VERSION 5.7 ;
  NOWIREEXTENSIONATPIN ON ;
  DIVIDERCHAR "/" ;
  BUSBITCHARS "[]" ;
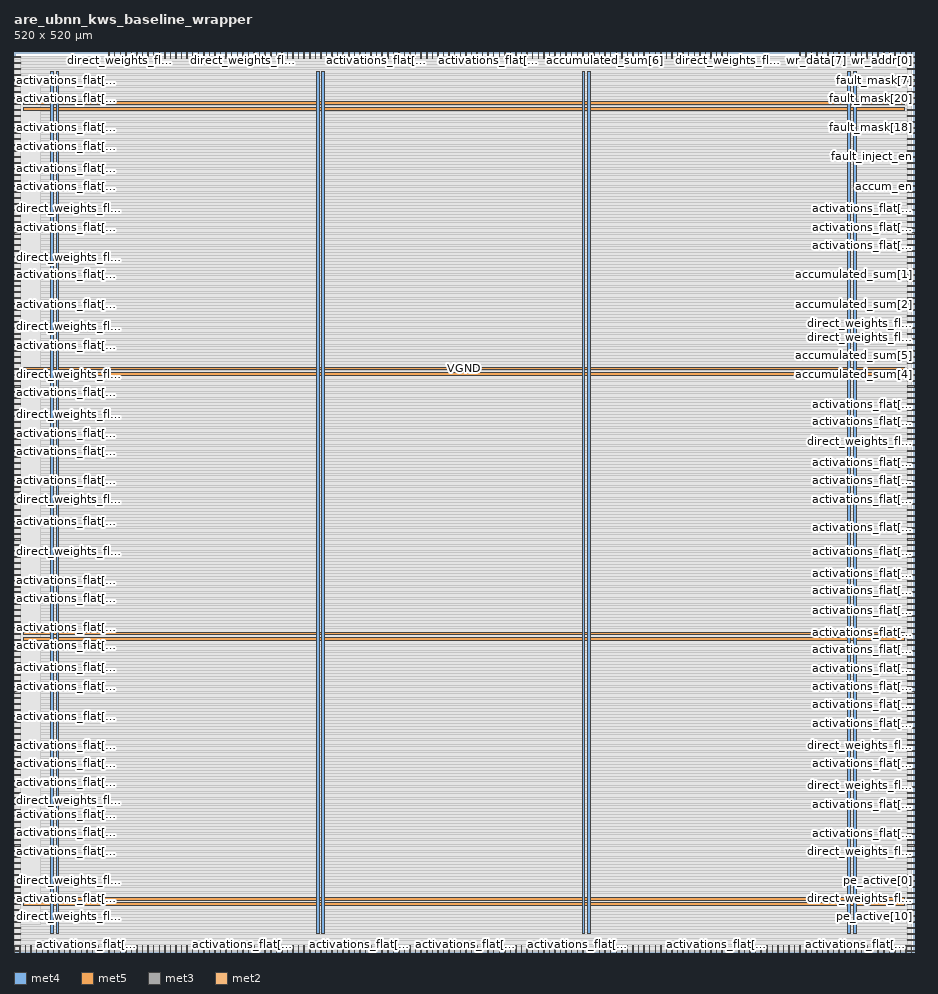
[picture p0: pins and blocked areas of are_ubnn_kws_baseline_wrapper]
MACRO are_ubnn_kws_baseline_wrapper
  CLASS BLOCK ;
  FOREIGN are_ubnn_kws_baseline_wrapper ;
  ORIGIN 0.000 0.000 ;
  SIZE 520.000 BY 520.000 ;
  PIN VGND
    DIRECTION INOUT ;
    USE GROUND ;
    PORT
      LAYER met4 ;
        RECT 24.340 10.640 25.940 508.880 ;
    END
    PORT
      LAYER met4 ;
        RECT 177.940 10.640 179.540 508.880 ;
    END
    PORT
      LAYER met4 ;
        RECT 331.540 10.640 333.140 508.880 ;
    END
    PORT
      LAYER met4 ;
        RECT 485.140 10.640 486.740 508.880 ;
    END
    PORT
      LAYER met5 ;
        RECT 5.280 30.030 514.520 31.630 ;
    END
    PORT
      LAYER met5 ;
        RECT 5.280 183.210 514.520 184.810 ;
    END
    PORT
      LAYER met5 ;
        RECT 5.280 336.390 514.520 337.990 ;
    END
    PORT
      LAYER met5 ;
        RECT 5.280 489.570 514.520 491.170 ;
    END
  END VGND
  PIN VPWR
    DIRECTION INOUT ;
    USE POWER ;
    PORT
      LAYER met4 ;
        RECT 21.040 10.640 22.640 508.880 ;
    END
    PORT
      LAYER met4 ;
        RECT 174.640 10.640 176.240 508.880 ;
    END
    PORT
      LAYER met4 ;
        RECT 328.240 10.640 329.840 508.880 ;
    END
    PORT
      LAYER met4 ;
        RECT 481.840 10.640 483.440 508.880 ;
    END
    PORT
      LAYER met5 ;
        RECT 5.280 26.730 514.520 28.330 ;
    END
    PORT
      LAYER met5 ;
        RECT 5.280 179.910 514.520 181.510 ;
    END
    PORT
      LAYER met5 ;
        RECT 5.280 333.090 514.520 334.690 ;
    END
    PORT
      LAYER met5 ;
        RECT 5.280 486.270 514.520 487.870 ;
    END
  END VPWR
  PIN accum_en
    DIRECTION INPUT ;
    USE SIGNAL ;
    ANTENNAGATEAREA 0.426000 ;
    PORT
      LAYER met3 ;
        RECT 516.000 442.040 520.000 442.640 ;
    END
  END accum_en
  PIN accum_valid
    DIRECTION OUTPUT ;
    USE SIGNAL ;
    ANTENNADIFFAREA 0.891000 ;
    PORT
      LAYER met2 ;
        RECT 409.030 516.000 409.310 520.000 ;
    END
  END accum_valid
  PIN accumulated_sum[0]
    DIRECTION OUTPUT ;
    USE SIGNAL ;
    ANTENNADIFFAREA 0.891000 ;
    PORT
      LAYER met3 ;
        RECT 516.000 411.440 520.000 412.040 ;
    END
  END accumulated_sum[0]
  PIN accumulated_sum[1]
    DIRECTION OUTPUT ;
    USE SIGNAL ;
    ANTENNADIFFAREA 0.891000 ;
    PORT
      LAYER met3 ;
        RECT 516.000 391.040 520.000 391.640 ;
    END
  END accumulated_sum[1]
  PIN accumulated_sum[2]
    DIRECTION OUTPUT ;
    USE SIGNAL ;
    ANTENNADIFFAREA 0.891000 ;
    PORT
      LAYER met3 ;
        RECT 516.000 374.040 520.000 374.640 ;
    END
  END accumulated_sum[2]
  PIN accumulated_sum[3]
    DIRECTION OUTPUT ;
    USE SIGNAL ;
    ANTENNADIFFAREA 0.891000 ;
    PORT
      LAYER met3 ;
        RECT 516.000 397.840 520.000 398.440 ;
    END
  END accumulated_sum[3]
  PIN accumulated_sum[4]
    DIRECTION OUTPUT ;
    USE SIGNAL ;
    ANTENNADIFFAREA 0.891000 ;
    PORT
      LAYER met3 ;
        RECT 516.000 333.240 520.000 333.840 ;
    END
  END accumulated_sum[4]
  PIN accumulated_sum[5]
    DIRECTION OUTPUT ;
    USE SIGNAL ;
    ANTENNADIFFAREA 0.891000 ;
    PORT
      LAYER met3 ;
        RECT 516.000 340.040 520.000 340.640 ;
    END
  END accumulated_sum[5]
  PIN accumulated_sum[6]
    DIRECTION OUTPUT ;
    USE SIGNAL ;
    ANTENNADIFFAREA 0.891000 ;
    PORT
      LAYER met2 ;
        RECT 341.410 516.000 341.690 520.000 ;
    END
  END accumulated_sum[6]
  PIN accumulated_sum[7]
    DIRECTION OUTPUT ;
    USE SIGNAL ;
    ANTENNADIFFAREA 0.891000 ;
    PORT
      LAYER met2 ;
        RECT 357.510 516.000 357.790 520.000 ;
    END
  END accumulated_sum[7]
  PIN accumulated_sum[8]
    DIRECTION OUTPUT ;
    USE SIGNAL ;
    ANTENNADIFFAREA 0.891000 ;
    PORT
      LAYER met2 ;
        RECT 347.850 516.000 348.130 520.000 ;
    END
  END accumulated_sum[8]
  PIN activations_flat[0]
    DIRECTION INPUT ;
    USE SIGNAL ;
    ANTENNAGATEAREA 0.196500 ;
    PORT
      LAYER met3 ;
        RECT 0.000 272.040 4.000 272.640 ;
    END
  END activations_flat[0]
  PIN activations_flat[100]
    DIRECTION INPUT ;
    USE SIGNAL ;
    ANTENNAGATEAREA 0.196500 ;
    PORT
      LAYER met2 ;
        RECT 177.190 0.000 177.470 4.000 ;
    END
  END activations_flat[100]
  PIN activations_flat[101]
    DIRECTION INPUT ;
    USE SIGNAL ;
    ANTENNAGATEAREA 0.213000 ;
    PORT
      LAYER met2 ;
        RECT 457.330 0.000 457.610 4.000 ;
    END
  END activations_flat[101]
  PIN activations_flat[102]
    DIRECTION INPUT ;
    USE SIGNAL ;
    ANTENNAGATEAREA 0.196500 ;
    PORT
      LAYER met2 ;
        RECT 222.270 0.000 222.550 4.000 ;
    END
  END activations_flat[102]
  PIN activations_flat[103]
    DIRECTION INPUT ;
    USE SIGNAL ;
    ANTENNAGATEAREA 0.213000 ;
    PORT
      LAYER met2 ;
        RECT 486.310 0.000 486.590 4.000 ;
    END
  END activations_flat[103]
  PIN activations_flat[104]
    DIRECTION INPUT ;
    USE SIGNAL ;
    ANTENNAGATEAREA 0.196500 ;
    PORT
      LAYER met2 ;
        RECT 225.490 0.000 225.770 4.000 ;
    END
  END activations_flat[104]
  PIN activations_flat[105]
    DIRECTION INPUT ;
    USE SIGNAL ;
    ANTENNAGATEAREA 0.196500 ;
    PORT
      LAYER met2 ;
        RECT 254.470 0.000 254.750 4.000 ;
    END
  END activations_flat[105]
  PIN activations_flat[106]
    DIRECTION INPUT ;
    USE SIGNAL ;
    ANTENNAGATEAREA 0.196500 ;
    PORT
      LAYER met2 ;
        RECT 235.150 0.000 235.430 4.000 ;
    END
  END activations_flat[106]
  PIN activations_flat[107]
    DIRECTION INPUT ;
    USE SIGNAL ;
    ANTENNAGATEAREA 0.213000 ;
    PORT
      LAYER met2 ;
        RECT 492.750 0.000 493.030 4.000 ;
    END
  END activations_flat[107]
  PIN activations_flat[108]
    DIRECTION INPUT ;
    USE SIGNAL ;
    ANTENNAGATEAREA 0.196500 ;
    PORT
      LAYER met2 ;
        RECT 238.370 0.000 238.650 4.000 ;
    END
  END activations_flat[108]
  PIN activations_flat[109]
    DIRECTION INPUT ;
    USE SIGNAL ;
    ANTENNAGATEAREA 0.196500 ;
    PORT
      LAYER met2 ;
        RECT 264.130 0.000 264.410 4.000 ;
    END
  END activations_flat[109]
  PIN activations_flat[10]
    DIRECTION INPUT ;
    USE SIGNAL ;
    ANTENNAGATEAREA 0.196500 ;
    PORT
      LAYER met3 ;
        RECT 0.000 292.440 4.000 293.040 ;
    END
  END activations_flat[10]
  PIN activations_flat[110]
    DIRECTION INPUT ;
    USE SIGNAL ;
    ANTENNAGATEAREA 0.196500 ;
    PORT
      LAYER met2 ;
        RECT 244.810 0.000 245.090 4.000 ;
    END
  END activations_flat[110]
  PIN activations_flat[111]
    DIRECTION INPUT ;
    USE SIGNAL ;
    ANTENNAGATEAREA 0.196500 ;
    PORT
      LAYER met2 ;
        RECT 215.830 0.000 216.110 4.000 ;
    END
  END activations_flat[111]
  PIN activations_flat[112]
    DIRECTION INPUT ;
    USE SIGNAL ;
    ANTENNAGATEAREA 0.196500 ;
    PORT
      LAYER met2 ;
        RECT 132.110 0.000 132.390 4.000 ;
    END
  END activations_flat[112]
  PIN activations_flat[113]
    DIRECTION INPUT ;
    USE SIGNAL ;
    ANTENNAGATEAREA 0.196500 ;
    PORT
      LAYER met3 ;
        RECT 0.000 57.840 4.000 58.440 ;
    END
  END activations_flat[113]
  PIN activations_flat[114]
    DIRECTION INPUT ;
    USE SIGNAL ;
    ANTENNAGATEAREA 0.126000 ;
    PORT
      LAYER met3 ;
        RECT 0.000 108.840 4.000 109.440 ;
    END
  END activations_flat[114]
  PIN activations_flat[115]
    DIRECTION INPUT ;
    USE SIGNAL ;
    ANTENNAGATEAREA 0.196500 ;
    PORT
      LAYER met2 ;
        RECT 80.590 0.000 80.870 4.000 ;
    END
  END activations_flat[115]
  PIN activations_flat[116]
    DIRECTION INPUT ;
    USE SIGNAL ;
    ANTENNAGATEAREA 0.126000 ;
    PORT
      LAYER met3 ;
        RECT 0.000 153.040 4.000 153.640 ;
    END
  END activations_flat[116]
  PIN activations_flat[117]
    DIRECTION INPUT ;
    USE SIGNAL ;
    ANTENNAGATEAREA 0.196500 ;
    PORT
      LAYER met2 ;
        RECT 170.750 0.000 171.030 4.000 ;
    END
  END activations_flat[117]
  PIN activations_flat[118]
    DIRECTION INPUT ;
    USE SIGNAL ;
    ANTENNAGATEAREA 0.196500 ;
    PORT
      LAYER met2 ;
        RECT 106.350 0.000 106.630 4.000 ;
    END
  END activations_flat[118]
  PIN activations_flat[119]
    DIRECTION INPUT ;
    USE SIGNAL ;
    ANTENNAGATEAREA 0.196500 ;
    PORT
      LAYER met2 ;
        RECT 109.570 0.000 109.850 4.000 ;
    END
  END activations_flat[119]
  PIN activations_flat[11]
    DIRECTION INPUT ;
    USE SIGNAL ;
    ANTENNAGATEAREA 0.196500 ;
    PORT
      LAYER met3 ;
        RECT 0.000 489.640 4.000 490.240 ;
    END
  END activations_flat[11]
  PIN activations_flat[120]
    DIRECTION INPUT ;
    USE SIGNAL ;
    ANTENNAGATEAREA 0.196500 ;
    PORT
      LAYER met2 ;
        RECT 96.690 0.000 96.970 4.000 ;
    END
  END activations_flat[120]
  PIN activations_flat[121]
    DIRECTION INPUT ;
    USE SIGNAL ;
    ANTENNAGATEAREA 0.196500 ;
    PORT
      LAYER met2 ;
        RECT 199.730 0.000 200.010 4.000 ;
    END
  END activations_flat[121]
  PIN activations_flat[122]
    DIRECTION INPUT ;
    USE SIGNAL ;
    ANTENNAGATEAREA 0.196500 ;
    PORT
      LAYER met2 ;
        RECT 183.630 0.000 183.910 4.000 ;
    END
  END activations_flat[122]
  PIN activations_flat[123]
    DIRECTION INPUT ;
    USE SIGNAL ;
    ANTENNAGATEAREA 0.196500 ;
    PORT
      LAYER met2 ;
        RECT 209.390 0.000 209.670 4.000 ;
    END
  END activations_flat[123]
  PIN activations_flat[124]
    DIRECTION INPUT ;
    USE SIGNAL ;
    ANTENNAGATEAREA 0.196500 ;
    PORT
      LAYER met2 ;
        RECT 193.290 0.000 193.570 4.000 ;
    END
  END activations_flat[124]
  PIN activations_flat[125]
    DIRECTION INPUT ;
    USE SIGNAL ;
    ANTENNAGATEAREA 0.196500 ;
    PORT
      LAYER met2 ;
        RECT 135.330 0.000 135.610 4.000 ;
    END
  END activations_flat[125]
  PIN activations_flat[126]
    DIRECTION INPUT ;
    USE SIGNAL ;
    ANTENNAGATEAREA 0.196500 ;
    PORT
      LAYER met2 ;
        RECT 190.070 0.000 190.350 4.000 ;
    END
  END activations_flat[126]
  PIN activations_flat[127]
    DIRECTION INPUT ;
    USE SIGNAL ;
    ANTENNAGATEAREA 0.196500 ;
    PORT
      LAYER met2 ;
        RECT 67.710 0.000 67.990 4.000 ;
    END
  END activations_flat[127]
  PIN activations_flat[128]
    DIRECTION INPUT ;
    USE SIGNAL ;
    ANTENNAGATEAREA 0.196500 ;
    PORT
      LAYER met2 ;
        RECT 479.870 0.000 480.150 4.000 ;
    END
  END activations_flat[128]
  PIN activations_flat[129]
    DIRECTION INPUT ;
    USE SIGNAL ;
    ANTENNAGATEAREA 0.196500 ;
    PORT
      LAYER met2 ;
        RECT 325.310 0.000 325.590 4.000 ;
    END
  END activations_flat[129]
  PIN activations_flat[12]
    DIRECTION INPUT ;
    USE SIGNAL ;
    ANTENNAGATEAREA 0.213000 ;
    PORT
      LAYER met3 ;
        RECT 0.000 496.440 4.000 497.040 ;
    END
  END activations_flat[12]
  PIN activations_flat[130]
    DIRECTION INPUT ;
    USE SIGNAL ;
    ANTENNAGATEAREA 0.196500 ;
    PORT
      LAYER met2 ;
        RECT 363.950 0.000 364.230 4.000 ;
    END
  END activations_flat[130]
  PIN activations_flat[131]
    DIRECTION INPUT ;
    USE SIGNAL ;
    ANTENNAGATEAREA 0.196500 ;
    PORT
      LAYER met2 ;
        RECT 357.510 0.000 357.790 4.000 ;
    END
  END activations_flat[131]
  PIN activations_flat[132]
    DIRECTION INPUT ;
    USE SIGNAL ;
    ANTENNAGATEAREA 0.196500 ;
    PORT
      LAYER met2 ;
        RECT 299.550 0.000 299.830 4.000 ;
    END
  END activations_flat[132]
  PIN activations_flat[133]
    DIRECTION INPUT ;
    USE SIGNAL ;
    ANTENNAGATEAREA 0.196500 ;
    PORT
      LAYER met2 ;
        RECT 428.350 0.000 428.630 4.000 ;
    END
  END activations_flat[133]
  PIN activations_flat[134]
    DIRECTION INPUT ;
    USE SIGNAL ;
    ANTENNAGATEAREA 0.196500 ;
    PORT
      LAYER met2 ;
        RECT 418.690 0.000 418.970 4.000 ;
    END
  END activations_flat[134]
  PIN activations_flat[135]
    DIRECTION INPUT ;
    USE SIGNAL ;
    ANTENNAGATEAREA 0.196500 ;
    PORT
      LAYER met2 ;
        RECT 438.010 0.000 438.290 4.000 ;
    END
  END activations_flat[135]
  PIN activations_flat[136]
    DIRECTION INPUT ;
    USE SIGNAL ;
    ANTENNAGATEAREA 0.196500 ;
    PORT
      LAYER met2 ;
        RECT 302.770 0.000 303.050 4.000 ;
    END
  END activations_flat[136]
  PIN activations_flat[137]
    DIRECTION INPUT ;
    USE SIGNAL ;
    ANTENNAGATEAREA 0.196500 ;
    PORT
      LAYER met2 ;
        RECT 351.070 0.000 351.350 4.000 ;
    END
  END activations_flat[137]
  PIN activations_flat[138]
    DIRECTION INPUT ;
    USE SIGNAL ;
    ANTENNAGATEAREA 0.196500 ;
    PORT
      LAYER met2 ;
        RECT 463.770 0.000 464.050 4.000 ;
    END
  END activations_flat[138]
  PIN activations_flat[139]
    DIRECTION INPUT ;
    USE SIGNAL ;
    ANTENNAGATEAREA 0.196500 ;
    PORT
      LAYER met2 ;
        RECT 505.630 0.000 505.910 4.000 ;
    END
  END activations_flat[139]
  PIN activations_flat[13]
    DIRECTION INPUT ;
    USE SIGNAL ;
    ANTENNAGATEAREA 0.213000 ;
    PORT
      LAYER met3 ;
        RECT 0.000 472.640 4.000 473.240 ;
    END
  END activations_flat[13]
  PIN activations_flat[140]
    DIRECTION INPUT ;
    USE SIGNAL ;
    ANTENNAGATEAREA 0.196500 ;
    PORT
      LAYER met2 ;
        RECT 370.390 0.000 370.670 4.000 ;
    END
  END activations_flat[140]
  PIN activations_flat[141]
    DIRECTION INPUT ;
    USE SIGNAL ;
    ANTENNAGATEAREA 0.196500 ;
    PORT
      LAYER met2 ;
        RECT 405.810 0.000 406.090 4.000 ;
    END
  END activations_flat[141]
  PIN activations_flat[142]
    DIRECTION INPUT ;
    USE SIGNAL ;
    ANTENNAGATEAREA 0.196500 ;
    PORT
      LAYER met2 ;
        RECT 354.290 0.000 354.570 4.000 ;
    END
  END activations_flat[142]
  PIN activations_flat[143]
    DIRECTION INPUT ;
    USE SIGNAL ;
    ANTENNAGATEAREA 0.196500 ;
    PORT
      LAYER met2 ;
        RECT 444.450 0.000 444.730 4.000 ;
    END
  END activations_flat[143]
  PIN activations_flat[144]
    DIRECTION INPUT ;
    USE SIGNAL ;
    ANTENNAGATEAREA 0.196500 ;
    PORT
      LAYER met2 ;
        RECT 260.910 0.000 261.190 4.000 ;
    END
  END activations_flat[144]
  PIN activations_flat[145]
    DIRECTION INPUT ;
    USE SIGNAL ;
    ANTENNAGATEAREA 0.196500 ;
    PORT
      LAYER met2 ;
        RECT 77.370 0.000 77.650 4.000 ;
    END
  END activations_flat[145]
  PIN activations_flat[146]
    DIRECTION INPUT ;
    USE SIGNAL ;
    ANTENNAGATEAREA 0.213000 ;
    PORT
      LAYER met2 ;
        RECT 141.770 0.000 142.050 4.000 ;
    END
  END activations_flat[146]
  PIN activations_flat[147]
    DIRECTION INPUT ;
    USE SIGNAL ;
    ANTENNAGATEAREA 0.213000 ;
    PORT
      LAYER met3 ;
        RECT 516.000 231.240 520.000 231.840 ;
    END
  END activations_flat[147]
  PIN activations_flat[148]
    DIRECTION INPUT ;
    USE SIGNAL ;
    ANTENNAGATEAREA 0.126000 ;
    PORT
      LAYER met2 ;
        RECT 22.630 0.000 22.910 4.000 ;
    END
  END activations_flat[148]
  PIN activations_flat[149]
    DIRECTION INPUT ;
    USE SIGNAL ;
    ANTENNAGATEAREA 0.196500 ;
    PORT
      LAYER met2 ;
        RECT 289.890 0.000 290.170 4.000 ;
    END
  END activations_flat[149]
  PIN activations_flat[14]
    DIRECTION INPUT ;
    USE SIGNAL ;
    ANTENNAGATEAREA 0.213000 ;
    PORT
      LAYER met3 ;
        RECT 0.000 516.840 4.000 517.440 ;
    END
  END activations_flat[14]
  PIN activations_flat[150]
    DIRECTION INPUT ;
    USE SIGNAL ;
    ANTENNAGATEAREA 0.213000 ;
    PORT
      LAYER met2 ;
        RECT 41.950 0.000 42.230 4.000 ;
    END
  END activations_flat[150]
  PIN activations_flat[151]
    DIRECTION INPUT ;
    USE SIGNAL ;
    ANTENNAGATEAREA 0.196500 ;
    PORT
      LAYER met2 ;
        RECT 473.430 0.000 473.710 4.000 ;
    END
  END activations_flat[151]
  PIN activations_flat[152]
    DIRECTION INPUT ;
    USE SIGNAL ;
    ANTENNAGATEAREA 0.196500 ;
    PORT
      LAYER met2 ;
        RECT 112.790 0.000 113.070 4.000 ;
    END
  END activations_flat[152]
  PIN activations_flat[153]
    DIRECTION INPUT ;
    USE SIGNAL ;
    ANTENNAGATEAREA 0.213000 ;
    PORT
      LAYER met2 ;
        RECT 495.970 0.000 496.250 4.000 ;
    END
  END activations_flat[153]
  PIN activations_flat[154]
    DIRECTION INPUT ;
    USE SIGNAL ;
    ANTENNAGATEAREA 0.213000 ;
    PORT
      LAYER met2 ;
        RECT 19.410 0.000 19.690 4.000 ;
    END
  END activations_flat[154]
  PIN activations_flat[155]
    DIRECTION INPUT ;
    USE SIGNAL ;
    ANTENNAGATEAREA 0.196500 ;
    PORT
      LAYER met2 ;
        RECT 283.450 0.000 283.730 4.000 ;
    END
  END activations_flat[155]
  PIN activations_flat[156]
    DIRECTION INPUT ;
    USE SIGNAL ;
    ANTENNAGATEAREA 0.196500 ;
    PORT
      LAYER met2 ;
        RECT 12.970 0.000 13.250 4.000 ;
    END
  END activations_flat[156]
  PIN activations_flat[157]
    DIRECTION INPUT ;
    USE SIGNAL ;
    ANTENNAGATEAREA 0.213000 ;
    PORT
      LAYER met2 ;
        RECT 502.410 0.000 502.690 4.000 ;
    END
  END activations_flat[157]
  PIN activations_flat[158]
    DIRECTION INPUT ;
    USE SIGNAL ;
    ANTENNAGATEAREA 0.196500 ;
    PORT
      LAYER met2 ;
        RECT 48.390 0.000 48.670 4.000 ;
    END
  END activations_flat[158]
  PIN activations_flat[159]
    DIRECTION INPUT ;
    USE SIGNAL ;
    ANTENNAGATEAREA 0.196500 ;
    PORT
      LAYER met2 ;
        RECT 144.990 0.000 145.270 4.000 ;
    END
  END activations_flat[159]
  PIN activations_flat[15]
    DIRECTION INPUT ;
    USE SIGNAL ;
    ANTENNAGATEAREA 0.196500 ;
    PORT
      LAYER met3 ;
        RECT 0.000 295.840 4.000 296.440 ;
    END
  END activations_flat[15]
  PIN activations_flat[160]
    DIRECTION INPUT ;
    USE SIGNAL ;
    ANTENNAGATEAREA 0.196500 ;
    PORT
      LAYER met3 ;
        RECT 0.000 248.240 4.000 248.840 ;
    END
  END activations_flat[160]
  PIN activations_flat[161]
    DIRECTION INPUT ;
    USE SIGNAL ;
    ANTENNAGATEAREA 0.196500 ;
    PORT
      LAYER met3 ;
        RECT 0.000 244.840 4.000 245.440 ;
    END
  END activations_flat[161]
  PIN activations_flat[162]
    DIRECTION INPUT ;
    USE SIGNAL ;
    ANTENNAGATEAREA 0.213000 ;
    PORT
      LAYER met3 ;
        RECT 0.000 6.840 4.000 7.440 ;
    END
  END activations_flat[162]
  PIN activations_flat[163]
    DIRECTION INPUT ;
    USE SIGNAL ;
    ANTENNAGATEAREA 0.196500 ;
    PORT
      LAYER met2 ;
        RECT 277.010 0.000 277.290 4.000 ;
    END
  END activations_flat[163]
  PIN activations_flat[164]
    DIRECTION INPUT ;
    USE SIGNAL ;
    ANTENNAGATEAREA 0.196500 ;
    PORT
      LAYER met3 ;
        RECT 0.000 166.640 4.000 167.240 ;
    END
  END activations_flat[164]
  PIN activations_flat[165]
    DIRECTION INPUT ;
    USE SIGNAL ;
    ANTENNAGATEAREA 0.126000 ;
    PORT
      LAYER met2 ;
        RECT 0.090 0.000 0.370 4.000 ;
    END
  END activations_flat[165]
  PIN activations_flat[166]
    DIRECTION INPUT ;
    USE SIGNAL ;
    ANTENNAGATEAREA 0.126000 ;
    PORT
      LAYER met3 ;
        RECT 0.000 112.240 4.000 112.840 ;
    END
  END activations_flat[166]
  PIN activations_flat[167]
    DIRECTION INPUT ;
    USE SIGNAL ;
    ANTENNAGATEAREA 0.196500 ;
    PORT
      LAYER met2 ;
        RECT 267.350 0.000 267.630 4.000 ;
    END
  END activations_flat[167]
  PIN activations_flat[168]
    DIRECTION INPUT ;
    USE SIGNAL ;
    ANTENNAGATEAREA 0.196500 ;
    PORT
      LAYER met3 ;
        RECT 0.000 214.240 4.000 214.840 ;
    END
  END activations_flat[168]
  PIN activations_flat[169]
    DIRECTION INPUT ;
    USE SIGNAL ;
    ANTENNAGATEAREA 0.196500 ;
    PORT
      LAYER met3 ;
        RECT 0.000 234.640 4.000 235.240 ;
    END
  END activations_flat[169]
  PIN activations_flat[16]
    DIRECTION INPUT ;
    USE SIGNAL ;
    ANTENNAGATEAREA 0.196500 ;
    PORT
      LAYER met3 ;
        RECT 0.000 387.640 4.000 388.240 ;
    END
  END activations_flat[16]
  PIN activations_flat[170]
    DIRECTION INPUT ;
    USE SIGNAL ;
    ANTENNAGATEAREA 0.196500 ;
    PORT
      LAYER met3 ;
        RECT 0.000 251.640 4.000 252.240 ;
    END
  END activations_flat[170]
  PIN activations_flat[171]
    DIRECTION INPUT ;
    USE SIGNAL ;
    ANTENNAGATEAREA 0.196500 ;
    PORT
      LAYER met3 ;
        RECT 0.000 255.040 4.000 255.640 ;
    END
  END activations_flat[171]
  PIN activations_flat[172]
    DIRECTION INPUT ;
    USE SIGNAL ;
    ANTENNAGATEAREA 0.213000 ;
    PORT
      LAYER met3 ;
        RECT 0.000 513.440 4.000 514.040 ;
    END
  END activations_flat[172]
  PIN activations_flat[173]
    DIRECTION INPUT ;
    USE SIGNAL ;
    ANTENNAGATEAREA 0.196500 ;
    PORT
      LAYER met3 ;
        RECT 0.000 261.840 4.000 262.440 ;
    END
  END activations_flat[173]
  PIN activations_flat[174]
    DIRECTION INPUT ;
    USE SIGNAL ;
    ANTENNAGATEAREA 0.196500 ;
    PORT
      LAYER met3 ;
        RECT 0.000 343.440 4.000 344.040 ;
    END
  END activations_flat[174]
  PIN activations_flat[175]
    DIRECTION INPUT ;
    USE SIGNAL ;
    ANTENNAGATEAREA 0.196500 ;
    PORT
      LAYER met3 ;
        RECT 0.000 183.640 4.000 184.240 ;
    END
  END activations_flat[175]
  PIN activations_flat[176]
    DIRECTION INPUT ;
    USE SIGNAL ;
    ANTENNAGATEAREA 0.196500 ;
    PORT
      LAYER met2 ;
        RECT 318.870 516.000 319.150 520.000 ;
    END
  END activations_flat[176]
  PIN activations_flat[177]
    DIRECTION INPUT ;
    USE SIGNAL ;
    ANTENNAGATEAREA 0.196500 ;
    PORT
      LAYER met2 ;
        RECT 389.710 516.000 389.990 520.000 ;
    END
  END activations_flat[177]
  PIN activations_flat[178]
    DIRECTION INPUT ;
    USE SIGNAL ;
    ANTENNAGATEAREA 0.196500 ;
    PORT
      LAYER met2 ;
        RECT 399.370 516.000 399.650 520.000 ;
    END
  END activations_flat[178]
  PIN activations_flat[179]
    DIRECTION INPUT ;
    USE SIGNAL ;
    ANTENNAGATEAREA 0.196500 ;
    PORT
      LAYER met2 ;
        RECT 309.210 516.000 309.490 520.000 ;
    END
  END activations_flat[179]
  PIN activations_flat[17]
    DIRECTION INPUT ;
    USE SIGNAL ;
    ANTENNAGATEAREA 0.126000 ;
    PORT
      LAYER met3 ;
        RECT 0.000 462.440 4.000 463.040 ;
    END
  END activations_flat[17]
  PIN activations_flat[180]
    DIRECTION INPUT ;
    USE SIGNAL ;
    ANTENNAGATEAREA 0.196500 ;
    PORT
      LAYER met2 ;
        RECT 383.270 516.000 383.550 520.000 ;
    END
  END activations_flat[180]
  PIN activations_flat[181]
    DIRECTION INPUT ;
    USE SIGNAL ;
    ANTENNAGATEAREA 0.196500 ;
    PORT
      LAYER met2 ;
        RECT 296.330 516.000 296.610 520.000 ;
    END
  END activations_flat[181]
  PIN activations_flat[182]
    DIRECTION INPUT ;
    USE SIGNAL ;
    ANTENNAGATEAREA 0.196500 ;
    PORT
      LAYER met2 ;
        RECT 392.930 516.000 393.210 520.000 ;
    END
  END activations_flat[182]
  PIN activations_flat[183]
    DIRECTION INPUT ;
    USE SIGNAL ;
    ANTENNAGATEAREA 0.196500 ;
    PORT
      LAYER met2 ;
        RECT 289.890 516.000 290.170 520.000 ;
    END
  END activations_flat[183]
  PIN activations_flat[184]
    DIRECTION INPUT ;
    USE SIGNAL ;
    ANTENNAGATEAREA 0.196500 ;
    PORT
      LAYER met2 ;
        RECT 402.590 516.000 402.870 520.000 ;
    END
  END activations_flat[184]
  PIN activations_flat[185]
    DIRECTION INPUT ;
    USE SIGNAL ;
    ANTENNAGATEAREA 0.196500 ;
    PORT
      LAYER met2 ;
        RECT 270.570 516.000 270.850 520.000 ;
    END
  END activations_flat[185]
  PIN activations_flat[186]
    DIRECTION INPUT ;
    USE SIGNAL ;
    ANTENNAGATEAREA 0.196500 ;
    PORT
      LAYER met2 ;
        RECT 376.830 516.000 377.110 520.000 ;
    END
  END activations_flat[186]
  PIN activations_flat[187]
    DIRECTION INPUT ;
    USE SIGNAL ;
    ANTENNAGATEAREA 0.196500 ;
    PORT
      LAYER met2 ;
        RECT 283.450 516.000 283.730 520.000 ;
    END
  END activations_flat[187]
  PIN activations_flat[188]
    DIRECTION INPUT ;
    USE SIGNAL ;
    ANTENNAGATEAREA 0.196500 ;
    PORT
      LAYER met2 ;
        RECT 264.130 516.000 264.410 520.000 ;
    END
  END activations_flat[188]
  PIN activations_flat[189]
    DIRECTION INPUT ;
    USE SIGNAL ;
    ANTENNAGATEAREA 0.196500 ;
    PORT
      LAYER met2 ;
        RECT 273.790 516.000 274.070 520.000 ;
    END
  END activations_flat[189]
  PIN activations_flat[18]
    DIRECTION INPUT ;
    USE SIGNAL ;
    ANTENNAGATEAREA 0.196500 ;
    PORT
      LAYER met3 ;
        RECT 0.000 323.040 4.000 323.640 ;
    END
  END activations_flat[18]
  PIN activations_flat[190]
    DIRECTION INPUT ;
    USE SIGNAL ;
    ANTENNAGATEAREA 0.196500 ;
    PORT
      LAYER met2 ;
        RECT 260.910 516.000 261.190 520.000 ;
    END
  END activations_flat[190]
  PIN activations_flat[191]
    DIRECTION INPUT ;
    USE SIGNAL ;
    ANTENNAGATEAREA 0.196500 ;
    PORT
      LAYER met2 ;
        RECT 251.250 516.000 251.530 520.000 ;
    END
  END activations_flat[191]
  PIN activations_flat[192]
    DIRECTION INPUT ;
    USE SIGNAL ;
    ANTENNAGATEAREA 0.196500 ;
    PORT
      LAYER met2 ;
        RECT 383.270 0.000 383.550 4.000 ;
    END
  END activations_flat[192]
  PIN activations_flat[193]
    DIRECTION INPUT ;
    USE SIGNAL ;
    ANTENNAGATEAREA 0.196500 ;
    PORT
      LAYER met2 ;
        RECT 315.650 0.000 315.930 4.000 ;
    END
  END activations_flat[193]
  PIN activations_flat[194]
    DIRECTION INPUT ;
    USE SIGNAL ;
    ANTENNAGATEAREA 0.196500 ;
    PORT
      LAYER met2 ;
        RECT 347.850 0.000 348.130 4.000 ;
    END
  END activations_flat[194]
  PIN activations_flat[195]
    DIRECTION INPUT ;
    USE SIGNAL ;
    ANTENNAGATEAREA 0.196500 ;
    PORT
      LAYER met3 ;
        RECT 516.000 51.040 520.000 51.640 ;
    END
  END activations_flat[195]
  PIN activations_flat[196]
    DIRECTION INPUT ;
    USE SIGNAL ;
    ANTENNAGATEAREA 0.196500 ;
    PORT
      LAYER met2 ;
        RECT 389.710 0.000 389.990 4.000 ;
    END
  END activations_flat[196]
  PIN activations_flat[197]
    DIRECTION INPUT ;
    USE SIGNAL ;
    ANTENNAGATEAREA 0.196500 ;
    PORT
      LAYER met3 ;
        RECT 516.000 68.040 520.000 68.640 ;
    END
  END activations_flat[197]
  PIN activations_flat[198]
    DIRECTION INPUT ;
    USE SIGNAL ;
    ANTENNAGATEAREA 0.196500 ;
    PORT
      LAYER met2 ;
        RECT 447.670 0.000 447.950 4.000 ;
    END
  END activations_flat[198]
  PIN activations_flat[199]
    DIRECTION INPUT ;
    USE SIGNAL ;
    ANTENNAGATEAREA 0.196500 ;
    PORT
      LAYER met3 ;
        RECT 516.000 64.640 520.000 65.240 ;
    END
  END activations_flat[199]
  PIN activations_flat[19]
    DIRECTION INPUT ;
    USE SIGNAL ;
    ANTENNAGATEAREA 0.126000 ;
    PORT
      LAYER met3 ;
        RECT 0.000 455.640 4.000 456.240 ;
    END
  END activations_flat[19]
  PIN activations_flat[1]
    DIRECTION INPUT ;
    USE SIGNAL ;
    ANTENNAGATEAREA 0.196500 ;
    PORT
      LAYER met3 ;
        RECT 0.000 312.840 4.000 313.440 ;
    END
  END activations_flat[1]
  PIN activations_flat[200]
    DIRECTION INPUT ;
    USE SIGNAL ;
    ANTENNAGATEAREA 0.196500 ;
    PORT
      LAYER met2 ;
        RECT 380.050 0.000 380.330 4.000 ;
    END
  END activations_flat[200]
  PIN activations_flat[201]
    DIRECTION INPUT ;
    USE SIGNAL ;
    ANTENNAGATEAREA 0.196500 ;
    PORT
      LAYER met2 ;
        RECT 499.190 0.000 499.470 4.000 ;
    END
  END activations_flat[201]
  PIN activations_flat[202]
    DIRECTION INPUT ;
    USE SIGNAL ;
    ANTENNAGATEAREA 0.126000 ;
    PORT
      LAYER met2 ;
        RECT 334.970 0.000 335.250 4.000 ;
    END
  END activations_flat[202]
  PIN activations_flat[203]
    DIRECTION INPUT ;
    USE SIGNAL ;
    ANTENNAGATEAREA 0.196500 ;
    PORT
      LAYER met2 ;
        RECT 518.510 0.000 518.790 4.000 ;
    END
  END activations_flat[203]
  PIN activations_flat[204]
    DIRECTION INPUT ;
    USE SIGNAL ;
    ANTENNAGATEAREA 0.196500 ;
    PORT
      LAYER met2 ;
        RECT 402.590 0.000 402.870 4.000 ;
    END
  END activations_flat[204]
  PIN activations_flat[205]
    DIRECTION INPUT ;
    USE SIGNAL ;
    ANTENNAGATEAREA 0.196500 ;
    PORT
      LAYER met2 ;
        RECT 373.610 0.000 373.890 4.000 ;
    END
  END activations_flat[205]
  PIN activations_flat[206]
    DIRECTION INPUT ;
    USE SIGNAL ;
    ANTENNAGATEAREA 0.196500 ;
    PORT
      LAYER met2 ;
        RECT 344.630 0.000 344.910 4.000 ;
    END
  END activations_flat[206]
  PIN activations_flat[207]
    DIRECTION INPUT ;
    USE SIGNAL ;
    ANTENNAGATEAREA 0.196500 ;
    PORT
      LAYER met2 ;
        RECT 328.530 0.000 328.810 4.000 ;
    END
  END activations_flat[207]
  PIN activations_flat[208]
    DIRECTION INPUT ;
    USE SIGNAL ;
    ANTENNAGATEAREA 0.196500 ;
    PORT
      LAYER met3 ;
        RECT 516.000 112.240 520.000 112.840 ;
    END
  END activations_flat[208]
  PIN activations_flat[209]
    DIRECTION INPUT ;
    USE SIGNAL ;
    ANTENNAGATEAREA 0.196500 ;
    PORT
      LAYER met3 ;
        RECT 516.000 122.440 520.000 123.040 ;
    END
  END activations_flat[209]
  PIN activations_flat[20]
    DIRECTION INPUT ;
    USE SIGNAL ;
    ANTENNAGATEAREA 0.196500 ;
    PORT
      LAYER met3 ;
        RECT 0.000 326.440 4.000 327.040 ;
    END
  END activations_flat[20]
  PIN activations_flat[210]
    DIRECTION INPUT ;
    USE SIGNAL ;
    ANTENNAGATEAREA 0.196500 ;
    PORT
      LAYER met3 ;
        RECT 516.000 105.440 520.000 106.040 ;
    END
  END activations_flat[210]
  PIN activations_flat[211]
    DIRECTION INPUT ;
    USE SIGNAL ;
    ANTENNAGATEAREA 0.126000 ;
    PORT
      LAYER met3 ;
        RECT 516.000 438.640 520.000 439.240 ;
    END
  END activations_flat[211]
  PIN activations_flat[212]
    DIRECTION INPUT ;
    USE SIGNAL ;
    ANTENNAGATEAREA 0.196500 ;
    PORT
      LAYER met3 ;
        RECT 516.000 132.640 520.000 133.240 ;
    END
  END activations_flat[212]
  PIN activations_flat[213]
    DIRECTION INPUT ;
    USE SIGNAL ;
    ANTENNAGATEAREA 0.126000 ;
    PORT
      LAYER met3 ;
        RECT 516.000 78.240 520.000 78.840 ;
    END
  END activations_flat[213]
  PIN activations_flat[214]
    DIRECTION INPUT ;
    USE SIGNAL ;
    ANTENNAGATEAREA 0.196500 ;
    PORT
      LAYER met3 ;
        RECT 516.000 149.640 520.000 150.240 ;
    END
  END activations_flat[214]
  PIN activations_flat[215]
    DIRECTION INPUT ;
    USE SIGNAL ;
    ANTENNAGATEAREA 0.196500 ;
    PORT
      LAYER met3 ;
        RECT 516.000 71.440 520.000 72.040 ;
    END
  END activations_flat[215]
  PIN activations_flat[216]
    DIRECTION INPUT ;
    USE SIGNAL ;
    ANTENNAGATEAREA 0.196500 ;
    PORT
      LAYER met3 ;
        RECT 516.000 163.240 520.000 163.840 ;
    END
  END activations_flat[216]
  PIN activations_flat[217]
    DIRECTION INPUT ;
    USE SIGNAL ;
    ANTENNAGATEAREA 0.196500 ;
    PORT
      LAYER met3 ;
        RECT 516.000 197.240 520.000 197.840 ;
    END
  END activations_flat[217]
  PIN activations_flat[218]
    DIRECTION INPUT ;
    USE SIGNAL ;
    ANTENNAGATEAREA 0.196500 ;
    PORT
      LAYER met3 ;
        RECT 516.000 170.040 520.000 170.640 ;
    END
  END activations_flat[218]
  PIN activations_flat[219]
    DIRECTION INPUT ;
    USE SIGNAL ;
    ANTENNAGATEAREA 0.196500 ;
    PORT
      LAYER met3 ;
        RECT 516.000 200.640 520.000 201.240 ;
    END
  END activations_flat[219]
  PIN activations_flat[21]
    DIRECTION INPUT ;
    USE SIGNAL ;
    ANTENNAGATEAREA 0.126000 ;
    PORT
      LAYER met3 ;
        RECT 0.000 503.240 4.000 503.840 ;
    END
  END activations_flat[21]
  PIN activations_flat[220]
    DIRECTION INPUT ;
    USE SIGNAL ;
    ANTENNAGATEAREA 0.196500 ;
    PORT
      LAYER met3 ;
        RECT 516.000 180.240 520.000 180.840 ;
    END
  END activations_flat[220]
  PIN activations_flat[221]
    DIRECTION INPUT ;
    USE SIGNAL ;
    ANTENNAGATEAREA 0.196500 ;
    PORT
      LAYER met3 ;
        RECT 516.000 142.840 520.000 143.440 ;
    END
  END activations_flat[221]
  PIN activations_flat[222]
    DIRECTION INPUT ;
    USE SIGNAL ;
    ANTENNAGATEAREA 0.196500 ;
    PORT
      LAYER met3 ;
        RECT 516.000 159.840 520.000 160.440 ;
    END
  END activations_flat[222]
  PIN activations_flat[223]
    DIRECTION INPUT ;
    USE SIGNAL ;
    ANTENNAGATEAREA 0.196500 ;
    PORT
      LAYER met3 ;
        RECT 516.000 153.040 520.000 153.640 ;
    END
  END activations_flat[223]
  PIN activations_flat[224]
    DIRECTION INPUT ;
    USE SIGNAL ;
    ANTENNAGATEAREA 0.196500 ;
    PORT
      LAYER met3 ;
        RECT 516.000 418.240 520.000 418.840 ;
    END
  END activations_flat[224]
  PIN activations_flat[225]
    DIRECTION INPUT ;
    USE SIGNAL ;
    ANTENNAGATEAREA 0.196500 ;
    PORT
      LAYER met3 ;
        RECT 516.000 353.640 520.000 354.240 ;
    END
  END activations_flat[225]
  PIN activations_flat[226]
    DIRECTION INPUT ;
    USE SIGNAL ;
    ANTENNAGATEAREA 0.196500 ;
    PORT
      LAYER met3 ;
        RECT 516.000 408.040 520.000 408.640 ;
    END
  END activations_flat[226]
  PIN activations_flat[227]
    DIRECTION INPUT ;
    USE SIGNAL ;
    ANTENNAGATEAREA 0.196500 ;
    PORT
      LAYER met3 ;
        RECT 516.000 306.040 520.000 306.640 ;
    END
  END activations_flat[227]
  PIN activations_flat[228]
    DIRECTION INPUT ;
    USE SIGNAL ;
    ANTENNAGATEAREA 0.196500 ;
    PORT
      LAYER met3 ;
        RECT 516.000 316.240 520.000 316.840 ;
    END
  END activations_flat[228]
  PIN activations_flat[229]
    DIRECTION INPUT ;
    USE SIGNAL ;
    ANTENNAGATEAREA 0.196500 ;
    PORT
      LAYER met3 ;
        RECT 516.000 309.440 520.000 310.040 ;
    END
  END activations_flat[229]
  PIN activations_flat[22]
    DIRECTION INPUT ;
    USE SIGNAL ;
    ANTENNAGATEAREA 0.196500 ;
    PORT
      LAYER met3 ;
        RECT 0.000 394.440 4.000 395.040 ;
    END
  END activations_flat[22]
  PIN activations_flat[230]
    DIRECTION INPUT ;
    USE SIGNAL ;
    ANTENNAGATEAREA 0.196500 ;
    PORT
      LAYER met3 ;
        RECT 516.000 323.040 520.000 323.640 ;
    END
  END activations_flat[230]
  PIN activations_flat[231]
    DIRECTION INPUT ;
    USE SIGNAL ;
    ANTENNAGATEAREA 0.196500 ;
    PORT
      LAYER met3 ;
        RECT 516.000 282.240 520.000 282.840 ;
    END
  END activations_flat[231]
  PIN activations_flat[232]
    DIRECTION INPUT ;
    USE SIGNAL ;
    ANTENNAGATEAREA 0.196500 ;
    PORT
      LAYER met3 ;
        RECT 516.000 414.840 520.000 415.440 ;
    END
  END activations_flat[232]
  PIN activations_flat[233]
    DIRECTION INPUT ;
    USE SIGNAL ;
    ANTENNAGATEAREA 0.196500 ;
    PORT
      LAYER met3 ;
        RECT 516.000 336.640 520.000 337.240 ;
    END
  END activations_flat[233]
  PIN activations_flat[234]
    DIRECTION INPUT ;
    USE SIGNAL ;
    ANTENNAGATEAREA 0.196500 ;
    PORT
      LAYER met3 ;
        RECT 516.000 370.640 520.000 371.240 ;
    END
  END activations_flat[234]
  PIN activations_flat[235]
    DIRECTION INPUT ;
    USE SIGNAL ;
    ANTENNAGATEAREA 0.196500 ;
    PORT
      LAYER met3 ;
        RECT 516.000 404.640 520.000 405.240 ;
    END
  END activations_flat[235]
  PIN activations_flat[236]
    DIRECTION INPUT ;
    USE SIGNAL ;
    ANTENNAGATEAREA 0.196500 ;
    PORT
      LAYER met3 ;
        RECT 516.000 384.240 520.000 384.840 ;
    END
  END activations_flat[236]
  PIN activations_flat[237]
    DIRECTION INPUT ;
    USE SIGNAL ;
    ANTENNAGATEAREA 0.196500 ;
    PORT
      LAYER met3 ;
        RECT 516.000 292.440 520.000 293.040 ;
    END
  END activations_flat[237]
  PIN activations_flat[238]
    DIRECTION INPUT ;
    USE SIGNAL ;
    ANTENNAGATEAREA 0.196500 ;
    PORT
      LAYER met3 ;
        RECT 516.000 312.840 520.000 313.440 ;
    END
  END activations_flat[238]
  PIN activations_flat[239]
    DIRECTION INPUT ;
    USE SIGNAL ;
    ANTENNAGATEAREA 0.196500 ;
    PORT
      LAYER met3 ;
        RECT 516.000 319.640 520.000 320.240 ;
    END
  END activations_flat[239]
  PIN activations_flat[23]
    DIRECTION INPUT ;
    USE SIGNAL ;
    ANTENNAGATEAREA 0.196500 ;
    PORT
      LAYER met3 ;
        RECT 0.000 476.040 4.000 476.640 ;
    END
  END activations_flat[23]
  PIN activations_flat[240]
    DIRECTION INPUT ;
    USE SIGNAL ;
    ANTENNAGATEAREA 0.126000 ;
    PORT
      LAYER met3 ;
        RECT 516.000 108.840 520.000 109.440 ;
    END
  END activations_flat[240]
  PIN activations_flat[241]
    DIRECTION INPUT ;
    USE SIGNAL ;
    ANTENNAGATEAREA 0.196500 ;
    PORT
      LAYER met3 ;
        RECT 516.000 244.840 520.000 245.440 ;
    END
  END activations_flat[241]
  PIN activations_flat[242]
    DIRECTION INPUT ;
    USE SIGNAL ;
    ANTENNAGATEAREA 0.196500 ;
    PORT
      LAYER met3 ;
        RECT 516.000 241.440 520.000 242.040 ;
    END
  END activations_flat[242]
  PIN activations_flat[243]
    DIRECTION INPUT ;
    USE SIGNAL ;
    ANTENNAGATEAREA 0.196500 ;
    PORT
      LAYER met3 ;
        RECT 516.000 425.040 520.000 425.640 ;
    END
  END activations_flat[243]
  PIN activations_flat[244]
    DIRECTION INPUT ;
    USE SIGNAL ;
    ANTENNAGATEAREA 0.196500 ;
    PORT
      LAYER met3 ;
        RECT 516.000 258.440 520.000 259.040 ;
    END
  END activations_flat[244]
  PIN activations_flat[245]
    DIRECTION INPUT ;
    USE SIGNAL ;
    ANTENNAGATEAREA 0.196500 ;
    PORT
      LAYER met3 ;
        RECT 516.000 272.040 520.000 272.640 ;
    END
  END activations_flat[245]
  PIN activations_flat[246]
    DIRECTION INPUT ;
    USE SIGNAL ;
    ANTENNAGATEAREA 0.196500 ;
    PORT
      LAYER met3 ;
        RECT 516.000 204.040 520.000 204.640 ;
    END
  END activations_flat[246]
  PIN activations_flat[247]
    DIRECTION INPUT ;
    USE SIGNAL ;
    ANTENNAGATEAREA 0.196500 ;
    PORT
      LAYER met3 ;
        RECT 516.000 401.240 520.000 401.840 ;
    END
  END activations_flat[247]
  PIN activations_flat[248]
    DIRECTION INPUT ;
    USE SIGNAL ;
    ANTENNAGATEAREA 0.196500 ;
    PORT
      LAYER met3 ;
        RECT 516.000 136.040 520.000 136.640 ;
    END
  END activations_flat[248]
  PIN activations_flat[249]
    DIRECTION INPUT ;
    USE SIGNAL ;
    ANTENNAGATEAREA 0.196500 ;
    PORT
      LAYER met3 ;
        RECT 516.000 387.640 520.000 388.240 ;
    END
  END activations_flat[249]
  PIN activations_flat[24]
    DIRECTION INPUT ;
    USE SIGNAL ;
    ANTENNAGATEAREA 0.196500 ;
    PORT
      LAYER met3 ;
        RECT 0.000 350.240 4.000 350.840 ;
    END
  END activations_flat[24]
  PIN activations_flat[250]
    DIRECTION INPUT ;
    USE SIGNAL ;
    ANTENNAGATEAREA 0.196500 ;
    PORT
      LAYER met3 ;
        RECT 516.000 214.240 520.000 214.840 ;
    END
  END activations_flat[250]
  PIN activations_flat[251]
    DIRECTION INPUT ;
    USE SIGNAL ;
    ANTENNAGATEAREA 0.126000 ;
    PORT
      LAYER met3 ;
        RECT 516.000 421.640 520.000 422.240 ;
    END
  END activations_flat[251]
  PIN activations_flat[252]
    DIRECTION INPUT ;
    USE SIGNAL ;
    ANTENNAGATEAREA 0.196500 ;
    PORT
      LAYER met3 ;
        RECT 516.000 95.240 520.000 95.840 ;
    END
  END activations_flat[252]
  PIN activations_flat[253]
    DIRECTION INPUT ;
    USE SIGNAL ;
    ANTENNAGATEAREA 0.196500 ;
    PORT
      LAYER met3 ;
        RECT 516.000 265.240 520.000 265.840 ;
    END
  END activations_flat[253]
  PIN activations_flat[254]
    DIRECTION INPUT ;
    USE SIGNAL ;
    ANTENNAGATEAREA 0.196500 ;
    PORT
      LAYER met3 ;
        RECT 516.000 85.040 520.000 85.640 ;
    END
  END activations_flat[254]
  PIN activations_flat[255]
    DIRECTION INPUT ;
    USE SIGNAL ;
    ANTENNAGATEAREA 0.196500 ;
    PORT
      LAYER met3 ;
        RECT 516.000 248.240 520.000 248.840 ;
    END
  END activations_flat[255]
  PIN activations_flat[25]
    DIRECTION INPUT ;
    USE SIGNAL ;
    ANTENNAGATEAREA 0.196500 ;
    PORT
      LAYER met3 ;
        RECT 0.000 319.640 4.000 320.240 ;
    END
  END activations_flat[25]
  PIN activations_flat[26]
    DIRECTION INPUT ;
    USE SIGNAL ;
    ANTENNAGATEAREA 0.196500 ;
    PORT
      LAYER met3 ;
        RECT 0.000 336.640 4.000 337.240 ;
    END
  END activations_flat[26]
  PIN activations_flat[27]
    DIRECTION INPUT ;
    USE SIGNAL ;
    ANTENNAGATEAREA 0.196500 ;
    PORT
      LAYER met3 ;
        RECT 0.000 404.640 4.000 405.240 ;
    END
  END activations_flat[27]
  PIN activations_flat[28]
    DIRECTION INPUT ;
    USE SIGNAL ;
    ANTENNAGATEAREA 0.196500 ;
    PORT
      LAYER met3 ;
        RECT 0.000 442.040 4.000 442.640 ;
    END
  END activations_flat[28]
  PIN activations_flat[29]
    DIRECTION INPUT ;
    USE SIGNAL ;
    ANTENNAGATEAREA 0.196500 ;
    PORT
      LAYER met3 ;
        RECT 0.000 377.440 4.000 378.040 ;
    END
  END activations_flat[29]
  PIN activations_flat[2]
    DIRECTION INPUT ;
    USE SIGNAL ;
    ANTENNAGATEAREA 0.213000 ;
    PORT
      LAYER met3 ;
        RECT 0.000 493.040 4.000 493.640 ;
    END
  END activations_flat[2]
  PIN activations_flat[30]
    DIRECTION INPUT ;
    USE SIGNAL ;
    ANTENNAGATEAREA 0.196500 ;
    PORT
      LAYER met3 ;
        RECT 0.000 486.240 4.000 486.840 ;
    END
  END activations_flat[30]
  PIN activations_flat[31]
    DIRECTION INPUT ;
    USE SIGNAL ;
    ANTENNAGATEAREA 0.196500 ;
    PORT
      LAYER met3 ;
        RECT 0.000 411.440 4.000 412.040 ;
    END
  END activations_flat[31]
  PIN activations_flat[32]
    DIRECTION INPUT ;
    USE SIGNAL ;
    ANTENNAGATEAREA 0.196500 ;
    PORT
      LAYER met2 ;
        RECT 54.830 516.000 55.110 520.000 ;
    END
  END activations_flat[32]
  PIN activations_flat[33]
    DIRECTION INPUT ;
    USE SIGNAL ;
    ANTENNAGATEAREA 0.196500 ;
    PORT
      LAYER met3 ;
        RECT 0.000 374.040 4.000 374.640 ;
    END
  END activations_flat[33]
  PIN activations_flat[34]
    DIRECTION INPUT ;
    USE SIGNAL ;
    ANTENNAGATEAREA 0.196500 ;
    PORT
      LAYER met3 ;
        RECT 0.000 445.440 4.000 446.040 ;
    END
  END activations_flat[34]
  PIN activations_flat[35]
    DIRECTION INPUT ;
    USE SIGNAL ;
    ANTENNAGATEAREA 0.196500 ;
    PORT
      LAYER met2 ;
        RECT 186.850 516.000 187.130 520.000 ;
    END
  END activations_flat[35]
  PIN activations_flat[36]
    DIRECTION INPUT ;
    USE SIGNAL ;
    ANTENNAGATEAREA 0.196500 ;
    PORT
      LAYER met3 ;
        RECT 0.000 418.240 4.000 418.840 ;
    END
  END activations_flat[36]
  PIN activations_flat[37]
    DIRECTION INPUT ;
    USE SIGNAL ;
    ANTENNAGATEAREA 0.196500 ;
    PORT
      LAYER met2 ;
        RECT 106.350 516.000 106.630 520.000 ;
    END
  END activations_flat[37]
  PIN activations_flat[38]
    DIRECTION INPUT ;
    USE SIGNAL ;
    ANTENNAGATEAREA 0.196500 ;
    PORT
      LAYER met3 ;
        RECT 0.000 391.040 4.000 391.640 ;
    END
  END activations_flat[38]
  PIN activations_flat[39]
    DIRECTION INPUT ;
    USE SIGNAL ;
    ANTENNAGATEAREA 0.196500 ;
    PORT
      LAYER met2 ;
        RECT 180.410 516.000 180.690 520.000 ;
    END
  END activations_flat[39]
  PIN activations_flat[3]
    DIRECTION INPUT ;
    USE SIGNAL ;
    ANTENNAGATEAREA 0.196500 ;
    PORT
      LAYER met3 ;
        RECT 0.000 289.040 4.000 289.640 ;
    END
  END activations_flat[3]
  PIN activations_flat[40]
    DIRECTION INPUT ;
    USE SIGNAL ;
    ANTENNAGATEAREA 0.196500 ;
    PORT
      LAYER met3 ;
        RECT 0.000 421.640 4.000 422.240 ;
    END
  END activations_flat[40]
  PIN activations_flat[41]
    DIRECTION INPUT ;
    USE SIGNAL ;
    ANTENNAGATEAREA 0.196500 ;
    PORT
      LAYER met2 ;
        RECT 167.530 516.000 167.810 520.000 ;
    END
  END activations_flat[41]
  PIN activations_flat[42]
    DIRECTION INPUT ;
    USE SIGNAL ;
    ANTENNAGATEAREA 0.196500 ;
    PORT
      LAYER met2 ;
        RECT 141.770 516.000 142.050 520.000 ;
    END
  END activations_flat[42]
  PIN activations_flat[43]
    DIRECTION INPUT ;
    USE SIGNAL ;
    ANTENNAGATEAREA 0.196500 ;
    PORT
      LAYER met2 ;
        RECT 64.490 516.000 64.770 520.000 ;
    END
  END activations_flat[43]
  PIN activations_flat[44]
    DIRECTION INPUT ;
    USE SIGNAL ;
    ANTENNAGATEAREA 0.196500 ;
    PORT
      LAYER met2 ;
        RECT 144.990 516.000 145.270 520.000 ;
    END
  END activations_flat[44]
  PIN activations_flat[45]
    DIRECTION INPUT ;
    USE SIGNAL ;
    ANTENNAGATEAREA 0.196500 ;
    PORT
      LAYER met2 ;
        RECT 96.690 516.000 96.970 520.000 ;
    END
  END activations_flat[45]
  PIN activations_flat[46]
    DIRECTION INPUT ;
    USE SIGNAL ;
    ANTENNAGATEAREA 0.126000 ;
    PORT
      LAYER met2 ;
        RECT 74.150 516.000 74.430 520.000 ;
    END
  END activations_flat[46]
  PIN activations_flat[47]
    DIRECTION INPUT ;
    USE SIGNAL ;
    ANTENNAGATEAREA 0.196500 ;
    PORT
      LAYER met3 ;
        RECT 0.000 479.440 4.000 480.040 ;
    END
  END activations_flat[47]
  PIN activations_flat[48]
    DIRECTION INPUT ;
    USE SIGNAL ;
    ANTENNAGATEAREA 0.196500 ;
    PORT
      LAYER met3 ;
        RECT 0.000 105.440 4.000 106.040 ;
    END
  END activations_flat[48]
  PIN activations_flat[49]
    DIRECTION INPUT ;
    USE SIGNAL ;
    ANTENNAGATEAREA 0.196500 ;
    PORT
      LAYER met3 ;
        RECT 0.000 78.240 4.000 78.840 ;
    END
  END activations_flat[49]
  PIN activations_flat[4]
    DIRECTION INPUT ;
    USE SIGNAL ;
    ANTENNAGATEAREA 0.196500 ;
    PORT
      LAYER met3 ;
        RECT 0.000 452.240 4.000 452.840 ;
    END
  END activations_flat[4]
  PIN activations_flat[50]
    DIRECTION INPUT ;
    USE SIGNAL ;
    ANTENNAGATEAREA 0.196500 ;
    PORT
      LAYER met3 ;
        RECT 0.000 37.440 4.000 38.040 ;
    END
  END activations_flat[50]
  PIN activations_flat[51]
    DIRECTION INPUT ;
    USE SIGNAL ;
    ANTENNAGATEAREA 0.126000 ;
    PORT
      LAYER met3 ;
        RECT 0.000 30.640 4.000 31.240 ;
    END
  END activations_flat[51]
  PIN activations_flat[52]
    DIRECTION INPUT ;
    USE SIGNAL ;
    ANTENNAGATEAREA 0.196500 ;
    PORT
      LAYER met3 ;
        RECT 0.000 176.840 4.000 177.440 ;
    END
  END activations_flat[52]
  PIN activations_flat[53]
    DIRECTION INPUT ;
    USE SIGNAL ;
    ANTENNAGATEAREA 0.126000 ;
    PORT
      LAYER met3 ;
        RECT 0.000 27.240 4.000 27.840 ;
    END
  END activations_flat[53]
  PIN activations_flat[54]
    DIRECTION INPUT ;
    USE SIGNAL ;
    ANTENNAGATEAREA 0.196500 ;
    PORT
      LAYER met3 ;
        RECT 0.000 64.640 4.000 65.240 ;
    END
  END activations_flat[54]
  PIN activations_flat[55]
    DIRECTION INPUT ;
    USE SIGNAL ;
    ANTENNAGATEAREA 0.196500 ;
    PORT
      LAYER met3 ;
        RECT 0.000 10.240 4.000 10.840 ;
    END
  END activations_flat[55]
  PIN activations_flat[56]
    DIRECTION INPUT ;
    USE SIGNAL ;
    ANTENNAGATEAREA 0.196500 ;
    PORT
      LAYER met3 ;
        RECT 0.000 149.640 4.000 150.240 ;
    END
  END activations_flat[56]
  PIN activations_flat[57]
    DIRECTION INPUT ;
    USE SIGNAL ;
    ANTENNAGATEAREA 0.196500 ;
    PORT
      LAYER met3 ;
        RECT 0.000 204.040 4.000 204.640 ;
    END
  END activations_flat[57]
  PIN activations_flat[58]
    DIRECTION INPUT ;
    USE SIGNAL ;
    ANTENNAGATEAREA 0.196500 ;
    PORT
      LAYER met3 ;
        RECT 0.000 13.640 4.000 14.240 ;
    END
  END activations_flat[58]
  PIN activations_flat[59]
    DIRECTION INPUT ;
    USE SIGNAL ;
    ANTENNAGATEAREA 0.196500 ;
    PORT
      LAYER met3 ;
        RECT 0.000 3.440 4.000 4.040 ;
    END
  END activations_flat[59]
  PIN activations_flat[5]
    DIRECTION INPUT ;
    USE SIGNAL ;
    ANTENNAGATEAREA 0.196500 ;
    PORT
      LAYER met3 ;
        RECT 0.000 278.840 4.000 279.440 ;
    END
  END activations_flat[5]
  PIN activations_flat[60]
    DIRECTION INPUT ;
    USE SIGNAL ;
    ANTENNAGATEAREA 0.196500 ;
    PORT
      LAYER met3 ;
        RECT 0.000 159.840 4.000 160.440 ;
    END
  END activations_flat[60]
  PIN activations_flat[61]
    DIRECTION INPUT ;
    USE SIGNAL ;
    ANTENNAGATEAREA 0.196500 ;
    PORT
      LAYER met3 ;
        RECT 0.000 173.440 4.000 174.040 ;
    END
  END activations_flat[61]
  PIN activations_flat[62]
    DIRECTION INPUT ;
    USE SIGNAL ;
    ANTENNAGATEAREA 0.196500 ;
    PORT
      LAYER met3 ;
        RECT 0.000 187.040 4.000 187.640 ;
    END
  END activations_flat[62]
  PIN activations_flat[63]
    DIRECTION INPUT ;
    USE SIGNAL ;
    ANTENNAGATEAREA 0.196500 ;
    PORT
      LAYER met3 ;
        RECT 0.000 88.440 4.000 89.040 ;
    END
  END activations_flat[63]
  PIN activations_flat[64]
    DIRECTION INPUT ;
    USE SIGNAL ;
    ANTENNAGATEAREA 0.196500 ;
    PORT
      LAYER met3 ;
        RECT 0.000 136.040 4.000 136.640 ;
    END
  END activations_flat[64]
  PIN activations_flat[65]
    DIRECTION INPUT ;
    USE SIGNAL ;
    ANTENNAGATEAREA 0.196500 ;
    PORT
      LAYER met3 ;
        RECT 0.000 139.440 4.000 140.040 ;
    END
  END activations_flat[65]
  PIN activations_flat[66]
    DIRECTION INPUT ;
    USE SIGNAL ;
    ANTENNAGATEAREA 0.196500 ;
    PORT
      LAYER met3 ;
        RECT 0.000 102.040 4.000 102.640 ;
    END
  END activations_flat[66]
  PIN activations_flat[67]
    DIRECTION INPUT ;
    USE SIGNAL ;
    ANTENNAGATEAREA 0.196500 ;
    PORT
      LAYER met2 ;
        RECT 93.470 0.000 93.750 4.000 ;
    END
  END activations_flat[67]
  PIN activations_flat[68]
    DIRECTION INPUT ;
    USE SIGNAL ;
    ANTENNAGATEAREA 0.196500 ;
    PORT
      LAYER met3 ;
        RECT 0.000 74.840 4.000 75.440 ;
    END
  END activations_flat[68]
  PIN activations_flat[69]
    DIRECTION INPUT ;
    USE SIGNAL ;
    ANTENNAGATEAREA 0.196500 ;
    PORT
      LAYER met2 ;
        RECT 161.090 0.000 161.370 4.000 ;
    END
  END activations_flat[69]
  PIN activations_flat[6]
    DIRECTION INPUT ;
    USE SIGNAL ;
    ANTENNAGATEAREA 0.196500 ;
    PORT
      LAYER met3 ;
        RECT 0.000 299.240 4.000 299.840 ;
    END
  END activations_flat[6]
  PIN activations_flat[70]
    DIRECTION INPUT ;
    USE SIGNAL ;
    ANTENNAGATEAREA 0.196500 ;
    PORT
      LAYER met3 ;
        RECT 0.000 54.440 4.000 55.040 ;
    END
  END activations_flat[70]
  PIN activations_flat[71]
    DIRECTION INPUT ;
    USE SIGNAL ;
    ANTENNAGATEAREA 0.196500 ;
    PORT
      LAYER met2 ;
        RECT 35.510 0.000 35.790 4.000 ;
    END
  END activations_flat[71]
  PIN activations_flat[72]
    DIRECTION INPUT ;
    USE SIGNAL ;
    ANTENNAGATEAREA 0.196500 ;
    PORT
      LAYER met3 ;
        RECT 0.000 23.840 4.000 24.440 ;
    END
  END activations_flat[72]
  PIN activations_flat[73]
    DIRECTION INPUT ;
    USE SIGNAL ;
    ANTENNAGATEAREA 0.213000 ;
    PORT
      LAYER met3 ;
        RECT 0.000 200.640 4.000 201.240 ;
    END
  END activations_flat[73]
  PIN activations_flat[74]
    DIRECTION INPUT ;
    USE SIGNAL ;
    ANTENNAGATEAREA 0.196500 ;
    PORT
      LAYER met3 ;
        RECT 0.000 0.040 4.000 0.640 ;
    END
  END activations_flat[74]
  PIN activations_flat[75]
    DIRECTION INPUT ;
    USE SIGNAL ;
    ANTENNAGATEAREA 0.126000 ;
    PORT
      LAYER met3 ;
        RECT 0.000 142.840 4.000 143.440 ;
    END
  END activations_flat[75]
  PIN activations_flat[76]
    DIRECTION INPUT ;
    USE SIGNAL ;
    ANTENNAGATEAREA 0.196500 ;
    PORT
      LAYER met3 ;
        RECT 0.000 119.040 4.000 119.640 ;
    END
  END activations_flat[76]
  PIN activations_flat[77]
    DIRECTION INPUT ;
    USE SIGNAL ;
    ANTENNAGATEAREA 0.213000 ;
    PORT
      LAYER met3 ;
        RECT 0.000 132.640 4.000 133.240 ;
    END
  END activations_flat[77]
  PIN activations_flat[78]
    DIRECTION INPUT ;
    USE SIGNAL ;
    ANTENNAGATEAREA 0.196500 ;
    PORT
      LAYER met3 ;
        RECT 0.000 34.040 4.000 34.640 ;
    END
  END activations_flat[78]
  PIN activations_flat[79]
    DIRECTION INPUT ;
    USE SIGNAL ;
    ANTENNAGATEAREA 0.196500 ;
    PORT
      LAYER met3 ;
        RECT 0.000 115.640 4.000 116.240 ;
    END
  END activations_flat[79]
  PIN activations_flat[7]
    DIRECTION INPUT ;
    USE SIGNAL ;
    ANTENNAGATEAREA 0.196500 ;
    PORT
      LAYER met3 ;
        RECT 0.000 414.840 4.000 415.440 ;
    END
  END activations_flat[7]
  PIN activations_flat[80]
    DIRECTION INPUT ;
    USE SIGNAL ;
    ANTENNAGATEAREA 0.196500 ;
    PORT
      LAYER met2 ;
        RECT 154.650 516.000 154.930 520.000 ;
    END
  END activations_flat[80]
  PIN activations_flat[81]
    DIRECTION INPUT ;
    USE SIGNAL ;
    ANTENNAGATEAREA 0.196500 ;
    PORT
      LAYER met2 ;
        RECT 183.630 516.000 183.910 520.000 ;
    END
  END activations_flat[81]
  PIN activations_flat[82]
    DIRECTION INPUT ;
    USE SIGNAL ;
    ANTENNAGATEAREA 0.196500 ;
    PORT
      LAYER met2 ;
        RECT 148.210 516.000 148.490 520.000 ;
    END
  END activations_flat[82]
  PIN activations_flat[83]
    DIRECTION INPUT ;
    USE SIGNAL ;
    ANTENNAGATEAREA 0.196500 ;
    PORT
      LAYER met2 ;
        RECT 244.810 516.000 245.090 520.000 ;
    END
  END activations_flat[83]
  PIN activations_flat[84]
    DIRECTION INPUT ;
    USE SIGNAL ;
    ANTENNAGATEAREA 0.196500 ;
    PORT
      LAYER met2 ;
        RECT 90.250 516.000 90.530 520.000 ;
    END
  END activations_flat[84]
  PIN activations_flat[85]
    DIRECTION INPUT ;
    USE SIGNAL ;
    ANTENNAGATEAREA 0.213000 ;
    PORT
      LAYER met2 ;
        RECT 405.810 516.000 406.090 520.000 ;
    END
  END activations_flat[85]
  PIN activations_flat[86]
    DIRECTION INPUT ;
    USE SIGNAL ;
    ANTENNAGATEAREA 0.196500 ;
    PORT
      LAYER met2 ;
        RECT 151.430 516.000 151.710 520.000 ;
    END
  END activations_flat[86]
  PIN activations_flat[87]
    DIRECTION INPUT ;
    USE SIGNAL ;
    ANTENNAGATEAREA 0.196500 ;
    PORT
      LAYER met2 ;
        RECT 235.150 516.000 235.430 520.000 ;
    END
  END activations_flat[87]
  PIN activations_flat[88]
    DIRECTION INPUT ;
    USE SIGNAL ;
    ANTENNAGATEAREA 0.196500 ;
    PORT
      LAYER met2 ;
        RECT 67.710 516.000 67.990 520.000 ;
    END
  END activations_flat[88]
  PIN activations_flat[89]
    DIRECTION INPUT ;
    USE SIGNAL ;
    ANTENNAGATEAREA 0.196500 ;
    PORT
      LAYER met2 ;
        RECT 209.390 516.000 209.670 520.000 ;
    END
  END activations_flat[89]
  PIN activations_flat[8]
    DIRECTION INPUT ;
    USE SIGNAL ;
    ANTENNAGATEAREA 0.213000 ;
    PORT
      LAYER met3 ;
        RECT 0.000 469.240 4.000 469.840 ;
    END
  END activations_flat[8]
  PIN activations_flat[90]
    DIRECTION INPUT ;
    USE SIGNAL ;
    ANTENNAGATEAREA 0.196500 ;
    PORT
      LAYER met2 ;
        RECT 199.730 516.000 200.010 520.000 ;
    END
  END activations_flat[90]
  PIN activations_flat[91]
    DIRECTION INPUT ;
    USE SIGNAL ;
    ANTENNAGATEAREA 0.196500 ;
    PORT
      LAYER met2 ;
        RECT 231.930 516.000 232.210 520.000 ;
    END
  END activations_flat[91]
  PIN activations_flat[92]
    DIRECTION INPUT ;
    USE SIGNAL ;
    ANTENNAGATEAREA 0.196500 ;
    PORT
      LAYER met2 ;
        RECT 202.950 516.000 203.230 520.000 ;
    END
  END activations_flat[92]
  PIN activations_flat[93]
    DIRECTION INPUT ;
    USE SIGNAL ;
    ANTENNAGATEAREA 0.196500 ;
    PORT
      LAYER met2 ;
        RECT 219.050 516.000 219.330 520.000 ;
    END
  END activations_flat[93]
  PIN activations_flat[94]
    DIRECTION INPUT ;
    USE SIGNAL ;
    ANTENNAGATEAREA 0.196500 ;
    PORT
      LAYER met2 ;
        RECT 206.170 516.000 206.450 520.000 ;
    END
  END activations_flat[94]
  PIN activations_flat[95]
    DIRECTION INPUT ;
    USE SIGNAL ;
    ANTENNAGATEAREA 0.196500 ;
    PORT
      LAYER met2 ;
        RECT 70.930 516.000 71.210 520.000 ;
    END
  END activations_flat[95]
  PIN activations_flat[96]
    DIRECTION INPUT ;
    USE SIGNAL ;
    ANTENNAGATEAREA 0.196500 ;
    PORT
      LAYER met2 ;
        RECT 248.030 0.000 248.310 4.000 ;
    END
  END activations_flat[96]
  PIN activations_flat[97]
    DIRECTION INPUT ;
    USE SIGNAL ;
    ANTENNAGATEAREA 0.196500 ;
    PORT
      LAYER met2 ;
        RECT 219.050 0.000 219.330 4.000 ;
    END
  END activations_flat[97]
  PIN activations_flat[98]
    DIRECTION INPUT ;
    USE SIGNAL ;
    ANTENNAGATEAREA 0.126000 ;
    PORT
      LAYER met2 ;
        RECT 103.130 0.000 103.410 4.000 ;
    END
  END activations_flat[98]
  PIN activations_flat[99]
    DIRECTION INPUT ;
    USE SIGNAL ;
    ANTENNAGATEAREA 0.196500 ;
    PORT
      LAYER met2 ;
        RECT 367.170 0.000 367.450 4.000 ;
    END
  END activations_flat[99]
  PIN activations_flat[9]
    DIRECTION INPUT ;
    USE SIGNAL ;
    ANTENNAGATEAREA 0.196500 ;
    PORT
      LAYER met3 ;
        RECT 0.000 282.240 4.000 282.840 ;
    END
  END activations_flat[9]
  PIN clk
    DIRECTION INPUT ;
    USE SIGNAL ;
    ANTENNAGATEAREA 1.286700 ;
    ANTENNADIFFAREA 0.434700 ;
    PORT
      LAYER met3 ;
        RECT 516.000 343.440 520.000 344.040 ;
    END
  END clk
  PIN direct_weights_flat[0]
    DIRECTION INPUT ;
    USE SIGNAL ;
    ANTENNAGATEAREA 0.213000 ;
    PORT
      LAYER met3 ;
        RECT 0.000 506.640 4.000 507.240 ;
    END
  END direct_weights_flat[0]
  PIN direct_weights_flat[100]
    DIRECTION INPUT ;
    USE SIGNAL ;
    ANTENNAGATEAREA 0.213000 ;
    PORT
      LAYER met2 ;
        RECT 29.070 0.000 29.350 4.000 ;
    END
  END direct_weights_flat[100]
  PIN direct_weights_flat[101]
    DIRECTION INPUT ;
    USE SIGNAL ;
    ANTENNAGATEAREA 0.196500 ;
    PORT
      LAYER met2 ;
        RECT 293.110 0.000 293.390 4.000 ;
    END
  END direct_weights_flat[101]
  PIN direct_weights_flat[102]
    DIRECTION INPUT ;
    USE SIGNAL ;
    ANTENNAGATEAREA 0.196500 ;
    PORT
      LAYER met2 ;
        RECT 231.930 0.000 232.210 4.000 ;
    END
  END direct_weights_flat[102]
  PIN direct_weights_flat[103]
    DIRECTION INPUT ;
    USE SIGNAL ;
    ANTENNAGATEAREA 0.196500 ;
    PORT
      LAYER met2 ;
        RECT 280.230 0.000 280.510 4.000 ;
    END
  END direct_weights_flat[103]
  PIN direct_weights_flat[104]
    DIRECTION INPUT ;
    USE SIGNAL ;
    ANTENNAGATEAREA 0.196500 ;
    PORT
      LAYER met2 ;
        RECT 228.710 0.000 228.990 4.000 ;
    END
  END direct_weights_flat[104]
  PIN direct_weights_flat[105]
    DIRECTION INPUT ;
    USE SIGNAL ;
    ANTENNAGATEAREA 0.196500 ;
    PORT
      LAYER met2 ;
        RECT 251.250 0.000 251.530 4.000 ;
    END
  END direct_weights_flat[105]
  PIN direct_weights_flat[106]
    DIRECTION INPUT ;
    USE SIGNAL ;
    ANTENNAGATEAREA 0.213000 ;
    PORT
      LAYER met2 ;
        RECT 38.730 0.000 39.010 4.000 ;
    END
  END direct_weights_flat[106]
  PIN direct_weights_flat[107]
    DIRECTION INPUT ;
    USE SIGNAL ;
    ANTENNAGATEAREA 0.196500 ;
    PORT
      LAYER met2 ;
        RECT 305.990 0.000 306.270 4.000 ;
    END
  END direct_weights_flat[107]
  PIN direct_weights_flat[108]
    DIRECTION INPUT ;
    USE SIGNAL ;
    ANTENNAGATEAREA 0.126000 ;
    PORT
      LAYER met2 ;
        RECT 148.210 0.000 148.490 4.000 ;
    END
  END direct_weights_flat[108]
  PIN direct_weights_flat[109]
    DIRECTION INPUT ;
    USE SIGNAL ;
    ANTENNAGATEAREA 0.126000 ;
    PORT
      LAYER met2 ;
        RECT 421.910 0.000 422.190 4.000 ;
    END
  END direct_weights_flat[109]
  PIN direct_weights_flat[10]
    DIRECTION INPUT ;
    USE SIGNAL ;
    ANTENNAGATEAREA 0.196500 ;
    PORT
      LAYER met3 ;
        RECT 0.000 285.640 4.000 286.240 ;
    END
  END direct_weights_flat[10]
  PIN direct_weights_flat[110]
    DIRECTION INPUT ;
    USE SIGNAL ;
    ANTENNAGATEAREA 0.196500 ;
    PORT
      LAYER met2 ;
        RECT 241.590 0.000 241.870 4.000 ;
    END
  END direct_weights_flat[110]
  PIN direct_weights_flat[111]
    DIRECTION INPUT ;
    USE SIGNAL ;
    ANTENNAGATEAREA 0.196500 ;
    PORT
      LAYER met2 ;
        RECT 212.610 0.000 212.890 4.000 ;
    END
  END direct_weights_flat[111]
  PIN direct_weights_flat[112]
    DIRECTION INPUT ;
    USE SIGNAL ;
    ANTENNAGATEAREA 0.196500 ;
    PORT
      LAYER met2 ;
        RECT 196.510 0.000 196.790 4.000 ;
    END
  END direct_weights_flat[112]
  PIN direct_weights_flat[113]
    DIRECTION INPUT ;
    USE SIGNAL ;
    ANTENNAGATEAREA 0.213000 ;
    PORT
      LAYER met3 ;
        RECT 0.000 170.040 4.000 170.640 ;
    END
  END direct_weights_flat[113]
  PIN direct_weights_flat[114]
    DIRECTION INPUT ;
    USE SIGNAL ;
    ANTENNAGATEAREA 0.213000 ;
    PORT
      LAYER met3 ;
        RECT 0.000 146.240 4.000 146.840 ;
    END
  END direct_weights_flat[114]
  PIN direct_weights_flat[115]
    DIRECTION INPUT ;
    USE SIGNAL ;
    ANTENNAGATEAREA 0.196500 ;
    PORT
      LAYER met2 ;
        RECT 32.290 0.000 32.570 4.000 ;
    END
  END direct_weights_flat[115]
  PIN direct_weights_flat[116]
    DIRECTION INPUT ;
    USE SIGNAL ;
    ANTENNAGATEAREA 0.196500 ;
    PORT
      LAYER met3 ;
        RECT 0.000 47.640 4.000 48.240 ;
    END
  END direct_weights_flat[116]
  PIN direct_weights_flat[117]
    DIRECTION INPUT ;
    USE SIGNAL ;
    ANTENNAGATEAREA 0.196500 ;
    PORT
      LAYER met2 ;
        RECT 90.250 0.000 90.530 4.000 ;
    END
  END direct_weights_flat[117]
  PIN direct_weights_flat[118]
    DIRECTION INPUT ;
    USE SIGNAL ;
    ANTENNAGATEAREA 0.196500 ;
    PORT
      LAYER met2 ;
        RECT 180.410 0.000 180.690 4.000 ;
    END
  END direct_weights_flat[118]
  PIN direct_weights_flat[119]
    DIRECTION INPUT ;
    USE SIGNAL ;
    ANTENNAGATEAREA 0.196500 ;
    PORT
      LAYER met2 ;
        RECT 54.830 0.000 55.110 4.000 ;
    END
  END direct_weights_flat[119]
  PIN direct_weights_flat[11]
    DIRECTION INPUT ;
    USE SIGNAL ;
    ANTENNAGATEAREA 0.196500 ;
    PORT
      LAYER met3 ;
        RECT 0.000 459.040 4.000 459.640 ;
    END
  END direct_weights_flat[11]
  PIN direct_weights_flat[120]
    DIRECTION INPUT ;
    USE SIGNAL ;
    ANTENNAGATEAREA 0.196500 ;
    PORT
      LAYER met2 ;
        RECT 87.030 0.000 87.310 4.000 ;
    END
  END direct_weights_flat[120]
  PIN direct_weights_flat[121]
    DIRECTION INPUT ;
    USE SIGNAL ;
    ANTENNAGATEAREA 0.196500 ;
    PORT
      LAYER met2 ;
        RECT 83.810 0.000 84.090 4.000 ;
    END
  END direct_weights_flat[121]
  PIN direct_weights_flat[122]
    DIRECTION INPUT ;
    USE SIGNAL ;
    ANTENNAGATEAREA 0.196500 ;
    PORT
      LAYER met2 ;
        RECT 119.230 0.000 119.510 4.000 ;
    END
  END direct_weights_flat[122]
  PIN direct_weights_flat[123]
    DIRECTION INPUT ;
    USE SIGNAL ;
    ANTENNAGATEAREA 0.196500 ;
    PORT
      LAYER met2 ;
        RECT 206.170 0.000 206.450 4.000 ;
    END
  END direct_weights_flat[123]
  PIN direct_weights_flat[124]
    DIRECTION INPUT ;
    USE SIGNAL ;
    ANTENNAGATEAREA 0.196500 ;
    PORT
      LAYER met2 ;
        RECT 186.850 0.000 187.130 4.000 ;
    END
  END direct_weights_flat[124]
  PIN direct_weights_flat[125]
    DIRECTION INPUT ;
    USE SIGNAL ;
    ANTENNAGATEAREA 0.196500 ;
    PORT
      LAYER met2 ;
        RECT 202.950 0.000 203.230 4.000 ;
    END
  END direct_weights_flat[125]
  PIN direct_weights_flat[126]
    DIRECTION INPUT ;
    USE SIGNAL ;
    ANTENNAGATEAREA 0.213000 ;
    PORT
      LAYER met2 ;
        RECT 61.270 0.000 61.550 4.000 ;
    END
  END direct_weights_flat[126]
  PIN direct_weights_flat[127]
    DIRECTION INPUT ;
    USE SIGNAL ;
    ANTENNAGATEAREA 0.196500 ;
    PORT
      LAYER met2 ;
        RECT 74.150 0.000 74.430 4.000 ;
    END
  END direct_weights_flat[127]
  PIN direct_weights_flat[128]
    DIRECTION INPUT ;
    USE SIGNAL ;
    ANTENNAGATEAREA 0.196500 ;
    PORT
      LAYER met2 ;
        RECT 460.550 0.000 460.830 4.000 ;
    END
  END direct_weights_flat[128]
  PIN direct_weights_flat[129]
    DIRECTION INPUT ;
    USE SIGNAL ;
    ANTENNAGATEAREA 0.196500 ;
    PORT
      LAYER met2 ;
        RECT 318.870 0.000 319.150 4.000 ;
    END
  END direct_weights_flat[129]
  PIN direct_weights_flat[12]
    DIRECTION INPUT ;
    USE SIGNAL ;
    ANTENNAGATEAREA 0.196500 ;
    PORT
      LAYER met3 ;
        RECT 0.000 231.240 4.000 231.840 ;
    END
  END direct_weights_flat[12]
  PIN direct_weights_flat[130]
    DIRECTION INPUT ;
    USE SIGNAL ;
    ANTENNAGATEAREA 0.213000 ;
    PORT
      LAYER met2 ;
        RECT 512.070 0.000 512.350 4.000 ;
    END
  END direct_weights_flat[130]
  PIN direct_weights_flat[131]
    DIRECTION INPUT ;
    USE SIGNAL ;
    ANTENNAGATEAREA 0.196500 ;
    PORT
      LAYER met2 ;
        RECT 399.370 0.000 399.650 4.000 ;
    END
  END direct_weights_flat[131]
  PIN direct_weights_flat[132]
    DIRECTION INPUT ;
    USE SIGNAL ;
    ANTENNAGATEAREA 0.196500 ;
    PORT
      LAYER met2 ;
        RECT 376.830 0.000 377.110 4.000 ;
    END
  END direct_weights_flat[132]
  PIN direct_weights_flat[133]
    DIRECTION INPUT ;
    USE SIGNAL ;
    ANTENNAGATEAREA 0.196500 ;
    PORT
      LAYER met2 ;
        RECT 425.130 0.000 425.410 4.000 ;
    END
  END direct_weights_flat[133]
  PIN direct_weights_flat[134]
    DIRECTION INPUT ;
    USE SIGNAL ;
    ANTENNAGATEAREA 0.196500 ;
    PORT
      LAYER met2 ;
        RECT 470.210 0.000 470.490 4.000 ;
    END
  END direct_weights_flat[134]
  PIN direct_weights_flat[135]
    DIRECTION INPUT ;
    USE SIGNAL ;
    ANTENNAGATEAREA 0.196500 ;
    PORT
      LAYER met2 ;
        RECT 409.030 0.000 409.310 4.000 ;
    END
  END direct_weights_flat[135]
  PIN direct_weights_flat[136]
    DIRECTION INPUT ;
    USE SIGNAL ;
    ANTENNAGATEAREA 0.196500 ;
    PORT
      LAYER met2 ;
        RECT 331.750 0.000 332.030 4.000 ;
    END
  END direct_weights_flat[136]
  PIN direct_weights_flat[137]
    DIRECTION INPUT ;
    USE SIGNAL ;
    ANTENNAGATEAREA 0.196500 ;
    PORT
      LAYER met2 ;
        RECT 466.990 0.000 467.270 4.000 ;
    END
  END direct_weights_flat[137]
  PIN direct_weights_flat[138]
    DIRECTION INPUT ;
    USE SIGNAL ;
    ANTENNAGATEAREA 0.196500 ;
    PORT
      LAYER met2 ;
        RECT 412.250 0.000 412.530 4.000 ;
    END
  END direct_weights_flat[138]
  PIN direct_weights_flat[139]
    DIRECTION INPUT ;
    USE SIGNAL ;
    ANTENNAGATEAREA 0.196500 ;
    PORT
      LAYER met2 ;
        RECT 396.150 0.000 396.430 4.000 ;
    END
  END direct_weights_flat[139]
  PIN direct_weights_flat[13]
    DIRECTION INPUT ;
    USE SIGNAL ;
    ANTENNAGATEAREA 0.196500 ;
    PORT
      LAYER met3 ;
        RECT 0.000 275.440 4.000 276.040 ;
    END
  END direct_weights_flat[13]
  PIN direct_weights_flat[140]
    DIRECTION INPUT ;
    USE SIGNAL ;
    ANTENNAGATEAREA 0.196500 ;
    PORT
      LAYER met2 ;
        RECT 360.730 0.000 361.010 4.000 ;
    END
  END direct_weights_flat[140]
  PIN direct_weights_flat[141]
    DIRECTION INPUT ;
    USE SIGNAL ;
    ANTENNAGATEAREA 0.196500 ;
    PORT
      LAYER met2 ;
        RECT 441.230 0.000 441.510 4.000 ;
    END
  END direct_weights_flat[141]
  PIN direct_weights_flat[142]
    DIRECTION INPUT ;
    USE SIGNAL ;
    ANTENNAGATEAREA 0.196500 ;
    PORT
      LAYER met2 ;
        RECT 454.110 0.000 454.390 4.000 ;
    END
  END direct_weights_flat[142]
  PIN direct_weights_flat[143]
    DIRECTION INPUT ;
    USE SIGNAL ;
    ANTENNAGATEAREA 0.196500 ;
    PORT
      LAYER met2 ;
        RECT 322.090 0.000 322.370 4.000 ;
    END
  END direct_weights_flat[143]
  PIN direct_weights_flat[144]
    DIRECTION INPUT ;
    USE SIGNAL ;
    ANTENNAGATEAREA 0.159000 ;
    PORT
      LAYER met2 ;
        RECT 508.850 0.000 509.130 4.000 ;
    END
  END direct_weights_flat[144]
  PIN direct_weights_flat[145]
    DIRECTION INPUT ;
    USE SIGNAL ;
    ANTENNAGATEAREA 0.213000 ;
    PORT
      LAYER met2 ;
        RECT 6.530 0.000 6.810 4.000 ;
    END
  END direct_weights_flat[145]
  PIN direct_weights_flat[146]
    DIRECTION INPUT ;
    USE SIGNAL ;
    ANTENNAGATEAREA 0.126000 ;
    PORT
      LAYER met2 ;
        RECT 25.850 0.000 26.130 4.000 ;
    END
  END direct_weights_flat[146]
  PIN direct_weights_flat[147]
    DIRECTION INPUT ;
    USE SIGNAL ;
    ANTENNAGATEAREA 0.213000 ;
    PORT
      LAYER met3 ;
        RECT 516.000 227.840 520.000 228.440 ;
    END
  END direct_weights_flat[147]
  PIN direct_weights_flat[148]
    DIRECTION INPUT ;
    USE SIGNAL ;
    ANTENNAGATEAREA 0.126000 ;
    PORT
      LAYER met2 ;
        RECT 16.190 0.000 16.470 4.000 ;
    END
  END direct_weights_flat[148]
  PIN direct_weights_flat[149]
    DIRECTION INPUT ;
    USE SIGNAL ;
    ANTENNAGATEAREA 0.196500 ;
    PORT
      LAYER met2 ;
        RECT 309.210 0.000 309.490 4.000 ;
    END
  END direct_weights_flat[149]
  PIN direct_weights_flat[14]
    DIRECTION INPUT ;
    USE SIGNAL ;
    ANTENNAGATEAREA 0.126000 ;
    PORT
      LAYER met3 ;
        RECT 0.000 122.440 4.000 123.040 ;
    END
  END direct_weights_flat[14]
  PIN direct_weights_flat[150]
    DIRECTION INPUT ;
    USE SIGNAL ;
    ANTENNAGATEAREA 0.196500 ;
    PORT
      LAYER met2 ;
        RECT 128.890 0.000 129.170 4.000 ;
    END
  END direct_weights_flat[150]
  PIN direct_weights_flat[151]
    DIRECTION INPUT ;
    USE SIGNAL ;
    ANTENNAGATEAREA 0.196500 ;
    PORT
      LAYER met2 ;
        RECT 483.090 0.000 483.370 4.000 ;
    END
  END direct_weights_flat[151]
  PIN direct_weights_flat[152]
    DIRECTION INPUT ;
    USE SIGNAL ;
    ANTENNAGATEAREA 0.213000 ;
    PORT
      LAYER met2 ;
        RECT 51.610 0.000 51.890 4.000 ;
    END
  END direct_weights_flat[152]
  PIN direct_weights_flat[153]
    DIRECTION INPUT ;
    USE SIGNAL ;
    ANTENNAGATEAREA 0.196500 ;
    PORT
      LAYER met2 ;
        RECT 273.790 0.000 274.070 4.000 ;
    END
  END direct_weights_flat[153]
  PIN direct_weights_flat[154]
    DIRECTION INPUT ;
    USE SIGNAL ;
    ANTENNAGATEAREA 0.196500 ;
    PORT
      LAYER met2 ;
        RECT 164.310 0.000 164.590 4.000 ;
    END
  END direct_weights_flat[154]
  PIN direct_weights_flat[155]
    DIRECTION INPUT ;
    USE SIGNAL ;
    ANTENNAGATEAREA 0.196500 ;
    PORT
      LAYER met2 ;
        RECT 296.330 0.000 296.610 4.000 ;
    END
  END direct_weights_flat[155]
  PIN direct_weights_flat[156]
    DIRECTION INPUT ;
    USE SIGNAL ;
    ANTENNAGATEAREA 0.196500 ;
    PORT
      LAYER met2 ;
        RECT 45.170 0.000 45.450 4.000 ;
    END
  END direct_weights_flat[156]
  PIN direct_weights_flat[157]
    DIRECTION INPUT ;
    USE SIGNAL ;
    ANTENNAGATEAREA 0.196500 ;
    PORT
      LAYER met2 ;
        RECT 270.570 0.000 270.850 4.000 ;
    END
  END direct_weights_flat[157]
  PIN direct_weights_flat[158]
    DIRECTION INPUT ;
    USE SIGNAL ;
    ANTENNAGATEAREA 0.196500 ;
    PORT
      LAYER met2 ;
        RECT 9.750 0.000 10.030 4.000 ;
    END
  END direct_weights_flat[158]
  PIN direct_weights_flat[159]
    DIRECTION INPUT ;
    USE SIGNAL ;
    ANTENNAGATEAREA 0.196500 ;
    PORT
      LAYER met2 ;
        RECT 151.430 0.000 151.710 4.000 ;
    END
  END direct_weights_flat[159]
  PIN direct_weights_flat[15]
    DIRECTION INPUT ;
    USE SIGNAL ;
    ANTENNAGATEAREA 0.196500 ;
    PORT
      LAYER met3 ;
        RECT 0.000 384.240 4.000 384.840 ;
    END
  END direct_weights_flat[15]
  PIN direct_weights_flat[160]
    DIRECTION INPUT ;
    USE SIGNAL ;
    ANTENNAGATEAREA 0.196500 ;
    PORT
      LAYER met3 ;
        RECT 0.000 265.240 4.000 265.840 ;
    END
  END direct_weights_flat[160]
  PIN direct_weights_flat[161]
    DIRECTION INPUT ;
    USE SIGNAL ;
    ANTENNAGATEAREA 0.126000 ;
    PORT
      LAYER met3 ;
        RECT 0.000 129.240 4.000 129.840 ;
    END
  END direct_weights_flat[161]
  PIN direct_weights_flat[162]
    DIRECTION INPUT ;
    USE SIGNAL ;
    ANTENNAGATEAREA 0.196500 ;
    PORT
      LAYER met3 ;
        RECT 0.000 238.040 4.000 238.640 ;
    END
  END direct_weights_flat[162]
  PIN direct_weights_flat[163]
    DIRECTION INPUT ;
    USE SIGNAL ;
    ANTENNAGATEAREA 0.196500 ;
    PORT
      LAYER met2 ;
        RECT 286.670 0.000 286.950 4.000 ;
    END
  END direct_weights_flat[163]
  PIN direct_weights_flat[164]
    DIRECTION INPUT ;
    USE SIGNAL ;
    ANTENNAGATEAREA 0.196500 ;
    PORT
      LAYER met3 ;
        RECT 0.000 241.440 4.000 242.040 ;
    END
  END direct_weights_flat[164]
  PIN direct_weights_flat[165]
    DIRECTION INPUT ;
    USE SIGNAL ;
    ANTENNAGATEAREA 0.196500 ;
    PORT
      LAYER met2 ;
        RECT 3.310 0.000 3.590 4.000 ;
    END
  END direct_weights_flat[165]
  PIN direct_weights_flat[166]
    DIRECTION INPUT ;
    USE SIGNAL ;
    ANTENNAGATEAREA 0.196500 ;
    PORT
      LAYER met3 ;
        RECT 0.000 217.640 4.000 218.240 ;
    END
  END direct_weights_flat[166]
  PIN direct_weights_flat[167]
    DIRECTION INPUT ;
    USE SIGNAL ;
    ANTENNAGATEAREA 0.196500 ;
    PORT
      LAYER met2 ;
        RECT 257.690 0.000 257.970 4.000 ;
    END
  END direct_weights_flat[167]
  PIN direct_weights_flat[168]
    DIRECTION INPUT ;
    USE SIGNAL ;
    ANTENNAGATEAREA 0.213000 ;
    PORT
      LAYER met3 ;
        RECT 0.000 61.240 4.000 61.840 ;
    END
  END direct_weights_flat[168]
  PIN direct_weights_flat[169]
    DIRECTION INPUT ;
    USE SIGNAL ;
    ANTENNAGATEAREA 0.196500 ;
    PORT
      LAYER met3 ;
        RECT 0.000 190.440 4.000 191.040 ;
    END
  END direct_weights_flat[169]
  PIN direct_weights_flat[16]
    DIRECTION INPUT ;
    USE SIGNAL ;
    ANTENNAGATEAREA 0.196500 ;
    PORT
      LAYER met3 ;
        RECT 0.000 397.840 4.000 398.440 ;
    END
  END direct_weights_flat[16]
  PIN direct_weights_flat[170]
    DIRECTION INPUT ;
    USE SIGNAL ;
    ANTENNAGATEAREA 0.196500 ;
    PORT
      LAYER met3 ;
        RECT 0.000 258.440 4.000 259.040 ;
    END
  END direct_weights_flat[170]
  PIN direct_weights_flat[171]
    DIRECTION INPUT ;
    USE SIGNAL ;
    ANTENNAGATEAREA 0.196500 ;
    PORT
      LAYER met3 ;
        RECT 0.000 224.440 4.000 225.040 ;
    END
  END direct_weights_flat[171]
  PIN direct_weights_flat[172]
    DIRECTION INPUT ;
    USE SIGNAL ;
    ANTENNAGATEAREA 0.213000 ;
    PORT
      LAYER met3 ;
        RECT 0.000 499.840 4.000 500.440 ;
    END
  END direct_weights_flat[172]
  PIN direct_weights_flat[173]
    DIRECTION INPUT ;
    USE SIGNAL ;
    ANTENNAGATEAREA 0.126000 ;
    PORT
      LAYER met3 ;
        RECT 0.000 81.640 4.000 82.240 ;
    END
  END direct_weights_flat[173]
  PIN direct_weights_flat[174]
    DIRECTION INPUT ;
    USE SIGNAL ;
    ANTENNAGATEAREA 0.196500 ;
    PORT
      LAYER met3 ;
        RECT 0.000 268.640 4.000 269.240 ;
    END
  END direct_weights_flat[174]
  PIN direct_weights_flat[175]
    DIRECTION INPUT ;
    USE SIGNAL ;
    ANTENNAGATEAREA 0.196500 ;
    PORT
      LAYER met3 ;
        RECT 0.000 227.840 4.000 228.440 ;
    END
  END direct_weights_flat[175]
  PIN direct_weights_flat[176]
    DIRECTION INPUT ;
    USE SIGNAL ;
    ANTENNAGATEAREA 0.196500 ;
    PORT
      LAYER met2 ;
        RECT 267.350 516.000 267.630 520.000 ;
    END
  END direct_weights_flat[176]
  PIN direct_weights_flat[177]
    DIRECTION INPUT ;
    USE SIGNAL ;
    ANTENNAGATEAREA 0.196500 ;
    PORT
      LAYER met2 ;
        RECT 373.610 516.000 373.890 520.000 ;
    END
  END direct_weights_flat[177]
  PIN direct_weights_flat[178]
    DIRECTION INPUT ;
    USE SIGNAL ;
    ANTENNAGATEAREA 0.196500 ;
    PORT
      LAYER met2 ;
        RECT 396.150 516.000 396.430 520.000 ;
    END
  END direct_weights_flat[178]
  PIN direct_weights_flat[179]
    DIRECTION INPUT ;
    USE SIGNAL ;
    ANTENNAGATEAREA 0.196500 ;
    PORT
      LAYER met2 ;
        RECT 302.770 516.000 303.050 520.000 ;
    END
  END direct_weights_flat[179]
  PIN direct_weights_flat[17]
    DIRECTION INPUT ;
    USE SIGNAL ;
    ANTENNAGATEAREA 0.196500 ;
    PORT
      LAYER met3 ;
        RECT 0.000 428.440 4.000 429.040 ;
    END
  END direct_weights_flat[17]
  PIN direct_weights_flat[180]
    DIRECTION INPUT ;
    USE SIGNAL ;
    ANTENNAGATEAREA 0.196500 ;
    PORT
      LAYER met2 ;
        RECT 257.690 516.000 257.970 520.000 ;
    END
  END direct_weights_flat[180]
  PIN direct_weights_flat[181]
    DIRECTION INPUT ;
    USE SIGNAL ;
    ANTENNAGATEAREA 0.196500 ;
    PORT
      LAYER met2 ;
        RECT 286.670 516.000 286.950 520.000 ;
    END
  END direct_weights_flat[181]
  PIN direct_weights_flat[182]
    DIRECTION INPUT ;
    USE SIGNAL ;
    ANTENNAGATEAREA 0.196500 ;
    PORT
      LAYER met2 ;
        RECT 386.490 516.000 386.770 520.000 ;
    END
  END direct_weights_flat[182]
  PIN direct_weights_flat[183]
    DIRECTION INPUT ;
    USE SIGNAL ;
    ANTENNAGATEAREA 0.196500 ;
    PORT
      LAYER met2 ;
        RECT 293.110 516.000 293.390 520.000 ;
    END
  END direct_weights_flat[183]
  PIN direct_weights_flat[184]
    DIRECTION INPUT ;
    USE SIGNAL ;
    ANTENNAGATEAREA 0.213000 ;
    PORT
      LAYER met2 ;
        RECT 248.030 516.000 248.310 520.000 ;
    END
  END direct_weights_flat[184]
  PIN direct_weights_flat[185]
    DIRECTION INPUT ;
    USE SIGNAL ;
    ANTENNAGATEAREA 0.196500 ;
    PORT
      LAYER met2 ;
        RECT 312.430 516.000 312.710 520.000 ;
    END
  END direct_weights_flat[185]
  PIN direct_weights_flat[186]
    DIRECTION INPUT ;
    USE SIGNAL ;
    ANTENNAGATEAREA 0.196500 ;
    PORT
      LAYER met2 ;
        RECT 254.470 516.000 254.750 520.000 ;
    END
  END direct_weights_flat[186]
  PIN direct_weights_flat[187]
    DIRECTION INPUT ;
    USE SIGNAL ;
    ANTENNAGATEAREA 0.196500 ;
    PORT
      LAYER met2 ;
        RECT 280.230 516.000 280.510 520.000 ;
    END
  END direct_weights_flat[187]
  PIN direct_weights_flat[188]
    DIRECTION INPUT ;
    USE SIGNAL ;
    ANTENNAGATEAREA 0.196500 ;
    PORT
      LAYER met2 ;
        RECT 322.090 516.000 322.370 520.000 ;
    END
  END direct_weights_flat[188]
  PIN direct_weights_flat[189]
    DIRECTION INPUT ;
    USE SIGNAL ;
    ANTENNAGATEAREA 0.196500 ;
    PORT
      LAYER met2 ;
        RECT 305.990 516.000 306.270 520.000 ;
    END
  END direct_weights_flat[189]
  PIN direct_weights_flat[18]
    DIRECTION INPUT ;
    USE SIGNAL ;
    ANTENNAGATEAREA 0.196500 ;
    PORT
      LAYER met3 ;
        RECT 0.000 333.240 4.000 333.840 ;
    END
  END direct_weights_flat[18]
  PIN direct_weights_flat[190]
    DIRECTION INPUT ;
    USE SIGNAL ;
    ANTENNAGATEAREA 0.196500 ;
    PORT
      LAYER met2 ;
        RECT 325.310 516.000 325.590 520.000 ;
    END
  END direct_weights_flat[190]
  PIN direct_weights_flat[191]
    DIRECTION INPUT ;
    USE SIGNAL ;
    ANTENNAGATEAREA 0.196500 ;
    PORT
      LAYER met2 ;
        RECT 370.390 516.000 370.670 520.000 ;
    END
  END direct_weights_flat[191]
  PIN direct_weights_flat[192]
    DIRECTION INPUT ;
    USE SIGNAL ;
    ANTENNAGATEAREA 0.196500 ;
    PORT
      LAYER met2 ;
        RECT 476.650 0.000 476.930 4.000 ;
    END
  END direct_weights_flat[192]
  PIN direct_weights_flat[193]
    DIRECTION INPUT ;
    USE SIGNAL ;
    ANTENNAGATEAREA 0.126000 ;
    PORT
      LAYER met2 ;
        RECT 489.530 0.000 489.810 4.000 ;
    END
  END direct_weights_flat[193]
  PIN direct_weights_flat[194]
    DIRECTION INPUT ;
    USE SIGNAL ;
    ANTENNAGATEAREA 0.196500 ;
    PORT
      LAYER met2 ;
        RECT 312.430 0.000 312.710 4.000 ;
    END
  END direct_weights_flat[194]
  PIN direct_weights_flat[195]
    DIRECTION INPUT ;
    USE SIGNAL ;
    ANTENNAGATEAREA 0.196500 ;
    PORT
      LAYER met3 ;
        RECT 516.000 57.840 520.000 58.440 ;
    END
  END direct_weights_flat[195]
  PIN direct_weights_flat[196]
    DIRECTION INPUT ;
    USE SIGNAL ;
    ANTENNAGATEAREA 0.196500 ;
    PORT
      LAYER met2 ;
        RECT 392.930 0.000 393.210 4.000 ;
    END
  END direct_weights_flat[196]
  PIN direct_weights_flat[197]
    DIRECTION INPUT ;
    USE SIGNAL ;
    ANTENNAGATEAREA 0.196500 ;
    PORT
      LAYER met3 ;
        RECT 516.000 91.840 520.000 92.440 ;
    END
  END direct_weights_flat[197]
  PIN direct_weights_flat[198]
    DIRECTION INPUT ;
    USE SIGNAL ;
    ANTENNAGATEAREA 0.196500 ;
    PORT
      LAYER met2 ;
        RECT 386.490 0.000 386.770 4.000 ;
    END
  END direct_weights_flat[198]
  PIN direct_weights_flat[199]
    DIRECTION INPUT ;
    USE SIGNAL ;
    ANTENNAGATEAREA 0.196500 ;
    PORT
      LAYER met3 ;
        RECT 516.000 119.040 520.000 119.640 ;
    END
  END direct_weights_flat[199]
  PIN direct_weights_flat[19]
    DIRECTION INPUT ;
    USE SIGNAL ;
    ANTENNAGATEAREA 0.196500 ;
    PORT
      LAYER met3 ;
        RECT 0.000 340.040 4.000 340.640 ;
    END
  END direct_weights_flat[19]
  PIN direct_weights_flat[1]
    DIRECTION INPUT ;
    USE SIGNAL ;
    ANTENNAGATEAREA 0.196500 ;
    PORT
      LAYER met3 ;
        RECT 0.000 309.440 4.000 310.040 ;
    END
  END direct_weights_flat[1]
  PIN direct_weights_flat[200]
    DIRECTION INPUT ;
    USE SIGNAL ;
    ANTENNAGATEAREA 0.196500 ;
    PORT
      LAYER met2 ;
        RECT 431.570 0.000 431.850 4.000 ;
    END
  END direct_weights_flat[200]
  PIN direct_weights_flat[201]
    DIRECTION INPUT ;
    USE SIGNAL ;
    ANTENNAGATEAREA 0.196500 ;
    PORT
      LAYER met2 ;
        RECT 415.470 0.000 415.750 4.000 ;
    END
  END direct_weights_flat[201]
  PIN direct_weights_flat[202]
    DIRECTION INPUT ;
    USE SIGNAL ;
    ANTENNAGATEAREA 0.196500 ;
    PORT
      LAYER met2 ;
        RECT 338.190 0.000 338.470 4.000 ;
    END
  END direct_weights_flat[202]
  PIN direct_weights_flat[203]
    DIRECTION INPUT ;
    USE SIGNAL ;
    ANTENNAGATEAREA 0.196500 ;
    PORT
      LAYER met3 ;
        RECT 516.000 98.640 520.000 99.240 ;
    END
  END direct_weights_flat[203]
  PIN direct_weights_flat[204]
    DIRECTION INPUT ;
    USE SIGNAL ;
    ANTENNAGATEAREA 0.196500 ;
    PORT
      LAYER met2 ;
        RECT 450.890 0.000 451.170 4.000 ;
    END
  END direct_weights_flat[204]
  PIN direct_weights_flat[205]
    DIRECTION INPUT ;
    USE SIGNAL ;
    ANTENNAGATEAREA 0.196500 ;
    PORT
      LAYER met2 ;
        RECT 434.790 0.000 435.070 4.000 ;
    END
  END direct_weights_flat[205]
  PIN direct_weights_flat[206]
    DIRECTION INPUT ;
    USE SIGNAL ;
    ANTENNAGATEAREA 0.196500 ;
    PORT
      LAYER met2 ;
        RECT 341.410 0.000 341.690 4.000 ;
    END
  END direct_weights_flat[206]
  PIN direct_weights_flat[207]
    DIRECTION INPUT ;
    USE SIGNAL ;
    ANTENNAGATEAREA 0.196500 ;
    PORT
      LAYER met2 ;
        RECT 515.290 0.000 515.570 4.000 ;
    END
  END direct_weights_flat[207]
  PIN direct_weights_flat[208]
    DIRECTION INPUT ;
    USE SIGNAL ;
    ANTENNAGATEAREA 0.196500 ;
    PORT
      LAYER met3 ;
        RECT 516.000 190.440 520.000 191.040 ;
    END
  END direct_weights_flat[208]
  PIN direct_weights_flat[209]
    DIRECTION INPUT ;
    USE SIGNAL ;
    ANTENNAGATEAREA 0.196500 ;
    PORT
      LAYER met3 ;
        RECT 516.000 125.840 520.000 126.440 ;
    END
  END direct_weights_flat[209]
  PIN direct_weights_flat[20]
    DIRECTION INPUT ;
    USE SIGNAL ;
    ANTENNAGATEAREA 0.196500 ;
    PORT
      LAYER met3 ;
        RECT 0.000 329.840 4.000 330.440 ;
    END
  END direct_weights_flat[20]
  PIN direct_weights_flat[210]
    DIRECTION INPUT ;
    USE SIGNAL ;
    ANTENNAGATEAREA 0.196500 ;
    PORT
      LAYER met3 ;
        RECT 516.000 115.640 520.000 116.240 ;
    END
  END direct_weights_flat[210]
  PIN direct_weights_flat[211]
    DIRECTION INPUT ;
    USE SIGNAL ;
    ANTENNAGATEAREA 0.126000 ;
    PORT
      LAYER met3 ;
        RECT 516.000 431.840 520.000 432.440 ;
    END
  END direct_weights_flat[211]
  PIN direct_weights_flat[212]
    DIRECTION INPUT ;
    USE SIGNAL ;
    ANTENNAGATEAREA 0.196500 ;
    PORT
      LAYER met3 ;
        RECT 516.000 129.240 520.000 129.840 ;
    END
  END direct_weights_flat[212]
  PIN direct_weights_flat[213]
    DIRECTION INPUT ;
    USE SIGNAL ;
    ANTENNAGATEAREA 0.196500 ;
    PORT
      LAYER met3 ;
        RECT 516.000 210.840 520.000 211.440 ;
    END
  END direct_weights_flat[213]
  PIN direct_weights_flat[214]
    DIRECTION INPUT ;
    USE SIGNAL ;
    ANTENNAGATEAREA 0.196500 ;
    PORT
      LAYER met3 ;
        RECT 516.000 173.440 520.000 174.040 ;
    END
  END direct_weights_flat[214]
  PIN direct_weights_flat[215]
    DIRECTION INPUT ;
    USE SIGNAL ;
    ANTENNAGATEAREA 0.196500 ;
    PORT
      LAYER met3 ;
        RECT 516.000 74.840 520.000 75.440 ;
    END
  END direct_weights_flat[215]
  PIN direct_weights_flat[216]
    DIRECTION INPUT ;
    USE SIGNAL ;
    ANTENNAGATEAREA 0.196500 ;
    PORT
      LAYER met3 ;
        RECT 516.000 166.640 520.000 167.240 ;
    END
  END direct_weights_flat[216]
  PIN direct_weights_flat[217]
    DIRECTION INPUT ;
    USE SIGNAL ;
    ANTENNAGATEAREA 0.196500 ;
    PORT
      LAYER met3 ;
        RECT 516.000 146.240 520.000 146.840 ;
    END
  END direct_weights_flat[217]
  PIN direct_weights_flat[218]
    DIRECTION INPUT ;
    USE SIGNAL ;
    ANTENNAGATEAREA 0.196500 ;
    PORT
      LAYER met3 ;
        RECT 516.000 176.840 520.000 177.440 ;
    END
  END direct_weights_flat[218]
  PIN direct_weights_flat[219]
    DIRECTION INPUT ;
    USE SIGNAL ;
    ANTENNAGATEAREA 0.196500 ;
    PORT
      LAYER met3 ;
        RECT 516.000 193.840 520.000 194.440 ;
    END
  END direct_weights_flat[219]
  PIN direct_weights_flat[21]
    DIRECTION INPUT ;
    USE SIGNAL ;
    ANTENNAGATEAREA 0.196500 ;
    PORT
      LAYER met3 ;
        RECT 0.000 360.440 4.000 361.040 ;
    END
  END direct_weights_flat[21]
  PIN direct_weights_flat[220]
    DIRECTION INPUT ;
    USE SIGNAL ;
    ANTENNAGATEAREA 0.196500 ;
    PORT
      LAYER met3 ;
        RECT 516.000 183.640 520.000 184.240 ;
    END
  END direct_weights_flat[220]
  PIN direct_weights_flat[221]
    DIRECTION INPUT ;
    USE SIGNAL ;
    ANTENNAGATEAREA 0.196500 ;
    PORT
      LAYER met3 ;
        RECT 516.000 207.440 520.000 208.040 ;
    END
  END direct_weights_flat[221]
  PIN direct_weights_flat[222]
    DIRECTION INPUT ;
    USE SIGNAL ;
    ANTENNAGATEAREA 0.196500 ;
    PORT
      LAYER met3 ;
        RECT 516.000 187.040 520.000 187.640 ;
    END
  END direct_weights_flat[222]
  PIN direct_weights_flat[223]
    DIRECTION INPUT ;
    USE SIGNAL ;
    ANTENNAGATEAREA 0.196500 ;
    PORT
      LAYER met3 ;
        RECT 516.000 156.440 520.000 157.040 ;
    END
  END direct_weights_flat[223]
  PIN direct_weights_flat[224]
    DIRECTION INPUT ;
    USE SIGNAL ;
    ANTENNAGATEAREA 0.196500 ;
    PORT
      LAYER met3 ;
        RECT 516.000 394.440 520.000 395.040 ;
    END
  END direct_weights_flat[224]
  PIN direct_weights_flat[225]
    DIRECTION INPUT ;
    USE SIGNAL ;
    ANTENNAGATEAREA 0.196500 ;
    PORT
      LAYER met3 ;
        RECT 516.000 377.440 520.000 378.040 ;
    END
  END direct_weights_flat[225]
  PIN direct_weights_flat[226]
    DIRECTION INPUT ;
    USE SIGNAL ;
    ANTENNAGATEAREA 0.196500 ;
    PORT
      LAYER met3 ;
        RECT 516.000 380.840 520.000 381.440 ;
    END
  END direct_weights_flat[226]
  PIN direct_weights_flat[227]
    DIRECTION INPUT ;
    USE SIGNAL ;
    ANTENNAGATEAREA 0.196500 ;
    PORT
      LAYER met3 ;
        RECT 516.000 326.440 520.000 327.040 ;
    END
  END direct_weights_flat[227]
  PIN direct_weights_flat[228]
    DIRECTION INPUT ;
    USE SIGNAL ;
    ANTENNAGATEAREA 0.196500 ;
    PORT
      LAYER met3 ;
        RECT 516.000 350.240 520.000 350.840 ;
    END
  END direct_weights_flat[228]
  PIN direct_weights_flat[229]
    DIRECTION INPUT ;
    USE SIGNAL ;
    ANTENNAGATEAREA 0.196500 ;
    PORT
      LAYER met3 ;
        RECT 516.000 285.640 520.000 286.240 ;
    END
  END direct_weights_flat[229]
  PIN direct_weights_flat[22]
    DIRECTION INPUT ;
    USE SIGNAL ;
    ANTENNAGATEAREA 0.196500 ;
    PORT
      LAYER met3 ;
        RECT 0.000 448.840 4.000 449.440 ;
    END
  END direct_weights_flat[22]
  PIN direct_weights_flat[230]
    DIRECTION INPUT ;
    USE SIGNAL ;
    ANTENNAGATEAREA 0.196500 ;
    PORT
      LAYER met3 ;
        RECT 516.000 367.240 520.000 367.840 ;
    END
  END direct_weights_flat[230]
  PIN direct_weights_flat[231]
    DIRECTION INPUT ;
    USE SIGNAL ;
    ANTENNAGATEAREA 0.196500 ;
    PORT
      LAYER met3 ;
        RECT 516.000 295.840 520.000 296.440 ;
    END
  END direct_weights_flat[231]
  PIN direct_weights_flat[232]
    DIRECTION INPUT ;
    USE SIGNAL ;
    ANTENNAGATEAREA 0.196500 ;
    PORT
      LAYER met3 ;
        RECT 516.000 428.440 520.000 429.040 ;
    END
  END direct_weights_flat[232]
  PIN direct_weights_flat[233]
    DIRECTION INPUT ;
    USE SIGNAL ;
    ANTENNAGATEAREA 0.196500 ;
    PORT
      LAYER met3 ;
        RECT 516.000 302.640 520.000 303.240 ;
    END
  END direct_weights_flat[233]
  PIN direct_weights_flat[234]
    DIRECTION INPUT ;
    USE SIGNAL ;
    ANTENNAGATEAREA 0.196500 ;
    PORT
      LAYER met3 ;
        RECT 516.000 329.840 520.000 330.440 ;
    END
  END direct_weights_flat[234]
  PIN direct_weights_flat[235]
    DIRECTION INPUT ;
    USE SIGNAL ;
    ANTENNAGATEAREA 0.196500 ;
    PORT
      LAYER met3 ;
        RECT 516.000 299.240 520.000 299.840 ;
    END
  END direct_weights_flat[235]
  PIN direct_weights_flat[236]
    DIRECTION INPUT ;
    USE SIGNAL ;
    ANTENNAGATEAREA 0.196500 ;
    PORT
      LAYER met3 ;
        RECT 516.000 360.440 520.000 361.040 ;
    END
  END direct_weights_flat[236]
  PIN direct_weights_flat[237]
    DIRECTION INPUT ;
    USE SIGNAL ;
    ANTENNAGATEAREA 0.196500 ;
    PORT
      LAYER met3 ;
        RECT 516.000 363.840 520.000 364.440 ;
    END
  END direct_weights_flat[237]
  PIN direct_weights_flat[238]
    DIRECTION INPUT ;
    USE SIGNAL ;
    ANTENNAGATEAREA 0.196500 ;
    PORT
      LAYER met3 ;
        RECT 516.000 357.040 520.000 357.640 ;
    END
  END direct_weights_flat[238]
  PIN direct_weights_flat[239]
    DIRECTION INPUT ;
    USE SIGNAL ;
    ANTENNAGATEAREA 0.196500 ;
    PORT
      LAYER met3 ;
        RECT 516.000 346.840 520.000 347.440 ;
    END
  END direct_weights_flat[239]
  PIN direct_weights_flat[23]
    DIRECTION INPUT ;
    USE SIGNAL ;
    ANTENNAGATEAREA 0.196500 ;
    PORT
      LAYER met3 ;
        RECT 0.000 465.840 4.000 466.440 ;
    END
  END direct_weights_flat[23]
  PIN direct_weights_flat[240]
    DIRECTION INPUT ;
    USE SIGNAL ;
    ANTENNAGATEAREA 0.196500 ;
    PORT
      LAYER met3 ;
        RECT 516.000 224.440 520.000 225.040 ;
    END
  END direct_weights_flat[240]
  PIN direct_weights_flat[241]
    DIRECTION INPUT ;
    USE SIGNAL ;
    ANTENNAGATEAREA 0.196500 ;
    PORT
      LAYER met3 ;
        RECT 516.000 234.640 520.000 235.240 ;
    END
  END direct_weights_flat[241]
  PIN direct_weights_flat[242]
    DIRECTION INPUT ;
    USE SIGNAL ;
    ANTENNAGATEAREA 0.213000 ;
    PORT
      LAYER met3 ;
        RECT 516.000 435.240 520.000 435.840 ;
    END
  END direct_weights_flat[242]
  PIN direct_weights_flat[243]
    DIRECTION INPUT ;
    USE SIGNAL ;
    ANTENNAGATEAREA 0.196500 ;
    PORT
      LAYER met3 ;
        RECT 516.000 268.640 520.000 269.240 ;
    END
  END direct_weights_flat[243]
  PIN direct_weights_flat[244]
    DIRECTION INPUT ;
    USE SIGNAL ;
    ANTENNAGATEAREA 0.196500 ;
    PORT
      LAYER met3 ;
        RECT 516.000 251.640 520.000 252.240 ;
    END
  END direct_weights_flat[244]
  PIN direct_weights_flat[245]
    DIRECTION INPUT ;
    USE SIGNAL ;
    ANTENNAGATEAREA 0.196500 ;
    PORT
      LAYER met3 ;
        RECT 516.000 289.040 520.000 289.640 ;
    END
  END direct_weights_flat[245]
  PIN direct_weights_flat[246]
    DIRECTION INPUT ;
    USE SIGNAL ;
    ANTENNAGATEAREA 0.196500 ;
    PORT
      LAYER met3 ;
        RECT 516.000 217.640 520.000 218.240 ;
    END
  END direct_weights_flat[246]
  PIN direct_weights_flat[247]
    DIRECTION INPUT ;
    USE SIGNAL ;
    ANTENNAGATEAREA 0.196500 ;
    PORT
      LAYER met3 ;
        RECT 516.000 275.440 520.000 276.040 ;
    END
  END direct_weights_flat[247]
  PIN direct_weights_flat[248]
    DIRECTION INPUT ;
    USE SIGNAL ;
    ANTENNAGATEAREA 0.196500 ;
    PORT
      LAYER met3 ;
        RECT 516.000 139.440 520.000 140.040 ;
    END
  END direct_weights_flat[248]
  PIN direct_weights_flat[249]
    DIRECTION INPUT ;
    USE SIGNAL ;
    ANTENNAGATEAREA 0.196500 ;
    PORT
      LAYER met3 ;
        RECT 516.000 278.840 520.000 279.440 ;
    END
  END direct_weights_flat[249]
  PIN direct_weights_flat[24]
    DIRECTION INPUT ;
    USE SIGNAL ;
    ANTENNAGATEAREA 0.196500 ;
    PORT
      LAYER met3 ;
        RECT 0.000 438.640 4.000 439.240 ;
    END
  END direct_weights_flat[24]
  PIN direct_weights_flat[250]
    DIRECTION INPUT ;
    USE SIGNAL ;
    ANTENNAGATEAREA 0.196500 ;
    PORT
      LAYER met3 ;
        RECT 516.000 221.040 520.000 221.640 ;
    END
  END direct_weights_flat[250]
  PIN direct_weights_flat[251]
    DIRECTION INPUT ;
    USE SIGNAL ;
    ANTENNAGATEAREA 0.196500 ;
    PORT
      LAYER met3 ;
        RECT 516.000 255.040 520.000 255.640 ;
    END
  END direct_weights_flat[251]
  PIN direct_weights_flat[252]
    DIRECTION INPUT ;
    USE SIGNAL ;
    ANTENNAGATEAREA 0.196500 ;
    PORT
      LAYER met3 ;
        RECT 516.000 102.040 520.000 102.640 ;
    END
  END direct_weights_flat[252]
  PIN direct_weights_flat[253]
    DIRECTION INPUT ;
    USE SIGNAL ;
    ANTENNAGATEAREA 0.196500 ;
    PORT
      LAYER met3 ;
        RECT 516.000 238.040 520.000 238.640 ;
    END
  END direct_weights_flat[253]
  PIN direct_weights_flat[254]
    DIRECTION INPUT ;
    USE SIGNAL ;
    ANTENNAGATEAREA 0.196500 ;
    PORT
      LAYER met3 ;
        RECT 516.000 88.440 520.000 89.040 ;
    END
  END direct_weights_flat[254]
  PIN direct_weights_flat[255]
    DIRECTION INPUT ;
    USE SIGNAL ;
    ANTENNAGATEAREA 0.196500 ;
    PORT
      LAYER met3 ;
        RECT 516.000 261.840 520.000 262.440 ;
    END
  END direct_weights_flat[255]
  PIN direct_weights_flat[25]
    DIRECTION INPUT ;
    USE SIGNAL ;
    ANTENNAGATEAREA 0.196500 ;
    PORT
      LAYER met3 ;
        RECT 0.000 357.040 4.000 357.640 ;
    END
  END direct_weights_flat[25]
  PIN direct_weights_flat[26]
    DIRECTION INPUT ;
    USE SIGNAL ;
    ANTENNAGATEAREA 0.196500 ;
    PORT
      LAYER met3 ;
        RECT 0.000 425.040 4.000 425.640 ;
    END
  END direct_weights_flat[26]
  PIN direct_weights_flat[27]
    DIRECTION INPUT ;
    USE SIGNAL ;
    ANTENNAGATEAREA 0.196500 ;
    PORT
      LAYER met3 ;
        RECT 0.000 353.640 4.000 354.240 ;
    END
  END direct_weights_flat[27]
  PIN direct_weights_flat[28]
    DIRECTION INPUT ;
    USE SIGNAL ;
    ANTENNAGATEAREA 0.196500 ;
    PORT
      LAYER met3 ;
        RECT 0.000 401.240 4.000 401.840 ;
    END
  END direct_weights_flat[28]
  PIN direct_weights_flat[29]
    DIRECTION INPUT ;
    USE SIGNAL ;
    ANTENNAGATEAREA 0.196500 ;
    PORT
      LAYER met3 ;
        RECT 0.000 346.840 4.000 347.440 ;
    END
  END direct_weights_flat[29]
  PIN direct_weights_flat[2]
    DIRECTION INPUT ;
    USE SIGNAL ;
    ANTENNAGATEAREA 0.196500 ;
    PORT
      LAYER met3 ;
        RECT 0.000 306.040 4.000 306.640 ;
    END
  END direct_weights_flat[2]
  PIN direct_weights_flat[30]
    DIRECTION INPUT ;
    USE SIGNAL ;
    ANTENNAGATEAREA 0.196500 ;
    PORT
      LAYER met3 ;
        RECT 0.000 367.240 4.000 367.840 ;
    END
  END direct_weights_flat[30]
  PIN direct_weights_flat[31]
    DIRECTION INPUT ;
    USE SIGNAL ;
    ANTENNAGATEAREA 0.196500 ;
    PORT
      LAYER met3 ;
        RECT 0.000 316.240 4.000 316.840 ;
    END
  END direct_weights_flat[31]
  PIN direct_weights_flat[32]
    DIRECTION INPUT ;
    USE SIGNAL ;
    ANTENNAGATEAREA 0.196500 ;
    PORT
      LAYER met2 ;
        RECT 122.450 516.000 122.730 520.000 ;
    END
  END direct_weights_flat[32]
  PIN direct_weights_flat[33]
    DIRECTION INPUT ;
    USE SIGNAL ;
    ANTENNAGATEAREA 0.196500 ;
    PORT
      LAYER met3 ;
        RECT 0.000 482.840 4.000 483.440 ;
    END
  END direct_weights_flat[33]
  PIN direct_weights_flat[34]
    DIRECTION INPUT ;
    USE SIGNAL ;
    ANTENNAGATEAREA 0.196500 ;
    PORT
      LAYER met3 ;
        RECT 0.000 370.640 4.000 371.240 ;
    END
  END direct_weights_flat[34]
  PIN direct_weights_flat[35]
    DIRECTION INPUT ;
    USE SIGNAL ;
    ANTENNAGATEAREA 0.196500 ;
    PORT
      LAYER met2 ;
        RECT 164.310 516.000 164.590 520.000 ;
    END
  END direct_weights_flat[35]
  PIN direct_weights_flat[36]
    DIRECTION INPUT ;
    USE SIGNAL ;
    ANTENNAGATEAREA 0.196500 ;
    PORT
      LAYER met3 ;
        RECT 0.000 431.840 4.000 432.440 ;
    END
  END direct_weights_flat[36]
  PIN direct_weights_flat[37]
    DIRECTION INPUT ;
    USE SIGNAL ;
    ANTENNAGATEAREA 0.196500 ;
    PORT
      LAYER met2 ;
        RECT 99.910 516.000 100.190 520.000 ;
    END
  END direct_weights_flat[37]
  PIN direct_weights_flat[38]
    DIRECTION INPUT ;
    USE SIGNAL ;
    ANTENNAGATEAREA 0.196500 ;
    PORT
      LAYER met3 ;
        RECT 0.000 435.240 4.000 435.840 ;
    END
  END direct_weights_flat[38]
  PIN direct_weights_flat[39]
    DIRECTION INPUT ;
    USE SIGNAL ;
    ANTENNAGATEAREA 0.196500 ;
    PORT
      LAYER met2 ;
        RECT 112.790 516.000 113.070 520.000 ;
    END
  END direct_weights_flat[39]
  PIN direct_weights_flat[3]
    DIRECTION INPUT ;
    USE SIGNAL ;
    ANTENNAGATEAREA 0.213000 ;
    PORT
      LAYER met3 ;
        RECT 0.000 510.040 4.000 510.640 ;
    END
  END direct_weights_flat[3]
  PIN direct_weights_flat[40]
    DIRECTION INPUT ;
    USE SIGNAL ;
    ANTENNAGATEAREA 0.126000 ;
    PORT
      LAYER met3 ;
        RECT 0.000 380.840 4.000 381.440 ;
    END
  END direct_weights_flat[40]
  PIN direct_weights_flat[41]
    DIRECTION INPUT ;
    USE SIGNAL ;
    ANTENNAGATEAREA 0.196500 ;
    PORT
      LAYER met2 ;
        RECT 61.270 516.000 61.550 520.000 ;
    END
  END direct_weights_flat[41]
  PIN direct_weights_flat[42]
    DIRECTION INPUT ;
    USE SIGNAL ;
    ANTENNAGATEAREA 0.196500 ;
    PORT
      LAYER met2 ;
        RECT 119.230 516.000 119.510 520.000 ;
    END
  END direct_weights_flat[42]
  PIN direct_weights_flat[43]
    DIRECTION INPUT ;
    USE SIGNAL ;
    ANTENNAGATEAREA 0.196500 ;
    PORT
      LAYER met2 ;
        RECT 77.370 516.000 77.650 520.000 ;
    END
  END direct_weights_flat[43]
  PIN direct_weights_flat[44]
    DIRECTION INPUT ;
    USE SIGNAL ;
    ANTENNAGATEAREA 0.196500 ;
    PORT
      LAYER met2 ;
        RECT 128.890 516.000 129.170 520.000 ;
    END
  END direct_weights_flat[44]
  PIN direct_weights_flat[45]
    DIRECTION INPUT ;
    USE SIGNAL ;
    ANTENNAGATEAREA 0.196500 ;
    PORT
      LAYER met2 ;
        RECT 109.570 516.000 109.850 520.000 ;
    END
  END direct_weights_flat[45]
  PIN direct_weights_flat[46]
    DIRECTION INPUT ;
    USE SIGNAL ;
    ANTENNAGATEAREA 0.196500 ;
    PORT
      LAYER met2 ;
        RECT 132.110 516.000 132.390 520.000 ;
    END
  END direct_weights_flat[46]
  PIN direct_weights_flat[47]
    DIRECTION INPUT ;
    USE SIGNAL ;
    ANTENNAGATEAREA 0.196500 ;
    PORT
      LAYER met3 ;
        RECT 0.000 408.040 4.000 408.640 ;
    END
  END direct_weights_flat[47]
  PIN direct_weights_flat[48]
    DIRECTION INPUT ;
    USE SIGNAL ;
    ANTENNAGATEAREA 0.196500 ;
    PORT
      LAYER met3 ;
        RECT 0.000 156.440 4.000 157.040 ;
    END
  END direct_weights_flat[48]
  PIN direct_weights_flat[49]
    DIRECTION INPUT ;
    USE SIGNAL ;
    ANTENNAGATEAREA 0.196500 ;
    PORT
      LAYER met3 ;
        RECT 0.000 91.840 4.000 92.440 ;
    END
  END direct_weights_flat[49]
  PIN direct_weights_flat[4]
    DIRECTION INPUT ;
    USE SIGNAL ;
    ANTENNAGATEAREA 0.196500 ;
    PORT
      LAYER met3 ;
        RECT 0.000 302.640 4.000 303.240 ;
    END
  END direct_weights_flat[4]
  PIN direct_weights_flat[50]
    DIRECTION INPUT ;
    USE SIGNAL ;
    ANTENNAGATEAREA 0.196500 ;
    PORT
      LAYER met3 ;
        RECT 0.000 71.440 4.000 72.040 ;
    END
  END direct_weights_flat[50]
  PIN direct_weights_flat[51]
    DIRECTION INPUT ;
    USE SIGNAL ;
    ANTENNAGATEAREA 0.196500 ;
    PORT
      LAYER met3 ;
        RECT 0.000 210.840 4.000 211.440 ;
    END
  END direct_weights_flat[51]
  PIN direct_weights_flat[52]
    DIRECTION INPUT ;
    USE SIGNAL ;
    ANTENNAGATEAREA 0.196500 ;
    PORT
      LAYER met3 ;
        RECT 0.000 44.240 4.000 44.840 ;
    END
  END direct_weights_flat[52]
  PIN direct_weights_flat[53]
    DIRECTION INPUT ;
    USE SIGNAL ;
    ANTENNAGATEAREA 0.196500 ;
    PORT
      LAYER met3 ;
        RECT 0.000 221.040 4.000 221.640 ;
    END
  END direct_weights_flat[53]
  PIN direct_weights_flat[54]
    DIRECTION INPUT ;
    USE SIGNAL ;
    ANTENNAGATEAREA 0.196500 ;
    PORT
      LAYER met3 ;
        RECT 0.000 207.440 4.000 208.040 ;
    END
  END direct_weights_flat[54]
  PIN direct_weights_flat[55]
    DIRECTION INPUT ;
    USE SIGNAL ;
    ANTENNAGATEAREA 0.196500 ;
    PORT
      LAYER met3 ;
        RECT 0.000 98.640 4.000 99.240 ;
    END
  END direct_weights_flat[55]
  PIN direct_weights_flat[56]
    DIRECTION INPUT ;
    USE SIGNAL ;
    ANTENNAGATEAREA 0.196500 ;
    PORT
      LAYER met3 ;
        RECT 0.000 85.040 4.000 85.640 ;
    END
  END direct_weights_flat[56]
  PIN direct_weights_flat[57]
    DIRECTION INPUT ;
    USE SIGNAL ;
    ANTENNAGATEAREA 0.126000 ;
    PORT
      LAYER met3 ;
        RECT 0.000 20.440 4.000 21.040 ;
    END
  END direct_weights_flat[57]
  PIN direct_weights_flat[58]
    DIRECTION INPUT ;
    USE SIGNAL ;
    ANTENNAGATEAREA 0.196500 ;
    PORT
      LAYER met3 ;
        RECT 0.000 17.040 4.000 17.640 ;
    END
  END direct_weights_flat[58]
  PIN direct_weights_flat[59]
    DIRECTION INPUT ;
    USE SIGNAL ;
    ANTENNAGATEAREA 0.196500 ;
    PORT
      LAYER met3 ;
        RECT 0.000 40.840 4.000 41.440 ;
    END
  END direct_weights_flat[59]
  PIN direct_weights_flat[5]
    DIRECTION INPUT ;
    USE SIGNAL ;
    ANTENNAGATEAREA 0.196500 ;
    PORT
      LAYER met3 ;
        RECT 0.000 363.840 4.000 364.440 ;
    END
  END direct_weights_flat[5]
  PIN direct_weights_flat[60]
    DIRECTION INPUT ;
    USE SIGNAL ;
    ANTENNAGATEAREA 0.196500 ;
    PORT
      LAYER met3 ;
        RECT 0.000 197.240 4.000 197.840 ;
    END
  END direct_weights_flat[60]
  PIN direct_weights_flat[61]
    DIRECTION INPUT ;
    USE SIGNAL ;
    ANTENNAGATEAREA 0.196500 ;
    PORT
      LAYER met3 ;
        RECT 0.000 193.840 4.000 194.440 ;
    END
  END direct_weights_flat[61]
  PIN direct_weights_flat[62]
    DIRECTION INPUT ;
    USE SIGNAL ;
    ANTENNAGATEAREA 0.196500 ;
    PORT
      LAYER met3 ;
        RECT 0.000 125.840 4.000 126.440 ;
    END
  END direct_weights_flat[62]
  PIN direct_weights_flat[63]
    DIRECTION INPUT ;
    USE SIGNAL ;
    ANTENNAGATEAREA 0.196500 ;
    PORT
      LAYER met3 ;
        RECT 0.000 95.240 4.000 95.840 ;
    END
  END direct_weights_flat[63]
  PIN direct_weights_flat[64]
    DIRECTION INPUT ;
    USE SIGNAL ;
    ANTENNAGATEAREA 0.196500 ;
    PORT
      LAYER met3 ;
        RECT 0.000 68.040 4.000 68.640 ;
    END
  END direct_weights_flat[64]
  PIN direct_weights_flat[65]
    DIRECTION INPUT ;
    USE SIGNAL ;
    ANTENNAGATEAREA 0.196500 ;
    PORT
      LAYER met3 ;
        RECT 0.000 51.040 4.000 51.640 ;
    END
  END direct_weights_flat[65]
  PIN direct_weights_flat[66]
    DIRECTION INPUT ;
    USE SIGNAL ;
    ANTENNAGATEAREA 0.196500 ;
    PORT
      LAYER met3 ;
        RECT 0.000 180.240 4.000 180.840 ;
    END
  END direct_weights_flat[66]
  PIN direct_weights_flat[67]
    DIRECTION INPUT ;
    USE SIGNAL ;
    ANTENNAGATEAREA 0.196500 ;
    PORT
      LAYER met2 ;
        RECT 173.970 0.000 174.250 4.000 ;
    END
  END direct_weights_flat[67]
  PIN direct_weights_flat[68]
    DIRECTION INPUT ;
    USE SIGNAL ;
    ANTENNAGATEAREA 0.196500 ;
    PORT
      LAYER met3 ;
        RECT 0.000 163.240 4.000 163.840 ;
    END
  END direct_weights_flat[68]
  PIN direct_weights_flat[69]
    DIRECTION INPUT ;
    USE SIGNAL ;
    ANTENNAGATEAREA 0.196500 ;
    PORT
      LAYER met2 ;
        RECT 138.550 0.000 138.830 4.000 ;
    END
  END direct_weights_flat[69]
  PIN direct_weights_flat[6]
    DIRECTION INPUT ;
    USE SIGNAL ;
    ANTENNAGATEAREA 0.159000 ;
    PORT
      LAYER met2 ;
        RECT 87.030 516.000 87.310 520.000 ;
    END
  END direct_weights_flat[6]
  PIN direct_weights_flat[70]
    DIRECTION INPUT ;
    USE SIGNAL ;
    ANTENNAGATEAREA 0.126000 ;
    PORT
      LAYER met2 ;
        RECT 154.650 0.000 154.930 4.000 ;
    END
  END direct_weights_flat[70]
  PIN direct_weights_flat[71]
    DIRECTION INPUT ;
    USE SIGNAL ;
    ANTENNAGATEAREA 0.196500 ;
    PORT
      LAYER met2 ;
        RECT 99.910 0.000 100.190 4.000 ;
    END
  END direct_weights_flat[71]
  PIN direct_weights_flat[72]
    DIRECTION INPUT ;
    USE SIGNAL ;
    ANTENNAGATEAREA 0.196500 ;
    PORT
      LAYER met2 ;
        RECT 64.490 0.000 64.770 4.000 ;
    END
  END direct_weights_flat[72]
  PIN direct_weights_flat[73]
    DIRECTION INPUT ;
    USE SIGNAL ;
    ANTENNAGATEAREA 0.196500 ;
    PORT
      LAYER met2 ;
        RECT 167.530 0.000 167.810 4.000 ;
    END
  END direct_weights_flat[73]
  PIN direct_weights_flat[74]
    DIRECTION INPUT ;
    USE SIGNAL ;
    ANTENNAGATEAREA 0.196500 ;
    PORT
      LAYER met2 ;
        RECT 58.050 0.000 58.330 4.000 ;
    END
  END direct_weights_flat[74]
  PIN direct_weights_flat[75]
    DIRECTION INPUT ;
    USE SIGNAL ;
    ANTENNAGATEAREA 0.196500 ;
    PORT
      LAYER met2 ;
        RECT 125.670 0.000 125.950 4.000 ;
    END
  END direct_weights_flat[75]
  PIN direct_weights_flat[76]
    DIRECTION INPUT ;
    USE SIGNAL ;
    ANTENNAGATEAREA 0.196500 ;
    PORT
      LAYER met2 ;
        RECT 70.930 0.000 71.210 4.000 ;
    END
  END direct_weights_flat[76]
  PIN direct_weights_flat[77]
    DIRECTION INPUT ;
    USE SIGNAL ;
    ANTENNAGATEAREA 0.196500 ;
    PORT
      LAYER met2 ;
        RECT 122.450 0.000 122.730 4.000 ;
    END
  END direct_weights_flat[77]
  PIN direct_weights_flat[78]
    DIRECTION INPUT ;
    USE SIGNAL ;
    ANTENNAGATEAREA 0.213000 ;
    PORT
      LAYER met2 ;
        RECT 157.870 0.000 158.150 4.000 ;
    END
  END direct_weights_flat[78]
  PIN direct_weights_flat[79]
    DIRECTION INPUT ;
    USE SIGNAL ;
    ANTENNAGATEAREA 0.196500 ;
    PORT
      LAYER met2 ;
        RECT 116.010 0.000 116.290 4.000 ;
    END
  END direct_weights_flat[79]
  PIN direct_weights_flat[7]
    DIRECTION INPUT ;
    USE SIGNAL ;
    ANTENNAGATEAREA 0.213000 ;
    PORT
      LAYER met2 ;
        RECT 138.550 516.000 138.830 520.000 ;
    END
  END direct_weights_flat[7]
  PIN direct_weights_flat[80]
    DIRECTION INPUT ;
    USE SIGNAL ;
    ANTENNAGATEAREA 0.196500 ;
    PORT
      LAYER met2 ;
        RECT 215.830 516.000 216.110 520.000 ;
    END
  END direct_weights_flat[80]
  PIN direct_weights_flat[81]
    DIRECTION INPUT ;
    USE SIGNAL ;
    ANTENNAGATEAREA 0.196500 ;
    PORT
      LAYER met2 ;
        RECT 170.750 516.000 171.030 520.000 ;
    END
  END direct_weights_flat[81]
  PIN direct_weights_flat[82]
    DIRECTION INPUT ;
    USE SIGNAL ;
    ANTENNAGATEAREA 0.196500 ;
    PORT
      LAYER met2 ;
        RECT 83.810 516.000 84.090 520.000 ;
    END
  END direct_weights_flat[82]
  PIN direct_weights_flat[83]
    DIRECTION INPUT ;
    USE SIGNAL ;
    ANTENNAGATEAREA 0.196500 ;
    PORT
      LAYER met2 ;
        RECT 238.370 516.000 238.650 520.000 ;
    END
  END direct_weights_flat[83]
  PIN direct_weights_flat[84]
    DIRECTION INPUT ;
    USE SIGNAL ;
    ANTENNAGATEAREA 0.196500 ;
    PORT
      LAYER met2 ;
        RECT 93.470 516.000 93.750 520.000 ;
    END
  END direct_weights_flat[84]
  PIN direct_weights_flat[85]
    DIRECTION INPUT ;
    USE SIGNAL ;
    ANTENNAGATEAREA 0.213000 ;
    PORT
      LAYER met2 ;
        RECT 412.250 516.000 412.530 520.000 ;
    END
  END direct_weights_flat[85]
  PIN direct_weights_flat[86]
    DIRECTION INPUT ;
    USE SIGNAL ;
    ANTENNAGATEAREA 0.196500 ;
    PORT
      LAYER met2 ;
        RECT 125.670 516.000 125.950 520.000 ;
    END
  END direct_weights_flat[86]
  PIN direct_weights_flat[87]
    DIRECTION INPUT ;
    USE SIGNAL ;
    ANTENNAGATEAREA 0.196500 ;
    PORT
      LAYER met2 ;
        RECT 241.590 516.000 241.870 520.000 ;
    END
  END direct_weights_flat[87]
  PIN direct_weights_flat[88]
    DIRECTION INPUT ;
    USE SIGNAL ;
    ANTENNAGATEAREA 0.196500 ;
    PORT
      LAYER met2 ;
        RECT 190.070 516.000 190.350 520.000 ;
    END
  END direct_weights_flat[88]
  PIN direct_weights_flat[89]
    DIRECTION INPUT ;
    USE SIGNAL ;
    ANTENNAGATEAREA 0.196500 ;
    PORT
      LAYER met2 ;
        RECT 225.490 516.000 225.770 520.000 ;
    END
  END direct_weights_flat[89]
  PIN direct_weights_flat[8]
    DIRECTION INPUT ;
    USE SIGNAL ;
    ANTENNAGATEAREA 0.213000 ;
    PORT
      LAYER met2 ;
        RECT 80.590 516.000 80.870 520.000 ;
    END
  END direct_weights_flat[8]
  PIN direct_weights_flat[90]
    DIRECTION INPUT ;
    USE SIGNAL ;
    ANTENNAGATEAREA 0.196500 ;
    PORT
      LAYER met2 ;
        RECT 196.510 516.000 196.790 520.000 ;
    END
  END direct_weights_flat[90]
  PIN direct_weights_flat[91]
    DIRECTION INPUT ;
    USE SIGNAL ;
    ANTENNAGATEAREA 0.196500 ;
    PORT
      LAYER met2 ;
        RECT 228.710 516.000 228.990 520.000 ;
    END
  END direct_weights_flat[91]
  PIN direct_weights_flat[92]
    DIRECTION INPUT ;
    USE SIGNAL ;
    ANTENNAGATEAREA 0.196500 ;
    PORT
      LAYER met2 ;
        RECT 212.610 516.000 212.890 520.000 ;
    END
  END direct_weights_flat[92]
  PIN direct_weights_flat[93]
    DIRECTION INPUT ;
    USE SIGNAL ;
    ANTENNAGATEAREA 0.196500 ;
    PORT
      LAYER met2 ;
        RECT 222.270 516.000 222.550 520.000 ;
    END
  END direct_weights_flat[93]
  PIN direct_weights_flat[94]
    DIRECTION INPUT ;
    USE SIGNAL ;
    ANTENNAGATEAREA 0.196500 ;
    PORT
      LAYER met2 ;
        RECT 173.970 516.000 174.250 520.000 ;
    END
  END direct_weights_flat[94]
  PIN direct_weights_flat[95]
    DIRECTION INPUT ;
    USE SIGNAL ;
    ANTENNAGATEAREA 0.196500 ;
    PORT
      LAYER met2 ;
        RECT 177.190 516.000 177.470 520.000 ;
    END
  END direct_weights_flat[95]
  PIN direct_weights_flat[96]
    DIRECTION INPUT ;
    USE SIGNAL ;
    ANTENNAGATEAREA 0.159000 ;
    PORT
      LAYER met3 ;
        RECT 516.000 81.640 520.000 82.240 ;
    END
  END direct_weights_flat[96]
  PIN direct_weights_flat[97]
    DIRECTION INPUT ;
    USE SIGNAL ;
    ANTENNAGATEAREA 0.159000 ;
    PORT
      LAYER met3 ;
        RECT 516.000 30.640 520.000 31.240 ;
    END
  END direct_weights_flat[97]
  PIN direct_weights_flat[98]
    DIRECTION INPUT ;
    USE SIGNAL ;
    ANTENNAGATEAREA 0.159000 ;
    PORT
      LAYER met3 ;
        RECT 516.000 27.240 520.000 27.840 ;
    END
  END direct_weights_flat[98]
  PIN direct_weights_flat[99]
    DIRECTION INPUT ;
    USE SIGNAL ;
    ANTENNAGATEAREA 0.213000 ;
    PORT
      LAYER met3 ;
        RECT 516.000 61.240 520.000 61.840 ;
    END
  END direct_weights_flat[99]
  PIN direct_weights_flat[9]
    DIRECTION INPUT ;
    USE SIGNAL ;
    ANTENNAGATEAREA 0.159000 ;
    PORT
      LAYER met2 ;
        RECT 135.330 516.000 135.610 520.000 ;
    END
  END direct_weights_flat[9]
  PIN double_error_detected
    DIRECTION OUTPUT ;
    USE SIGNAL ;
    PORT
      LAYER met3 ;
        RECT 516.000 54.440 520.000 55.040 ;
    END
  END double_error_detected
  PIN fault_inject_en
    DIRECTION INPUT ;
    USE SIGNAL ;
    PORT
      LAYER met3 ;
        RECT 516.000 459.040 520.000 459.640 ;
    END
  END fault_inject_en
  PIN fault_mask[0]
    DIRECTION INPUT ;
    USE SIGNAL ;
    PORT
      LAYER met3 ;
        RECT 516.000 10.240 520.000 10.840 ;
    END
  END fault_mask[0]
  PIN fault_mask[10]
    DIRECTION INPUT ;
    USE SIGNAL ;
    PORT
      LAYER met3 ;
        RECT 516.000 516.840 520.000 517.440 ;
    END
  END fault_mask[10]
  PIN fault_mask[11]
    DIRECTION INPUT ;
    USE SIGNAL ;
    PORT
      LAYER met3 ;
        RECT 516.000 462.440 520.000 463.040 ;
    END
  END fault_mask[11]
  PIN fault_mask[12]
    DIRECTION INPUT ;
    USE SIGNAL ;
    PORT
      LAYER met3 ;
        RECT 516.000 445.440 520.000 446.040 ;
    END
  END fault_mask[12]
  PIN fault_mask[13]
    DIRECTION INPUT ;
    USE SIGNAL ;
    PORT
      LAYER met3 ;
        RECT 516.000 489.640 520.000 490.240 ;
    END
  END fault_mask[13]
  PIN fault_mask[14]
    DIRECTION INPUT ;
    USE SIGNAL ;
    PORT
      LAYER met3 ;
        RECT 516.000 472.640 520.000 473.240 ;
    END
  END fault_mask[14]
  PIN fault_mask[15]
    DIRECTION INPUT ;
    USE SIGNAL ;
    PORT
      LAYER met3 ;
        RECT 516.000 13.640 520.000 14.240 ;
    END
  END fault_mask[15]
  PIN fault_mask[16]
    DIRECTION INPUT ;
    USE SIGNAL ;
    PORT
      LAYER met3 ;
        RECT 516.000 455.640 520.000 456.240 ;
    END
  END fault_mask[16]
  PIN fault_mask[17]
    DIRECTION INPUT ;
    USE SIGNAL ;
    PORT
      LAYER met3 ;
        RECT 516.000 513.440 520.000 514.040 ;
    END
  END fault_mask[17]
  PIN fault_mask[18]
    DIRECTION INPUT ;
    USE SIGNAL ;
    PORT
      LAYER met3 ;
        RECT 516.000 476.040 520.000 476.640 ;
    END
  END fault_mask[18]
  PIN fault_mask[19]
    DIRECTION INPUT ;
    USE SIGNAL ;
    PORT
      LAYER met3 ;
        RECT 516.000 465.840 520.000 466.440 ;
    END
  END fault_mask[19]
  PIN fault_mask[1]
    DIRECTION INPUT ;
    USE SIGNAL ;
    PORT
      LAYER met3 ;
        RECT 516.000 506.640 520.000 507.240 ;
    END
  END fault_mask[1]
  PIN fault_mask[20]
    DIRECTION INPUT ;
    USE SIGNAL ;
    PORT
      LAYER met3 ;
        RECT 516.000 493.040 520.000 493.640 ;
    END
  END fault_mask[20]
  PIN fault_mask[21]
    DIRECTION INPUT ;
    USE SIGNAL ;
    PORT
      LAYER met3 ;
        RECT 516.000 499.840 520.000 500.440 ;
    END
  END fault_mask[21]
  PIN fault_mask[2]
    DIRECTION INPUT ;
    USE SIGNAL ;
    PORT
      LAYER met3 ;
        RECT 516.000 486.240 520.000 486.840 ;
    END
  END fault_mask[2]
  PIN fault_mask[3]
    DIRECTION INPUT ;
    USE SIGNAL ;
    PORT
      LAYER met3 ;
        RECT 516.000 448.840 520.000 449.440 ;
    END
  END fault_mask[3]
  PIN fault_mask[4]
    DIRECTION INPUT ;
    USE SIGNAL ;
    PORT
      LAYER met3 ;
        RECT 516.000 469.240 520.000 469.840 ;
    END
  END fault_mask[4]
  PIN fault_mask[5]
    DIRECTION INPUT ;
    USE SIGNAL ;
    PORT
      LAYER met3 ;
        RECT 516.000 6.840 520.000 7.440 ;
    END
  END fault_mask[5]
  PIN fault_mask[6]
    DIRECTION INPUT ;
    USE SIGNAL ;
    PORT
      LAYER met3 ;
        RECT 516.000 452.240 520.000 452.840 ;
    END
  END fault_mask[6]
  PIN fault_mask[7]
    DIRECTION INPUT ;
    USE SIGNAL ;
    PORT
      LAYER met3 ;
        RECT 516.000 503.240 520.000 503.840 ;
    END
  END fault_mask[7]
  PIN fault_mask[8]
    DIRECTION INPUT ;
    USE SIGNAL ;
    PORT
      LAYER met3 ;
        RECT 516.000 482.840 520.000 483.440 ;
    END
  END fault_mask[8]
  PIN fault_mask[9]
    DIRECTION INPUT ;
    USE SIGNAL ;
    PORT
      LAYER met3 ;
        RECT 516.000 3.440 520.000 4.040 ;
    END
  END fault_mask[9]
  PIN keyword_detected
    DIRECTION OUTPUT ;
    USE SIGNAL ;
    ANTENNADIFFAREA 0.891000 ;
    PORT
      LAYER met2 ;
        RECT 331.750 516.000 332.030 520.000 ;
    END
  END keyword_detected
  PIN pe_active[0]
    DIRECTION OUTPUT ;
    USE SIGNAL ;
    PORT
      LAYER met3 ;
        RECT 516.000 40.840 520.000 41.440 ;
    END
  END pe_active[0]
  PIN pe_active[10]
    DIRECTION OUTPUT ;
    USE SIGNAL ;
    PORT
      LAYER met3 ;
        RECT 516.000 20.440 520.000 21.040 ;
    END
  END pe_active[10]
  PIN pe_active[11]
    DIRECTION OUTPUT ;
    USE SIGNAL ;
    PORT
      LAYER met3 ;
        RECT 516.000 37.440 520.000 38.040 ;
    END
  END pe_active[11]
  PIN pe_active[12]
    DIRECTION OUTPUT ;
    USE SIGNAL ;
    PORT
      LAYER met3 ;
        RECT 516.000 47.640 520.000 48.240 ;
    END
  END pe_active[12]
  PIN pe_active[13]
    DIRECTION OUTPUT ;
    USE SIGNAL ;
    PORT
      LAYER met3 ;
        RECT 516.000 34.040 520.000 34.640 ;
    END
  END pe_active[13]
  PIN pe_active[14]
    DIRECTION OUTPUT ;
    USE SIGNAL ;
    PORT
      LAYER met2 ;
        RECT 193.290 516.000 193.570 520.000 ;
    END
  END pe_active[14]
  PIN pe_active[15]
    DIRECTION OUTPUT ;
    USE SIGNAL ;
    PORT
      LAYER met2 ;
        RECT 161.090 516.000 161.370 520.000 ;
    END
  END pe_active[15]
  PIN pe_active[1]
    DIRECTION OUTPUT ;
    USE SIGNAL ;
    PORT
      LAYER met2 ;
        RECT 116.010 516.000 116.290 520.000 ;
    END
  END pe_active[1]
  PIN pe_active[2]
    DIRECTION OUTPUT ;
    USE SIGNAL ;
    PORT
      LAYER met2 ;
        RECT 58.050 516.000 58.330 520.000 ;
    END
  END pe_active[2]
  PIN pe_active[3]
    DIRECTION OUTPUT ;
    USE SIGNAL ;
    PORT
      LAYER met2 ;
        RECT 299.550 516.000 299.830 520.000 ;
    END
  END pe_active[3]
  PIN pe_active[4]
    DIRECTION OUTPUT ;
    USE SIGNAL ;
    PORT
      LAYER met2 ;
        RECT 277.010 516.000 277.290 520.000 ;
    END
  END pe_active[4]
  PIN pe_active[5]
    DIRECTION OUTPUT ;
    USE SIGNAL ;
    PORT
      LAYER met2 ;
        RECT 103.130 516.000 103.410 520.000 ;
    END
  END pe_active[5]
  PIN pe_active[6]
    DIRECTION OUTPUT ;
    USE SIGNAL ;
    PORT
      LAYER met3 ;
        RECT 516.000 17.040 520.000 17.640 ;
    END
  END pe_active[6]
  PIN pe_active[7]
    DIRECTION OUTPUT ;
    USE SIGNAL ;
    PORT
      LAYER met3 ;
        RECT 516.000 44.240 520.000 44.840 ;
    END
  END pe_active[7]
  PIN pe_active[8]
    DIRECTION OUTPUT ;
    USE SIGNAL ;
    PORT
      LAYER met2 ;
        RECT 157.870 516.000 158.150 520.000 ;
    END
  END pe_active[8]
  PIN pe_active[9]
    DIRECTION OUTPUT ;
    USE SIGNAL ;
    PORT
      LAYER met3 ;
        RECT 516.000 23.840 520.000 24.440 ;
    END
  END pe_active[9]
  PIN rd_addr[0]
    DIRECTION INPUT ;
    USE SIGNAL ;
    PORT
      LAYER met3 ;
        RECT 516.000 510.040 520.000 510.640 ;
    END
  END rd_addr[0]
  PIN rd_addr[1]
    DIRECTION INPUT ;
    USE SIGNAL ;
    PORT
      LAYER met3 ;
        RECT 516.000 0.040 520.000 0.640 ;
    END
  END rd_addr[1]
  PIN rd_addr[2]
    DIRECTION INPUT ;
    USE SIGNAL ;
    PORT
      LAYER met3 ;
        RECT 516.000 496.440 520.000 497.040 ;
    END
  END rd_addr[2]
  PIN rd_addr[3]
    DIRECTION INPUT ;
    USE SIGNAL ;
    PORT
      LAYER met3 ;
        RECT 516.000 479.440 520.000 480.040 ;
    END
  END rd_addr[3]
  PIN rst_n
    DIRECTION INPUT ;
    USE SIGNAL ;
    ANTENNAGATEAREA 0.990000 ;
    PORT
      LAYER met2 ;
        RECT 380.050 516.000 380.330 520.000 ;
    END
  END rst_n
  PIN single_error_corrected
    DIRECTION OUTPUT ;
    USE SIGNAL ;
    PORT
      LAYER met2 ;
        RECT 315.650 516.000 315.930 520.000 ;
    END
  END single_error_corrected
  PIN threshold[0]
    DIRECTION INPUT ;
    USE SIGNAL ;
    ANTENNAGATEAREA 0.196500 ;
    PORT
      LAYER met2 ;
        RECT 367.170 516.000 367.450 520.000 ;
    END
  END threshold[0]
  PIN threshold[1]
    DIRECTION INPUT ;
    USE SIGNAL ;
    ANTENNAGATEAREA 0.196500 ;
    PORT
      LAYER met2 ;
        RECT 363.950 516.000 364.230 520.000 ;
    END
  END threshold[1]
  PIN threshold[2]
    DIRECTION INPUT ;
    USE SIGNAL ;
    ANTENNAGATEAREA 0.196500 ;
    PORT
      LAYER met2 ;
        RECT 360.730 516.000 361.010 520.000 ;
    END
  END threshold[2]
  PIN threshold[3]
    DIRECTION INPUT ;
    USE SIGNAL ;
    ANTENNAGATEAREA 0.196500 ;
    PORT
      LAYER met2 ;
        RECT 351.070 516.000 351.350 520.000 ;
    END
  END threshold[3]
  PIN threshold[4]
    DIRECTION INPUT ;
    USE SIGNAL ;
    ANTENNAGATEAREA 0.196500 ;
    PORT
      LAYER met2 ;
        RECT 344.630 516.000 344.910 520.000 ;
    END
  END threshold[4]
  PIN threshold[5]
    DIRECTION INPUT ;
    USE SIGNAL ;
    ANTENNAGATEAREA 0.196500 ;
    PORT
      LAYER met2 ;
        RECT 338.190 516.000 338.470 520.000 ;
    END
  END threshold[5]
  PIN threshold[6]
    DIRECTION INPUT ;
    USE SIGNAL ;
    ANTENNAGATEAREA 0.196500 ;
    PORT
      LAYER met2 ;
        RECT 334.970 516.000 335.250 520.000 ;
    END
  END threshold[6]
  PIN threshold[7]
    DIRECTION INPUT ;
    USE SIGNAL ;
    ANTENNAGATEAREA 0.196500 ;
    PORT
      LAYER met2 ;
        RECT 328.530 516.000 328.810 520.000 ;
    END
  END threshold[7]
  PIN threshold[8]
    DIRECTION INPUT ;
    USE SIGNAL ;
    ANTENNAGATEAREA 0.196500 ;
    PORT
      LAYER met2 ;
        RECT 354.290 516.000 354.570 520.000 ;
    END
  END threshold[8]
  PIN wr_addr[0]
    DIRECTION INPUT ;
    USE SIGNAL ;
    PORT
      LAYER met2 ;
        RECT 518.510 516.000 518.790 520.000 ;
    END
  END wr_addr[0]
  PIN wr_addr[1]
    DIRECTION INPUT ;
    USE SIGNAL ;
    PORT
      LAYER met2 ;
        RECT 515.290 516.000 515.570 520.000 ;
    END
  END wr_addr[1]
  PIN wr_addr[2]
    DIRECTION INPUT ;
    USE SIGNAL ;
    PORT
      LAYER met2 ;
        RECT 512.070 516.000 512.350 520.000 ;
    END
  END wr_addr[2]
  PIN wr_addr[3]
    DIRECTION INPUT ;
    USE SIGNAL ;
    PORT
      LAYER met2 ;
        RECT 508.850 516.000 509.130 520.000 ;
    END
  END wr_addr[3]
  PIN wr_data[0]
    DIRECTION INPUT ;
    USE SIGNAL ;
    PORT
      LAYER met2 ;
        RECT 505.630 516.000 505.910 520.000 ;
    END
  END wr_data[0]
  PIN wr_data[10]
    DIRECTION INPUT ;
    USE SIGNAL ;
    PORT
      LAYER met2 ;
        RECT 502.410 516.000 502.690 520.000 ;
    END
  END wr_data[10]
  PIN wr_data[11]
    DIRECTION INPUT ;
    USE SIGNAL ;
    PORT
      LAYER met2 ;
        RECT 499.190 516.000 499.470 520.000 ;
    END
  END wr_data[11]
  PIN wr_data[12]
    DIRECTION INPUT ;
    USE SIGNAL ;
    PORT
      LAYER met2 ;
        RECT 495.970 516.000 496.250 520.000 ;
    END
  END wr_data[12]
  PIN wr_data[13]
    DIRECTION INPUT ;
    USE SIGNAL ;
    PORT
      LAYER met2 ;
        RECT 492.750 516.000 493.030 520.000 ;
    END
  END wr_data[13]
  PIN wr_data[14]
    DIRECTION INPUT ;
    USE SIGNAL ;
    PORT
      LAYER met2 ;
        RECT 489.530 516.000 489.810 520.000 ;
    END
  END wr_data[14]
  PIN wr_data[15]
    DIRECTION INPUT ;
    USE SIGNAL ;
    PORT
      LAYER met2 ;
        RECT 486.310 516.000 486.590 520.000 ;
    END
  END wr_data[15]
  PIN wr_data[1]
    DIRECTION INPUT ;
    USE SIGNAL ;
    PORT
      LAYER met2 ;
        RECT 483.090 516.000 483.370 520.000 ;
    END
  END wr_data[1]
  PIN wr_data[2]
    DIRECTION INPUT ;
    USE SIGNAL ;
    PORT
      LAYER met2 ;
        RECT 479.870 516.000 480.150 520.000 ;
    END
  END wr_data[2]
  PIN wr_data[3]
    DIRECTION INPUT ;
    USE SIGNAL ;
    PORT
      LAYER met2 ;
        RECT 476.650 516.000 476.930 520.000 ;
    END
  END wr_data[3]
  PIN wr_data[4]
    DIRECTION INPUT ;
    USE SIGNAL ;
    PORT
      LAYER met2 ;
        RECT 473.430 516.000 473.710 520.000 ;
    END
  END wr_data[4]
  PIN wr_data[5]
    DIRECTION INPUT ;
    USE SIGNAL ;
    PORT
      LAYER met2 ;
        RECT 470.210 516.000 470.490 520.000 ;
    END
  END wr_data[5]
  PIN wr_data[6]
    DIRECTION INPUT ;
    USE SIGNAL ;
    PORT
      LAYER met2 ;
        RECT 466.990 516.000 467.270 520.000 ;
    END
  END wr_data[6]
  PIN wr_data[7]
    DIRECTION INPUT ;
    USE SIGNAL ;
    PORT
      LAYER met2 ;
        RECT 463.770 516.000 464.050 520.000 ;
    END
  END wr_data[7]
  PIN wr_data[8]
    DIRECTION INPUT ;
    USE SIGNAL ;
    PORT
      LAYER met2 ;
        RECT 460.550 516.000 460.830 520.000 ;
    END
  END wr_data[8]
  PIN wr_data[9]
    DIRECTION INPUT ;
    USE SIGNAL ;
    PORT
      LAYER met2 ;
        RECT 457.330 516.000 457.610 520.000 ;
    END
  END wr_data[9]
  PIN wr_en
    DIRECTION INPUT ;
    USE SIGNAL ;
    PORT
      LAYER met2 ;
        RECT 454.110 516.000 454.390 520.000 ;
    END
  END wr_en
  OBS
      LAYER nwell ;
        RECT 5.330 10.795 514.470 508.830 ;
      LAYER li1 ;
        RECT 5.520 10.795 514.280 508.725 ;
      LAYER met1 ;
        RECT 0.070 6.840 518.810 509.620 ;
      LAYER met2 ;
        RECT 0.100 515.720 54.550 517.325 ;
        RECT 55.390 515.720 57.770 517.325 ;
        RECT 58.610 515.720 60.990 517.325 ;
        RECT 61.830 515.720 64.210 517.325 ;
        RECT 65.050 515.720 67.430 517.325 ;
        RECT 68.270 515.720 70.650 517.325 ;
        RECT 71.490 515.720 73.870 517.325 ;
        RECT 74.710 515.720 77.090 517.325 ;
        RECT 77.930 515.720 80.310 517.325 ;
        RECT 81.150 515.720 83.530 517.325 ;
        RECT 84.370 515.720 86.750 517.325 ;
        RECT 87.590 515.720 89.970 517.325 ;
        RECT 90.810 515.720 93.190 517.325 ;
        RECT 94.030 515.720 96.410 517.325 ;
        RECT 97.250 515.720 99.630 517.325 ;
        RECT 100.470 515.720 102.850 517.325 ;
        RECT 103.690 515.720 106.070 517.325 ;
        RECT 106.910 515.720 109.290 517.325 ;
        RECT 110.130 515.720 112.510 517.325 ;
        RECT 113.350 515.720 115.730 517.325 ;
        RECT 116.570 515.720 118.950 517.325 ;
        RECT 119.790 515.720 122.170 517.325 ;
        RECT 123.010 515.720 125.390 517.325 ;
        RECT 126.230 515.720 128.610 517.325 ;
        RECT 129.450 515.720 131.830 517.325 ;
        RECT 132.670 515.720 135.050 517.325 ;
        RECT 135.890 515.720 138.270 517.325 ;
        RECT 139.110 515.720 141.490 517.325 ;
        RECT 142.330 515.720 144.710 517.325 ;
        RECT 145.550 515.720 147.930 517.325 ;
        RECT 148.770 515.720 151.150 517.325 ;
        RECT 151.990 515.720 154.370 517.325 ;
        RECT 155.210 515.720 157.590 517.325 ;
        RECT 158.430 515.720 160.810 517.325 ;
        RECT 161.650 515.720 164.030 517.325 ;
        RECT 164.870 515.720 167.250 517.325 ;
        RECT 168.090 515.720 170.470 517.325 ;
        RECT 171.310 515.720 173.690 517.325 ;
        RECT 174.530 515.720 176.910 517.325 ;
        RECT 177.750 515.720 180.130 517.325 ;
        RECT 180.970 515.720 183.350 517.325 ;
        RECT 184.190 515.720 186.570 517.325 ;
        RECT 187.410 515.720 189.790 517.325 ;
        RECT 190.630 515.720 193.010 517.325 ;
        RECT 193.850 515.720 196.230 517.325 ;
        RECT 197.070 515.720 199.450 517.325 ;
        RECT 200.290 515.720 202.670 517.325 ;
        RECT 203.510 515.720 205.890 517.325 ;
        RECT 206.730 515.720 209.110 517.325 ;
        RECT 209.950 515.720 212.330 517.325 ;
        RECT 213.170 515.720 215.550 517.325 ;
        RECT 216.390 515.720 218.770 517.325 ;
        RECT 219.610 515.720 221.990 517.325 ;
        RECT 222.830 515.720 225.210 517.325 ;
        RECT 226.050 515.720 228.430 517.325 ;
        RECT 229.270 515.720 231.650 517.325 ;
        RECT 232.490 515.720 234.870 517.325 ;
        RECT 235.710 515.720 238.090 517.325 ;
        RECT 238.930 515.720 241.310 517.325 ;
        RECT 242.150 515.720 244.530 517.325 ;
        RECT 245.370 515.720 247.750 517.325 ;
        RECT 248.590 515.720 250.970 517.325 ;
        RECT 251.810 515.720 254.190 517.325 ;
        RECT 255.030 515.720 257.410 517.325 ;
        RECT 258.250 515.720 260.630 517.325 ;
        RECT 261.470 515.720 263.850 517.325 ;
        RECT 264.690 515.720 267.070 517.325 ;
        RECT 267.910 515.720 270.290 517.325 ;
        RECT 271.130 515.720 273.510 517.325 ;
        RECT 274.350 515.720 276.730 517.325 ;
        RECT 277.570 515.720 279.950 517.325 ;
        RECT 280.790 515.720 283.170 517.325 ;
        RECT 284.010 515.720 286.390 517.325 ;
        RECT 287.230 515.720 289.610 517.325 ;
        RECT 290.450 515.720 292.830 517.325 ;
        RECT 293.670 515.720 296.050 517.325 ;
        RECT 296.890 515.720 299.270 517.325 ;
        RECT 300.110 515.720 302.490 517.325 ;
        RECT 303.330 515.720 305.710 517.325 ;
        RECT 306.550 515.720 308.930 517.325 ;
        RECT 309.770 515.720 312.150 517.325 ;
        RECT 312.990 515.720 315.370 517.325 ;
        RECT 316.210 515.720 318.590 517.325 ;
        RECT 319.430 515.720 321.810 517.325 ;
        RECT 322.650 515.720 325.030 517.325 ;
        RECT 325.870 515.720 328.250 517.325 ;
        RECT 329.090 515.720 331.470 517.325 ;
        RECT 332.310 515.720 334.690 517.325 ;
        RECT 335.530 515.720 337.910 517.325 ;
        RECT 338.750 515.720 341.130 517.325 ;
        RECT 341.970 515.720 344.350 517.325 ;
        RECT 345.190 515.720 347.570 517.325 ;
        RECT 348.410 515.720 350.790 517.325 ;
        RECT 351.630 515.720 354.010 517.325 ;
        RECT 354.850 515.720 357.230 517.325 ;
        RECT 358.070 515.720 360.450 517.325 ;
        RECT 361.290 515.720 363.670 517.325 ;
        RECT 364.510 515.720 366.890 517.325 ;
        RECT 367.730 515.720 370.110 517.325 ;
        RECT 370.950 515.720 373.330 517.325 ;
        RECT 374.170 515.720 376.550 517.325 ;
        RECT 377.390 515.720 379.770 517.325 ;
        RECT 380.610 515.720 382.990 517.325 ;
        RECT 383.830 515.720 386.210 517.325 ;
        RECT 387.050 515.720 389.430 517.325 ;
        RECT 390.270 515.720 392.650 517.325 ;
        RECT 393.490 515.720 395.870 517.325 ;
        RECT 396.710 515.720 399.090 517.325 ;
        RECT 399.930 515.720 402.310 517.325 ;
        RECT 403.150 515.720 405.530 517.325 ;
        RECT 406.370 515.720 408.750 517.325 ;
        RECT 409.590 515.720 411.970 517.325 ;
        RECT 412.810 515.720 453.830 517.325 ;
        RECT 454.670 515.720 457.050 517.325 ;
        RECT 457.890 515.720 460.270 517.325 ;
        RECT 461.110 515.720 463.490 517.325 ;
        RECT 464.330 515.720 466.710 517.325 ;
        RECT 467.550 515.720 469.930 517.325 ;
        RECT 470.770 515.720 473.150 517.325 ;
        RECT 473.990 515.720 476.370 517.325 ;
        RECT 477.210 515.720 479.590 517.325 ;
        RECT 480.430 515.720 482.810 517.325 ;
        RECT 483.650 515.720 486.030 517.325 ;
        RECT 486.870 515.720 489.250 517.325 ;
        RECT 490.090 515.720 492.470 517.325 ;
        RECT 493.310 515.720 495.690 517.325 ;
        RECT 496.530 515.720 498.910 517.325 ;
        RECT 499.750 515.720 502.130 517.325 ;
        RECT 502.970 515.720 505.350 517.325 ;
        RECT 506.190 515.720 508.570 517.325 ;
        RECT 509.410 515.720 511.790 517.325 ;
        RECT 512.630 515.720 515.010 517.325 ;
        RECT 515.850 515.720 518.230 517.325 ;
        RECT 0.100 4.280 518.780 515.720 ;
        RECT 0.650 0.155 3.030 4.280 ;
        RECT 3.870 0.155 6.250 4.280 ;
        RECT 7.090 0.155 9.470 4.280 ;
        RECT 10.310 0.155 12.690 4.280 ;
        RECT 13.530 0.155 15.910 4.280 ;
        RECT 16.750 0.155 19.130 4.280 ;
        RECT 19.970 0.155 22.350 4.280 ;
        RECT 23.190 0.155 25.570 4.280 ;
        RECT 26.410 0.155 28.790 4.280 ;
        RECT 29.630 0.155 32.010 4.280 ;
        RECT 32.850 0.155 35.230 4.280 ;
        RECT 36.070 0.155 38.450 4.280 ;
        RECT 39.290 0.155 41.670 4.280 ;
        RECT 42.510 0.155 44.890 4.280 ;
        RECT 45.730 0.155 48.110 4.280 ;
        RECT 48.950 0.155 51.330 4.280 ;
        RECT 52.170 0.155 54.550 4.280 ;
        RECT 55.390 0.155 57.770 4.280 ;
        RECT 58.610 0.155 60.990 4.280 ;
        RECT 61.830 0.155 64.210 4.280 ;
        RECT 65.050 0.155 67.430 4.280 ;
        RECT 68.270 0.155 70.650 4.280 ;
        RECT 71.490 0.155 73.870 4.280 ;
        RECT 74.710 0.155 77.090 4.280 ;
        RECT 77.930 0.155 80.310 4.280 ;
        RECT 81.150 0.155 83.530 4.280 ;
        RECT 84.370 0.155 86.750 4.280 ;
        RECT 87.590 0.155 89.970 4.280 ;
        RECT 90.810 0.155 93.190 4.280 ;
        RECT 94.030 0.155 96.410 4.280 ;
        RECT 97.250 0.155 99.630 4.280 ;
        RECT 100.470 0.155 102.850 4.280 ;
        RECT 103.690 0.155 106.070 4.280 ;
        RECT 106.910 0.155 109.290 4.280 ;
        RECT 110.130 0.155 112.510 4.280 ;
        RECT 113.350 0.155 115.730 4.280 ;
        RECT 116.570 0.155 118.950 4.280 ;
        RECT 119.790 0.155 122.170 4.280 ;
        RECT 123.010 0.155 125.390 4.280 ;
        RECT 126.230 0.155 128.610 4.280 ;
        RECT 129.450 0.155 131.830 4.280 ;
        RECT 132.670 0.155 135.050 4.280 ;
        RECT 135.890 0.155 138.270 4.280 ;
        RECT 139.110 0.155 141.490 4.280 ;
        RECT 142.330 0.155 144.710 4.280 ;
        RECT 145.550 0.155 147.930 4.280 ;
        RECT 148.770 0.155 151.150 4.280 ;
        RECT 151.990 0.155 154.370 4.280 ;
        RECT 155.210 0.155 157.590 4.280 ;
        RECT 158.430 0.155 160.810 4.280 ;
        RECT 161.650 0.155 164.030 4.280 ;
        RECT 164.870 0.155 167.250 4.280 ;
        RECT 168.090 0.155 170.470 4.280 ;
        RECT 171.310 0.155 173.690 4.280 ;
        RECT 174.530 0.155 176.910 4.280 ;
        RECT 177.750 0.155 180.130 4.280 ;
        RECT 180.970 0.155 183.350 4.280 ;
        RECT 184.190 0.155 186.570 4.280 ;
        RECT 187.410 0.155 189.790 4.280 ;
        RECT 190.630 0.155 193.010 4.280 ;
        RECT 193.850 0.155 196.230 4.280 ;
        RECT 197.070 0.155 199.450 4.280 ;
        RECT 200.290 0.155 202.670 4.280 ;
        RECT 203.510 0.155 205.890 4.280 ;
        RECT 206.730 0.155 209.110 4.280 ;
        RECT 209.950 0.155 212.330 4.280 ;
        RECT 213.170 0.155 215.550 4.280 ;
        RECT 216.390 0.155 218.770 4.280 ;
        RECT 219.610 0.155 221.990 4.280 ;
        RECT 222.830 0.155 225.210 4.280 ;
        RECT 226.050 0.155 228.430 4.280 ;
        RECT 229.270 0.155 231.650 4.280 ;
        RECT 232.490 0.155 234.870 4.280 ;
        RECT 235.710 0.155 238.090 4.280 ;
        RECT 238.930 0.155 241.310 4.280 ;
        RECT 242.150 0.155 244.530 4.280 ;
        RECT 245.370 0.155 247.750 4.280 ;
        RECT 248.590 0.155 250.970 4.280 ;
        RECT 251.810 0.155 254.190 4.280 ;
        RECT 255.030 0.155 257.410 4.280 ;
        RECT 258.250 0.155 260.630 4.280 ;
        RECT 261.470 0.155 263.850 4.280 ;
        RECT 264.690 0.155 267.070 4.280 ;
        RECT 267.910 0.155 270.290 4.280 ;
        RECT 271.130 0.155 273.510 4.280 ;
        RECT 274.350 0.155 276.730 4.280 ;
        RECT 277.570 0.155 279.950 4.280 ;
        RECT 280.790 0.155 283.170 4.280 ;
        RECT 284.010 0.155 286.390 4.280 ;
        RECT 287.230 0.155 289.610 4.280 ;
        RECT 290.450 0.155 292.830 4.280 ;
        RECT 293.670 0.155 296.050 4.280 ;
        RECT 296.890 0.155 299.270 4.280 ;
        RECT 300.110 0.155 302.490 4.280 ;
        RECT 303.330 0.155 305.710 4.280 ;
        RECT 306.550 0.155 308.930 4.280 ;
        RECT 309.770 0.155 312.150 4.280 ;
        RECT 312.990 0.155 315.370 4.280 ;
        RECT 316.210 0.155 318.590 4.280 ;
        RECT 319.430 0.155 321.810 4.280 ;
        RECT 322.650 0.155 325.030 4.280 ;
        RECT 325.870 0.155 328.250 4.280 ;
        RECT 329.090 0.155 331.470 4.280 ;
        RECT 332.310 0.155 334.690 4.280 ;
        RECT 335.530 0.155 337.910 4.280 ;
        RECT 338.750 0.155 341.130 4.280 ;
        RECT 341.970 0.155 344.350 4.280 ;
        RECT 345.190 0.155 347.570 4.280 ;
        RECT 348.410 0.155 350.790 4.280 ;
        RECT 351.630 0.155 354.010 4.280 ;
        RECT 354.850 0.155 357.230 4.280 ;
        RECT 358.070 0.155 360.450 4.280 ;
        RECT 361.290 0.155 363.670 4.280 ;
        RECT 364.510 0.155 366.890 4.280 ;
        RECT 367.730 0.155 370.110 4.280 ;
        RECT 370.950 0.155 373.330 4.280 ;
        RECT 374.170 0.155 376.550 4.280 ;
        RECT 377.390 0.155 379.770 4.280 ;
        RECT 380.610 0.155 382.990 4.280 ;
        RECT 383.830 0.155 386.210 4.280 ;
        RECT 387.050 0.155 389.430 4.280 ;
        RECT 390.270 0.155 392.650 4.280 ;
        RECT 393.490 0.155 395.870 4.280 ;
        RECT 396.710 0.155 399.090 4.280 ;
        RECT 399.930 0.155 402.310 4.280 ;
        RECT 403.150 0.155 405.530 4.280 ;
        RECT 406.370 0.155 408.750 4.280 ;
        RECT 409.590 0.155 411.970 4.280 ;
        RECT 412.810 0.155 415.190 4.280 ;
        RECT 416.030 0.155 418.410 4.280 ;
        RECT 419.250 0.155 421.630 4.280 ;
        RECT 422.470 0.155 424.850 4.280 ;
        RECT 425.690 0.155 428.070 4.280 ;
        RECT 428.910 0.155 431.290 4.280 ;
        RECT 432.130 0.155 434.510 4.280 ;
        RECT 435.350 0.155 437.730 4.280 ;
        RECT 438.570 0.155 440.950 4.280 ;
        RECT 441.790 0.155 444.170 4.280 ;
        RECT 445.010 0.155 447.390 4.280 ;
        RECT 448.230 0.155 450.610 4.280 ;
        RECT 451.450 0.155 453.830 4.280 ;
        RECT 454.670 0.155 457.050 4.280 ;
        RECT 457.890 0.155 460.270 4.280 ;
        RECT 461.110 0.155 463.490 4.280 ;
        RECT 464.330 0.155 466.710 4.280 ;
        RECT 467.550 0.155 469.930 4.280 ;
        RECT 470.770 0.155 473.150 4.280 ;
        RECT 473.990 0.155 476.370 4.280 ;
        RECT 477.210 0.155 479.590 4.280 ;
        RECT 480.430 0.155 482.810 4.280 ;
        RECT 483.650 0.155 486.030 4.280 ;
        RECT 486.870 0.155 489.250 4.280 ;
        RECT 490.090 0.155 492.470 4.280 ;
        RECT 493.310 0.155 495.690 4.280 ;
        RECT 496.530 0.155 498.910 4.280 ;
        RECT 499.750 0.155 502.130 4.280 ;
        RECT 502.970 0.155 505.350 4.280 ;
        RECT 506.190 0.155 508.570 4.280 ;
        RECT 509.410 0.155 511.790 4.280 ;
        RECT 512.630 0.155 515.010 4.280 ;
        RECT 515.850 0.155 518.230 4.280 ;
      LAYER met3 ;
        RECT 4.400 516.440 515.600 517.305 ;
        RECT 3.750 514.440 516.000 516.440 ;
        RECT 4.400 513.040 515.600 514.440 ;
        RECT 3.750 511.040 516.000 513.040 ;
        RECT 4.400 509.640 515.600 511.040 ;
        RECT 3.750 507.640 516.000 509.640 ;
        RECT 4.400 506.240 515.600 507.640 ;
        RECT 3.750 504.240 516.000 506.240 ;
        RECT 4.400 502.840 515.600 504.240 ;
        RECT 3.750 500.840 516.000 502.840 ;
        RECT 4.400 499.440 515.600 500.840 ;
        RECT 3.750 497.440 516.000 499.440 ;
        RECT 4.400 496.040 515.600 497.440 ;
        RECT 3.750 494.040 516.000 496.040 ;
        RECT 4.400 492.640 515.600 494.040 ;
        RECT 3.750 490.640 516.000 492.640 ;
        RECT 4.400 489.240 515.600 490.640 ;
        RECT 3.750 487.240 516.000 489.240 ;
        RECT 4.400 485.840 515.600 487.240 ;
        RECT 3.750 483.840 516.000 485.840 ;
        RECT 4.400 482.440 515.600 483.840 ;
        RECT 3.750 480.440 516.000 482.440 ;
        RECT 4.400 479.040 515.600 480.440 ;
        RECT 3.750 477.040 516.000 479.040 ;
        RECT 4.400 475.640 515.600 477.040 ;
        RECT 3.750 473.640 516.000 475.640 ;
        RECT 4.400 472.240 515.600 473.640 ;
        RECT 3.750 470.240 516.000 472.240 ;
        RECT 4.400 468.840 515.600 470.240 ;
        RECT 3.750 466.840 516.000 468.840 ;
        RECT 4.400 465.440 515.600 466.840 ;
        RECT 3.750 463.440 516.000 465.440 ;
        RECT 4.400 462.040 515.600 463.440 ;
        RECT 3.750 460.040 516.000 462.040 ;
        RECT 4.400 458.640 515.600 460.040 ;
        RECT 3.750 456.640 516.000 458.640 ;
        RECT 4.400 455.240 515.600 456.640 ;
        RECT 3.750 453.240 516.000 455.240 ;
        RECT 4.400 451.840 515.600 453.240 ;
        RECT 3.750 449.840 516.000 451.840 ;
        RECT 4.400 448.440 515.600 449.840 ;
        RECT 3.750 446.440 516.000 448.440 ;
        RECT 4.400 445.040 515.600 446.440 ;
        RECT 3.750 443.040 516.000 445.040 ;
        RECT 4.400 441.640 515.600 443.040 ;
        RECT 3.750 439.640 516.000 441.640 ;
        RECT 4.400 438.240 515.600 439.640 ;
        RECT 3.750 436.240 516.000 438.240 ;
        RECT 4.400 434.840 515.600 436.240 ;
        RECT 3.750 432.840 516.000 434.840 ;
        RECT 4.400 431.440 515.600 432.840 ;
        RECT 3.750 429.440 516.000 431.440 ;
        RECT 4.400 428.040 515.600 429.440 ;
        RECT 3.750 426.040 516.000 428.040 ;
        RECT 4.400 424.640 515.600 426.040 ;
        RECT 3.750 422.640 516.000 424.640 ;
        RECT 4.400 421.240 515.600 422.640 ;
        RECT 3.750 419.240 516.000 421.240 ;
        RECT 4.400 417.840 515.600 419.240 ;
        RECT 3.750 415.840 516.000 417.840 ;
        RECT 4.400 414.440 515.600 415.840 ;
        RECT 3.750 412.440 516.000 414.440 ;
        RECT 4.400 411.040 515.600 412.440 ;
        RECT 3.750 409.040 516.000 411.040 ;
        RECT 4.400 407.640 515.600 409.040 ;
        RECT 3.750 405.640 516.000 407.640 ;
        RECT 4.400 404.240 515.600 405.640 ;
        RECT 3.750 402.240 516.000 404.240 ;
        RECT 4.400 400.840 515.600 402.240 ;
        RECT 3.750 398.840 516.000 400.840 ;
        RECT 4.400 397.440 515.600 398.840 ;
        RECT 3.750 395.440 516.000 397.440 ;
        RECT 4.400 394.040 515.600 395.440 ;
        RECT 3.750 392.040 516.000 394.040 ;
        RECT 4.400 390.640 515.600 392.040 ;
        RECT 3.750 388.640 516.000 390.640 ;
        RECT 4.400 387.240 515.600 388.640 ;
        RECT 3.750 385.240 516.000 387.240 ;
        RECT 4.400 383.840 515.600 385.240 ;
        RECT 3.750 381.840 516.000 383.840 ;
        RECT 4.400 380.440 515.600 381.840 ;
        RECT 3.750 378.440 516.000 380.440 ;
        RECT 4.400 377.040 515.600 378.440 ;
        RECT 3.750 375.040 516.000 377.040 ;
        RECT 4.400 373.640 515.600 375.040 ;
        RECT 3.750 371.640 516.000 373.640 ;
        RECT 4.400 370.240 515.600 371.640 ;
        RECT 3.750 368.240 516.000 370.240 ;
        RECT 4.400 366.840 515.600 368.240 ;
        RECT 3.750 364.840 516.000 366.840 ;
        RECT 4.400 363.440 515.600 364.840 ;
        RECT 3.750 361.440 516.000 363.440 ;
        RECT 4.400 360.040 515.600 361.440 ;
        RECT 3.750 358.040 516.000 360.040 ;
        RECT 4.400 356.640 515.600 358.040 ;
        RECT 3.750 354.640 516.000 356.640 ;
        RECT 4.400 353.240 515.600 354.640 ;
        RECT 3.750 351.240 516.000 353.240 ;
        RECT 4.400 349.840 515.600 351.240 ;
        RECT 3.750 347.840 516.000 349.840 ;
        RECT 4.400 346.440 515.600 347.840 ;
        RECT 3.750 344.440 516.000 346.440 ;
        RECT 4.400 343.040 515.600 344.440 ;
        RECT 3.750 341.040 516.000 343.040 ;
        RECT 4.400 339.640 515.600 341.040 ;
        RECT 3.750 337.640 516.000 339.640 ;
        RECT 4.400 336.240 515.600 337.640 ;
        RECT 3.750 334.240 516.000 336.240 ;
        RECT 4.400 332.840 515.600 334.240 ;
        RECT 3.750 330.840 516.000 332.840 ;
        RECT 4.400 329.440 515.600 330.840 ;
        RECT 3.750 327.440 516.000 329.440 ;
        RECT 4.400 326.040 515.600 327.440 ;
        RECT 3.750 324.040 516.000 326.040 ;
        RECT 4.400 322.640 515.600 324.040 ;
        RECT 3.750 320.640 516.000 322.640 ;
        RECT 4.400 319.240 515.600 320.640 ;
        RECT 3.750 317.240 516.000 319.240 ;
        RECT 4.400 315.840 515.600 317.240 ;
        RECT 3.750 313.840 516.000 315.840 ;
        RECT 4.400 312.440 515.600 313.840 ;
        RECT 3.750 310.440 516.000 312.440 ;
        RECT 4.400 309.040 515.600 310.440 ;
        RECT 3.750 307.040 516.000 309.040 ;
        RECT 4.400 305.640 515.600 307.040 ;
        RECT 3.750 303.640 516.000 305.640 ;
        RECT 4.400 302.240 515.600 303.640 ;
        RECT 3.750 300.240 516.000 302.240 ;
        RECT 4.400 298.840 515.600 300.240 ;
        RECT 3.750 296.840 516.000 298.840 ;
        RECT 4.400 295.440 515.600 296.840 ;
        RECT 3.750 293.440 516.000 295.440 ;
        RECT 4.400 292.040 515.600 293.440 ;
        RECT 3.750 290.040 516.000 292.040 ;
        RECT 4.400 288.640 515.600 290.040 ;
        RECT 3.750 286.640 516.000 288.640 ;
        RECT 4.400 285.240 515.600 286.640 ;
        RECT 3.750 283.240 516.000 285.240 ;
        RECT 4.400 281.840 515.600 283.240 ;
        RECT 3.750 279.840 516.000 281.840 ;
        RECT 4.400 278.440 515.600 279.840 ;
        RECT 3.750 276.440 516.000 278.440 ;
        RECT 4.400 275.040 515.600 276.440 ;
        RECT 3.750 273.040 516.000 275.040 ;
        RECT 4.400 271.640 515.600 273.040 ;
        RECT 3.750 269.640 516.000 271.640 ;
        RECT 4.400 268.240 515.600 269.640 ;
        RECT 3.750 266.240 516.000 268.240 ;
        RECT 4.400 264.840 515.600 266.240 ;
        RECT 3.750 262.840 516.000 264.840 ;
        RECT 4.400 261.440 515.600 262.840 ;
        RECT 3.750 259.440 516.000 261.440 ;
        RECT 4.400 258.040 515.600 259.440 ;
        RECT 3.750 256.040 516.000 258.040 ;
        RECT 4.400 254.640 515.600 256.040 ;
        RECT 3.750 252.640 516.000 254.640 ;
        RECT 4.400 251.240 515.600 252.640 ;
        RECT 3.750 249.240 516.000 251.240 ;
        RECT 4.400 247.840 515.600 249.240 ;
        RECT 3.750 245.840 516.000 247.840 ;
        RECT 4.400 244.440 515.600 245.840 ;
        RECT 3.750 242.440 516.000 244.440 ;
        RECT 4.400 241.040 515.600 242.440 ;
        RECT 3.750 239.040 516.000 241.040 ;
        RECT 4.400 237.640 515.600 239.040 ;
        RECT 3.750 235.640 516.000 237.640 ;
        RECT 4.400 234.240 515.600 235.640 ;
        RECT 3.750 232.240 516.000 234.240 ;
        RECT 4.400 230.840 515.600 232.240 ;
        RECT 3.750 228.840 516.000 230.840 ;
        RECT 4.400 227.440 515.600 228.840 ;
        RECT 3.750 225.440 516.000 227.440 ;
        RECT 4.400 224.040 515.600 225.440 ;
        RECT 3.750 222.040 516.000 224.040 ;
        RECT 4.400 220.640 515.600 222.040 ;
        RECT 3.750 218.640 516.000 220.640 ;
        RECT 4.400 217.240 515.600 218.640 ;
        RECT 3.750 215.240 516.000 217.240 ;
        RECT 4.400 213.840 515.600 215.240 ;
        RECT 3.750 211.840 516.000 213.840 ;
        RECT 4.400 210.440 515.600 211.840 ;
        RECT 3.750 208.440 516.000 210.440 ;
        RECT 4.400 207.040 515.600 208.440 ;
        RECT 3.750 205.040 516.000 207.040 ;
        RECT 4.400 203.640 515.600 205.040 ;
        RECT 3.750 201.640 516.000 203.640 ;
        RECT 4.400 200.240 515.600 201.640 ;
        RECT 3.750 198.240 516.000 200.240 ;
        RECT 4.400 196.840 515.600 198.240 ;
        RECT 3.750 194.840 516.000 196.840 ;
        RECT 4.400 193.440 515.600 194.840 ;
        RECT 3.750 191.440 516.000 193.440 ;
        RECT 4.400 190.040 515.600 191.440 ;
        RECT 3.750 188.040 516.000 190.040 ;
        RECT 4.400 186.640 515.600 188.040 ;
        RECT 3.750 184.640 516.000 186.640 ;
        RECT 4.400 183.240 515.600 184.640 ;
        RECT 3.750 181.240 516.000 183.240 ;
        RECT 4.400 179.840 515.600 181.240 ;
        RECT 3.750 177.840 516.000 179.840 ;
        RECT 4.400 176.440 515.600 177.840 ;
        RECT 3.750 174.440 516.000 176.440 ;
        RECT 4.400 173.040 515.600 174.440 ;
        RECT 3.750 171.040 516.000 173.040 ;
        RECT 4.400 169.640 515.600 171.040 ;
        RECT 3.750 167.640 516.000 169.640 ;
        RECT 4.400 166.240 515.600 167.640 ;
        RECT 3.750 164.240 516.000 166.240 ;
        RECT 4.400 162.840 515.600 164.240 ;
        RECT 3.750 160.840 516.000 162.840 ;
        RECT 4.400 159.440 515.600 160.840 ;
        RECT 3.750 157.440 516.000 159.440 ;
        RECT 4.400 156.040 515.600 157.440 ;
        RECT 3.750 154.040 516.000 156.040 ;
        RECT 4.400 152.640 515.600 154.040 ;
        RECT 3.750 150.640 516.000 152.640 ;
        RECT 4.400 149.240 515.600 150.640 ;
        RECT 3.750 147.240 516.000 149.240 ;
        RECT 4.400 145.840 515.600 147.240 ;
        RECT 3.750 143.840 516.000 145.840 ;
        RECT 4.400 142.440 515.600 143.840 ;
        RECT 3.750 140.440 516.000 142.440 ;
        RECT 4.400 139.040 515.600 140.440 ;
        RECT 3.750 137.040 516.000 139.040 ;
        RECT 4.400 135.640 515.600 137.040 ;
        RECT 3.750 133.640 516.000 135.640 ;
        RECT 4.400 132.240 515.600 133.640 ;
        RECT 3.750 130.240 516.000 132.240 ;
        RECT 4.400 128.840 515.600 130.240 ;
        RECT 3.750 126.840 516.000 128.840 ;
        RECT 4.400 125.440 515.600 126.840 ;
        RECT 3.750 123.440 516.000 125.440 ;
        RECT 4.400 122.040 515.600 123.440 ;
        RECT 3.750 120.040 516.000 122.040 ;
        RECT 4.400 118.640 515.600 120.040 ;
        RECT 3.750 116.640 516.000 118.640 ;
        RECT 4.400 115.240 515.600 116.640 ;
        RECT 3.750 113.240 516.000 115.240 ;
        RECT 4.400 111.840 515.600 113.240 ;
        RECT 3.750 109.840 516.000 111.840 ;
        RECT 4.400 108.440 515.600 109.840 ;
        RECT 3.750 106.440 516.000 108.440 ;
        RECT 4.400 105.040 515.600 106.440 ;
        RECT 3.750 103.040 516.000 105.040 ;
        RECT 4.400 101.640 515.600 103.040 ;
        RECT 3.750 99.640 516.000 101.640 ;
        RECT 4.400 98.240 515.600 99.640 ;
        RECT 3.750 96.240 516.000 98.240 ;
        RECT 4.400 94.840 515.600 96.240 ;
        RECT 3.750 92.840 516.000 94.840 ;
        RECT 4.400 91.440 515.600 92.840 ;
        RECT 3.750 89.440 516.000 91.440 ;
        RECT 4.400 88.040 515.600 89.440 ;
        RECT 3.750 86.040 516.000 88.040 ;
        RECT 4.400 84.640 515.600 86.040 ;
        RECT 3.750 82.640 516.000 84.640 ;
        RECT 4.400 81.240 515.600 82.640 ;
        RECT 3.750 79.240 516.000 81.240 ;
        RECT 4.400 77.840 515.600 79.240 ;
        RECT 3.750 75.840 516.000 77.840 ;
        RECT 4.400 74.440 515.600 75.840 ;
        RECT 3.750 72.440 516.000 74.440 ;
        RECT 4.400 71.040 515.600 72.440 ;
        RECT 3.750 69.040 516.000 71.040 ;
        RECT 4.400 67.640 515.600 69.040 ;
        RECT 3.750 65.640 516.000 67.640 ;
        RECT 4.400 64.240 515.600 65.640 ;
        RECT 3.750 62.240 516.000 64.240 ;
        RECT 4.400 60.840 515.600 62.240 ;
        RECT 3.750 58.840 516.000 60.840 ;
        RECT 4.400 57.440 515.600 58.840 ;
        RECT 3.750 55.440 516.000 57.440 ;
        RECT 4.400 54.040 515.600 55.440 ;
        RECT 3.750 52.040 516.000 54.040 ;
        RECT 4.400 50.640 515.600 52.040 ;
        RECT 3.750 48.640 516.000 50.640 ;
        RECT 4.400 47.240 515.600 48.640 ;
        RECT 3.750 45.240 516.000 47.240 ;
        RECT 4.400 43.840 515.600 45.240 ;
        RECT 3.750 41.840 516.000 43.840 ;
        RECT 4.400 40.440 515.600 41.840 ;
        RECT 3.750 38.440 516.000 40.440 ;
        RECT 4.400 37.040 515.600 38.440 ;
        RECT 3.750 35.040 516.000 37.040 ;
        RECT 4.400 33.640 515.600 35.040 ;
        RECT 3.750 31.640 516.000 33.640 ;
        RECT 4.400 30.240 515.600 31.640 ;
        RECT 3.750 28.240 516.000 30.240 ;
        RECT 4.400 26.840 515.600 28.240 ;
        RECT 3.750 24.840 516.000 26.840 ;
        RECT 4.400 23.440 515.600 24.840 ;
        RECT 3.750 21.440 516.000 23.440 ;
        RECT 4.400 20.040 515.600 21.440 ;
        RECT 3.750 18.040 516.000 20.040 ;
        RECT 4.400 16.640 515.600 18.040 ;
        RECT 3.750 14.640 516.000 16.640 ;
        RECT 4.400 13.240 515.600 14.640 ;
        RECT 3.750 11.240 516.000 13.240 ;
        RECT 4.400 9.840 515.600 11.240 ;
        RECT 3.750 7.840 516.000 9.840 ;
        RECT 4.400 6.440 515.600 7.840 ;
        RECT 3.750 4.440 516.000 6.440 ;
        RECT 4.400 3.040 515.600 4.440 ;
        RECT 3.750 1.040 516.000 3.040 ;
        RECT 4.400 0.175 515.600 1.040 ;
      LAYER met4 ;
        RECT 3.975 15.815 15.345 504.385 ;
  END
END are_ubnn_kws_baseline_wrapper
END LIBRARY

